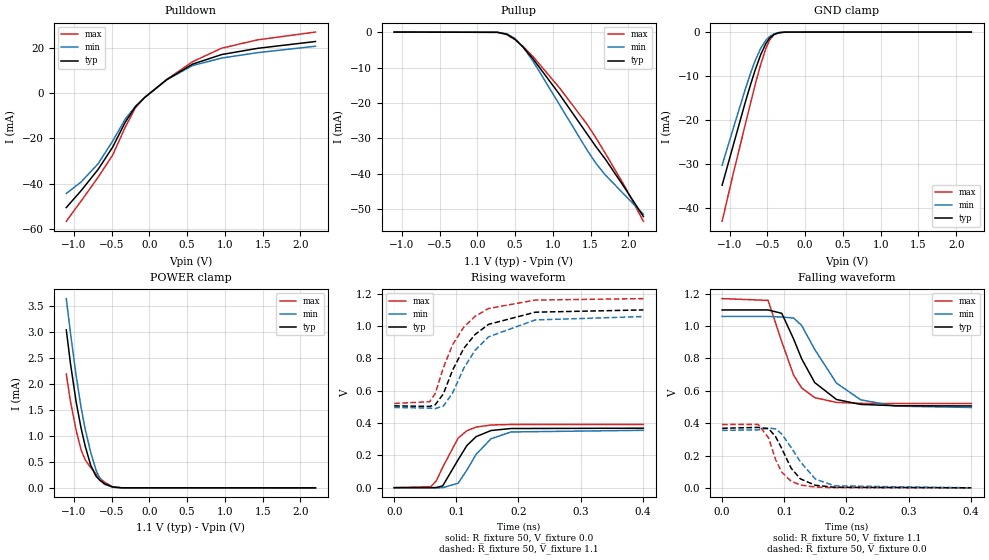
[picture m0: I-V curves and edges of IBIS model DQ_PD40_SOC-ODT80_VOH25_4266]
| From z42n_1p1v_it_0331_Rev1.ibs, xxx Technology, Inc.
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| DQ_PD40_SOC-ODT80_VOH25_4266
| (40 Ohm Pulldown, 80 Ohm System ODT Setting, VOH=VDDQ/2.5, 3200-4266Mbps)
[Model]   DQ_PD40_SOC-ODT80_VOH25_4266
Model_type   I/O
Vinl = 160.000mV
Vinh = 280.000mV
Vmeas = 220.000mV
Vref = 0.0mV
Cref = 0.0pF
Rref = 80.000Ohm
|   typ   min   max
|C_comp   0.834pF   0.784pF   0.884pF
C_comp_pullup   0.4170pF   0.3920pF   0.4420pF
C_comp_pulldown   0.4170pF   0.3920pF   0.4420pF
| Note: C_comp changes when the ODT circuit is enabled.
[Model Spec]
| Input threshold voltage corners
Vinl   0.1600V   0.1520V   0.1740V
Vinh   0.2800V   0.2720V   0.2940V
| Measurement voltage corners
Vmeas   0.2200V   0.2120V   0.2340V
| Timing spec test load voltage corners
Vref   0.0000V   0.0000V   0.0000V
| Dynamic Overshoot Parameters from LPDDR4 Specification
D_overshoot_ampl_h   0.30   NA   NA
D_overshoot_ampl_l   0.30   NA   NA
D_overshoot_area_h   0.1n   NA   NA
D_overshoot_area_l   0.1n   NA   NA
[Voltage Range]   1.1000V   1.0600V   1.1700V
[Pullup Reference]   1.1000V   1.0600V   1.1700V
| Junction Temperature (Ambient temp is 35C typ 95C min -40C max)
[Temperature Range]   50.0   110.0   -40.0
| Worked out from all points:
|   slope of the pulldown table from 0 to 0.165 V, typ, clamps not added: 36.9 ohm
|   slope of the pullup table from 0 to 0.165 V, typ, clamps not added: 17.7 kohm
|   GND clamp passes 1 mA (typ) near -0.45 V on its own axis
|   POWER clamp passes 1 mA (typ) near -0.88 V on its own axis
|   rising waveform, R_fixture 50, V_fixture 0.0: 20-80 % time 34.6ps typ, 38.2ps min, 31.6ps max; typ from 0.001 V to 0.368 V
|   falling waveform, R_fixture 50, V_fixture 1.1: 20-80 % time 45.6ps typ, 57.6ps min, 35.8ps max; typ from 1.1 V to 0.507 V
|   rising waveform, R_fixture 50, V_fixture 1.1: 20-80 % time 56.3ps typ, 59.8ps min, 51.7ps max; typ from 0.507 V to 1.1 V
|   falling waveform, R_fixture 50, V_fixture 0.0: 20-80 % time 31.3ps typ, 39.3ps min, 25.3ps max; typ from 0.368 V to 0.001 V
[Pulldown]
|   Voltage   I(typ)   I(min)   I(max)
-1.1V     -50.64mA   -44.4mA    -56.73mA
-905.3mV  -43.23mA   -39.35mA   -47.84mA
-677.6mV  -33.7mA    -31.18mA   -37.18mA
-486.2mV  -23.86mA   -21.19mA   -27.39mA
-317.9mV  -12.72mA   -11.35mA   -14.94mA
-182.6mV  -5.881mA   -5.661mA   -6.291mA
-63.8mV   -1.901mA   -1.884mA   -1.878mA
229.9mV   6.064mA    5.989mA    6.147mA
573.1mV   12.96mA    12.33mA    14.03mA
959.2mV   17.21mA    15.66mA    20.03mA
1.434V    19.96mA    18.04mA    23.71mA
2.2V      22.98mA    20.89mA    27.18mA
[GND Clamp]
|   Voltage   I(typ)   I(min)   I(max)
-1.1V     -34.75mA   -30.21mA   -42.92mA
-944.9mV  -25.23mA   -21.44mA   -31.56mA
-793.1mV  -15.92mA   -12.96mA   -20.97mA
-720.5mV  -11.75mA   -9.183mA   -15.88mA
-661.1mV  -8.569mA   -6.434mA   -11.86mA
-588.5mV  -5.115mA   -3.68mA    -7.305mA
-519.2mV  -2.566mA   -1.832mA   -3.663mA
-466.4mV  -1.295mA   -942uA     -1.691mA
-413.6mV  -565.1uA   -416.8uA   -621.5uA
-350.9mV  -165.9uA   -125.8uA   -147.9uA
-261.8mV  -17.69uA   -15.38uA   -11.03uA
2.2V      0A         0A         0A
[Pullup]
|   Voltage   I(typ)   I(min)   I(max)
-1.1V     4.106uA    7.431uA    1.361uA
266.2mV   -69.11uA   -66.76uA   -71.72uA
391.6mV   -603.6uA   -501uA     -718.6uA
500.5mV   -2.041mA   -1.829mA   -2.142mA
606.1mV   -4.221mA   -4.208mA   -4.061mA
741.4mV   -7.628mA   -8.301mA   -6.975mA
1.088V    -17.54mA   -20.45mA   -15.71mA
1.458V    -28.85mA   -33.42mA   -26.13mA
1.573V    -32.37mA   -37.08mA   -29.9mA
1.695V    -35.82mA   -40.29mA   -34.18mA
1.946V    -43.74mA   -45.84mA   -43.25mA
2.2V      -52.05mA   -51.4mA    -53.39mA
[POWER Clamp]
|   Voltage   I(typ)   I(min)   I(max)
-1.1V     3.033mA    3.633mA    2.184mA
-1.044V   2.381mA    2.967mA    1.653mA
-968mV    1.637mA    2.139mA    1.094mA
-905.3mV  1.155mA    1.553mA    732.3uA
-849.2mV  799uA      1.125mA    535.5uA
-776.6mV  434.1uA    683.2uA    390.2uA
-707.3mV  225.5uA    345.3uA    267.6uA
-651.2mV  138.6uA    162.4uA    181.2uA
-595.1mV  80.76uA    68.29uA    109.2uA
-486.2mV  16.72uA    10.16uA    20.92uA
-367.4mV  1.19uA     876.5nA    944.1nA
2.2V      0A         0A         0A
[Ramp]
|   typ   min   max
| 20% - 80%
dV/dt_r   220.67m/34.62p   212.99m/38.16p   234.73m/31.58p
dV/dt_f   356.03m/45.65p   337.71m/57.58p   389.19m/35.75p
| 25% - 75%
|dV/dt_r   183.89m/27.56p   177.50m/30.42p   195.60m/25.07p
|dV/dt_f   296.69m/36.41p   281.42m/45.98p   324.32m/28.47p
R_load = 50
[Rising Waveform]
R_fixture = 50
V_fixture = 0.0
|   Time   V(typ)   V(min)   V(max)
0s        576.2uV    460uV      427uV
59ps      302.1uV    60.2uV     6.861mV
68ps      1.699mV    -527.5uV   44.07mV
78ps      11.14mV    298.1uV    126.8mV
103ps     173.9mV    28.19mV    307.8mV
117ps     261.2mV    109.9mV    352.6mV
132ps     316.6mV    207.5mV    375.5mV
156ps     354.2mV    303.3mV    388.2mV
188ps     366.4mV    345.1mV    391.3mV
401ps     368.4mV    355.4mV    391.6mV
[Falling Waveform]
R_fixture   = 50
V_fixture   = 1.1
V_fixture_min = 1.06
V_fixture_max = 1.17
|   Time   V(typ)   V(min)   V(max)
0s        1.1V       1.06V      1.17V
74ps      1.1V       1.06V      1.159V
96ps      1.079V     1.056V     903.5mV
115ps     920.8mV    1.05V      697.3mV
128ps     797.9mV    1.004V     618.1mV
149ps     651.2mV    856.1mV    557.7mV
184ps     546.5mV    648mV      528.4mV
223ps     516mV      544.4mV    522.5mV
279ps     507.9mV    505.4mV    521.5mV
401ps     506.6mV    497.1mV    521.4mV
[Rising Waveform]
R_fixture   = 50
V_fixture   = 1.1
V_fixture_min = 1.06
V_fixture_max = 1.17
|   Time   V(typ)   V(min)   V(max)
0s        506.5mV    496.8mV    521.3mV
57ps      503.2mV    492.6mV    532.3mV
66ps      513.1mV    490.1mV    582.9mV
79ps      579.9mV    504.6mV    741.8mV
94ps      727.7mV    586.1mV    885.4mV
112ps     862.2mV    739.3mV    993.7mV
130ps     947.6mV    849.8mV    1.06V
152ps     1.011V     933.9mV    1.109V
227ps     1.086V     1.038V     1.161V
401ps     1.1V       1.059V     1.17V
[Falling Waveform]
R_fixture = 50
V_fixture = 0.0
|   Time   V(typ)   V(min)   V(max)
0s        368.5mV    355.6mV    391.7mV
58ps      374mV      358.9mV    392.3mV
75ps      365.9mV    370.3mV    307.4mV
86ps      317mV      364.6mV    174.7mV
96ps      243.4mV    333.4mV    97.47mV
111ps     122.2mV    250.2mV    41.27mV
126ps     55.84mV    161.1mV    17.92mV
150ps     16.22mV    54.74mV    5.098mV
181ps     3.876mV    12.57mV    1.335mV
401ps     621.2uV    531.5uV    445.4uV
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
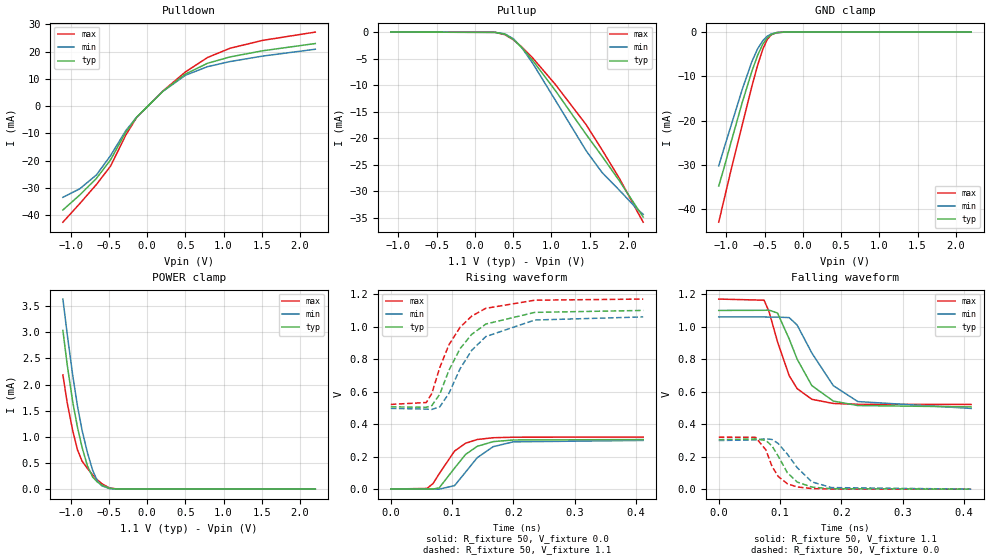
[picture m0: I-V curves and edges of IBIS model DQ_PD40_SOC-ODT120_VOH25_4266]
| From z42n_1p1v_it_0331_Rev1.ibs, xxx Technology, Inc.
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| DQ_PD40_SOC-ODT120_VOH25_4266
| (40 Ohm Pulldown, 120 Ohm System ODT Setting, VOH=VDDQ/2.5, 3200-4266Mbps)
[Model]   DQ_PD40_SOC-ODT120_VOH25_4266
Model_type   I/O
Vinl = 160.000mV
Vinh = 280.000mV
Vmeas = 220.000mV
Vref = 0.0mV
Cref = 0.0pF
Rref = 120.000Ohm
|   typ   min   max
|C_comp   0.834pF   0.784pF   0.884pF
C_comp_pullup   0.4170pF   0.3920pF   0.4420pF
C_comp_pulldown   0.4170pF   0.3920pF   0.4420pF
| Note: C_comp changes when the ODT circuit is enabled.
[Model Spec]
| Input threshold voltage corners
Vinl   0.1600V   0.1520V   0.1740V
Vinh   0.2800V   0.2720V   0.2940V
| Measurement voltage corners
Vmeas   0.2200V   0.2120V   0.2340V
| Timing spec test load voltage corners
Vref   0.0000V   0.0000V   0.0000V
| Dynamic Overshoot Parameters from LPDDR4 Specification
D_overshoot_ampl_h   0.30   NA   NA
D_overshoot_ampl_l   0.30   NA   NA
D_overshoot_area_h   0.1n   NA   NA
D_overshoot_area_l   0.1n   NA   NA
[Voltage Range]   1.1000V   1.0600V   1.1700V
[Pullup Reference]   1.1000V   1.0600V   1.1700V
| Junction Temperature (Ambient temp is 35C typ 95C min -40C max)
[Temperature Range]   50.0   110.0   -40.0
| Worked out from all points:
|   slope of the pulldown table from 0 to 0.165 V, typ, clamps not added: 37 ohm
|   slope of the pullup table from 0 to 0.165 V, typ, clamps not added: 26.2 kohm
|   GND clamp passes 1 mA (typ) near -0.45 V on its own axis
|   POWER clamp passes 1 mA (typ) near -0.88 V on its own axis
|   rising waveform, R_fixture 50, V_fixture 0.0: 20-80 % time 39.5ps typ, 42.9ps min, 36.2ps max; typ from 0 V to 0.305 V
|   falling waveform, R_fixture 50, V_fixture 1.1: 20-80 % time 45.4ps typ, 57.2ps min, 35.6ps max; typ from 1.1 V to 0.507 V
|   rising waveform, R_fixture 50, V_fixture 1.1: 20-80 % time 56.6ps typ, 60.9ps min, 51.9ps max; typ from 0.507 V to 1.1 V
|   falling waveform, R_fixture 50, V_fixture 0.0: 20-80 % time 30.7ps typ, 38.9ps min, 25.1ps max; typ from 0.305 V to 0 V
[Pulldown]
|   Voltage   I(typ)   I(min)   I(max)
-1.1V     -38.07mA   -33.41mA   -42.54mA
-878.9mV  -32.54mA   -30.28mA   -35.7mA
-661.1mV  -26.45mA   -25.2mA    -28.7mA
-476.3mV  -19.65mA   -18.09mA   -21.95mA
-278.3mV  -9.557mA   -8.983mA   -10.63mA
-136.4mV  -4.093mA   -4.052mA   -4.136mA
206.8mV   5.497mA    5.437mA    5.555mA
503.8mV   11.82mA    11.37mA    12.6mA
790.9mV   15.74mA    14.5mA     17.86mA
1.085V    18.07mA    16.37mA    21.25mA
1.51V     20.32mA    18.37mA    24.13mA
2.2V      22.98mA    20.89mA    27.18mA
[GND Clamp]
|   Voltage   I(typ)   I(min)   I(max)
-1.1V     -34.75mA   -30.2mA    -42.92mA
-1.027V   -30.44mA   -26.03mA   -37.57mA
-938.3mV  -24.82mA   -21.07mA   -31.09mA
-793.1mV  -15.92mA   -12.96mA   -20.97mA
-667.7mV  -8.911mA   -6.72mA    -12.3mA
-591.8mV  -5.257mA   -3.788mA   -7.499mA
-522.5mV  -2.668mA   -1.903mA   -3.813mA
-466.4mV  -1.296mA   -941.9uA   -1.691mA
-413.6mV  -565.7uA   -416.1uA   -620.3uA
-341mV    -133.7uA   -101.7uA   -113.6uA
-235.4mV  -8.286uA   -7.677uA   -4.435uA
2.2V      0A         0A         0A
[Pullup]
|   Voltage   I(typ)   I(min)   I(max)
-1.1V     2.737uA    4.954uA    907.4nA
262.9mV   -43.18uA   -42.29uA   -44.35uA
391.6mV   -402.5uA   -334.6uA   -480uA
503.8mV   -1.404mA   -1.264mA   -1.47mA
616mV     -2.983mA   -3.003mA   -2.852mA
754.6mV   -5.353mA   -5.87mA    -4.876mA
1.052V    -11.04mA   -12.87mA   -9.878mA
1.454V    -19.3mA    -22.38mA   -17.47mA
1.662V    -23.42mA   -26.49mA   -22.21mA
1.89V     -28.09mA   -29.85mA   -27.63mA
2.124V    -33.25mA   -33.44mA   -33.89mA
2.2V      -34.89mA   -34.37mA   -35.86mA
[POWER Clamp]
|   Voltage   I(typ)   I(min)   I(max)
-1.1V     3.033mA    3.633mA    2.184mA
-1.044V   2.381mA    2.967mA    1.653mA
-971.3mV  1.665mA    2.173mA    1.116mA
-908.6mV  1.178mA    1.582mA    748.3uA
-849.2mV  799uA      1.125mA    535.4uA
-779.9mV  447.8uA    701.5uA    396.3uA
-710.6mV  232.1uA    359.2uA    273.1uA
-651.2mV  138.6uA    162.3uA    181.2uA
-591.8mV  77.93uA    64.79uA    105.5uA
-492.8mV  18.92uA    11.55uA    24.05uA
-383.9mV  1.747uA    1.208uA    1.464uA
2.2V      0A         0A         0A
[Ramp]
|   typ   min   max
| 20% - 80%
dV/dt_r   182.63m/39.52p   179.67m/42.87p   191.89m/36.17p
dV/dt_f   356.02m/45.43p   337.76m/57.23p   389.18m/35.61p
| 25% - 75%
|dV/dt_r   152.19m/31.51p   149.73m/34.19p   159.91m/28.73p
|dV/dt_f   296.69m/36.25p   281.46m/45.70p   324.32m/28.36p
R_load = 50
[Rising Waveform]
R_fixture = 50
V_fixture = 0.0
|   Time   V(typ)   V(min)   V(max)
0s        377.5uV    292.3uV    283.3uV
59ps      29.35uV    190.4uV    3.979mV
69ps      30.69uV    -457.8uV   34.24mV
79ps      7.624mV    -472.3uV   94.46mV
104ps     128.9mV    21.24mV    234.1mV
122ps     213.2mV    104.5mV    282.3mV
141ps     263.3mV    193mV      305.2mV
167ps     292.2mV    261.1mV    316.2mV
200ps     302.4mV    290.9mV    319.4mV
412ps     304.8mV    299.7mV    320.1mV
[Falling Waveform]
R_fixture   = 50
V_fixture   = 1.1
V_fixture_min = 1.06
V_fixture_max = 1.17
|   Time   V(typ)   V(min)   V(max)
0s        1.1V       1.06V      1.17V
74ps      1.101V     1.06V      1.163V
82ps      1.102V     1.059V     1.094V
96ps      1.084V     1.059V     906.4mV
115ps     924.5mV    1.056V     698.7mV
128ps     800.4mV    1.01V      619mV
152ps     637.4mV    838mV      553.2mV
187ps     542.5mV    637.2mV    527.6mV
227ps     514.8mV    539.3mV    522.4mV
412ps     506.6mV    497.1mV    521.4mV
[Rising Waveform]
R_fixture   = 50
V_fixture   = 1.1
V_fixture_min = 1.06
V_fixture_max = 1.17
|   Time   V(typ)   V(min)   V(max)
0s        506.5mV    496.8mV    521.3mV
58ps      503.5mV    492.4mV    533.1mV
67ps      514.3mV    490.5mV    589.3mV
80ps      585mV      506.6mV    749.4mV
95ps      732.5mV    590.2mV    889.3mV
113ps     864.4mV    740.7mV    996mV
132ps     952.6mV    854.2mV    1.065V
155ps     1.016V     938.9mV    1.113V
235ps     1.088V     1.041V     1.163V
412ps     1.1V       1.06V      1.17V
[Falling Waveform]
R_fixture = 50
V_fixture = 0.0
|   Time   V(typ)   V(min)   V(max)
0s        304.8mV    299.8mV    320.2mV
60ps      309.4mV    303.3mV    319.7mV
77ps      300.4mV    311mV      241.6mV
87ps      265.8mV    305.8mV    140.5mV
97ps      204.3mV    281.6mV    78.68mV
112ps     101.5mV    215.9mV    33.64mV
128ps     44.24mV    133.4mV    13.96mV
152ps     13.01mV    45.03mV    3.974mV
184ps     2.987mV    10.05mV    995uV
412ps     437.7uV    380.9uV    305.7uV
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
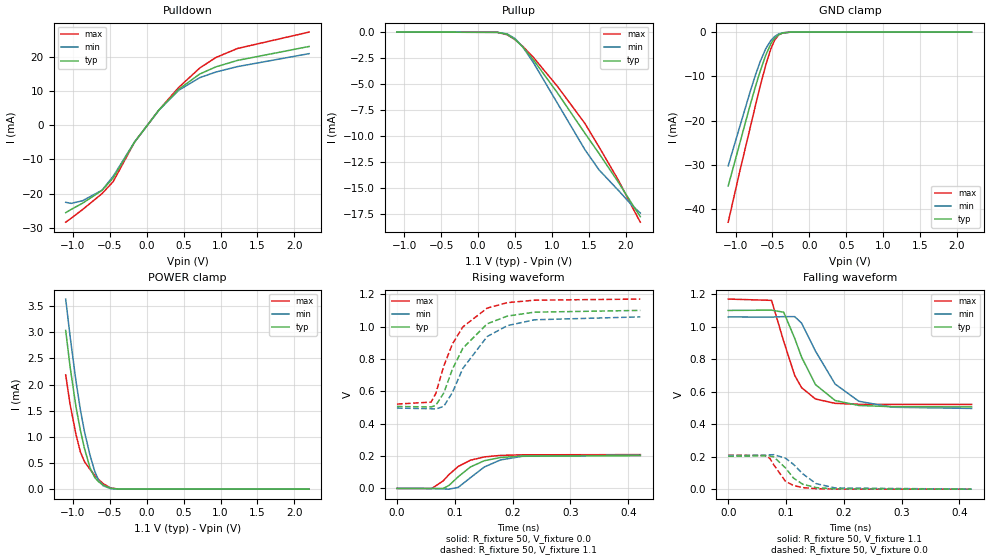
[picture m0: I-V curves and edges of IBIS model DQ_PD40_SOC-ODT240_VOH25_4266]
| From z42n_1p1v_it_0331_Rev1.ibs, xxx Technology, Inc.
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| DQ_PD40_SOC-ODT240_VOH25_4266
| (40 Ohm Pulldown, 240 Ohm System ODT Setting, VOH=VDDQ/2.5, 3200-4266Mbps)
[Model]   DQ_PD40_SOC-ODT240_VOH25_4266
Model_type   I/O
Vinl = 160.000mV
Vinh = 280.000mV
Vmeas = 220.000mV
Vref = 0.0mV
Cref = 0.0pF
Rref = 240.000Ohm
|   typ   min   max
|C_comp   0.834pF   0.784pF   0.884pF
C_comp_pullup   0.4170pF   0.3920pF   0.4420pF
C_comp_pulldown   0.4170pF   0.3920pF   0.4420pF
| Note: C_comp changes when the ODT circuit is enabled.
[Model Spec]
| Input threshold voltage corners
Vinl   0.1600V   0.1520V   0.1740V
Vinh   0.2800V   0.2720V   0.2940V
| Measurement voltage corners
Vmeas   0.2200V   0.2120V   0.2340V
| Timing spec test load voltage corners
Vref   0.0000V   0.0000V   0.0000V
| Dynamic Overshoot Parameters from LPDDR4 Specification
D_overshoot_ampl_h   0.30   NA   NA
D_overshoot_ampl_l   0.30   NA   NA
D_overshoot_area_h   0.1n   NA   NA
D_overshoot_area_l   0.1n   NA   NA
[Voltage Range]   1.1000V   1.0600V   1.1700V
[Pullup Reference]   1.1000V   1.0600V   1.1700V
| Junction Temperature (Ambient temp is 35C typ 95C min -40C max)
[Temperature Range]   50.0   110.0   -40.0
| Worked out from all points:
|   slope of the pulldown table from 0 to 0.165 V, typ, clamps not added: 37 ohm
|   slope of the pullup table from 0 to 0.165 V, typ, clamps not added: 52.8 kohm
|   GND clamp passes 1 mA (typ) near -0.45 V on its own axis
|   POWER clamp passes 1 mA (typ) near -0.88 V on its own axis
|   rising waveform, R_fixture 50, V_fixture 0.0: 20-80 % time 46.7ps typ, 50.5ps min, 43.1ps max; typ from 0 V to 0.203 V
|   falling waveform, R_fixture 50, V_fixture 1.1: 20-80 % time 45.2ps typ, 56.8ps min, 35.5ps max; typ from 1.1 V to 0.507 V
|   rising waveform, R_fixture 50, V_fixture 1.1: 20-80 % time 56.8ps typ, 61.4ps min, 52ps max; typ from 0.507 V to 1.1 V
|   falling waveform, R_fixture 50, V_fixture 0.0: 20-80 % time 30.6ps typ, 39ps min, 25.4ps max; typ from 0.203 V to 0 V
[Pulldown]
|   Voltage   I(typ)   I(min)   I(max)
-1.1V     -25.52mA   -22.49mA   -28.3mA
-1.027V   -24.58mA   -22.81mA   -27.17mA
-872.3mV  -22.77mA   -22.05mA   -24.63mA
-608.3mV  -19.03mA   -18.98mA   -19.98mA
-456.5mV  -15.41mA   -14.91mA   -16.46mA
-166.1mV  -4.898mA   -4.887mA   -4.932mA
163.9mV   4.417mA    4.379mA    4.439mA
431.2mV   10.48mA    10.18mA    11.01mA
718.3mV   14.95mA    13.89mA    16.71mA
939.4mV   17.06mA    15.54mA    19.8mA
1.23V     18.92mA    17.11mA    22.4mA
2.2V      22.98mA    20.89mA    27.18mA
[GND Clamp]
|   Voltage   I(typ)   I(min)   I(max)
-1.1V     -34.75mA   -30.2mA    -42.92mA
-948.2mV  -25.44mA   -21.62mA   -31.8mA
-803mV    -16.51mA   -13.5mA    -21.66mA
-727.1mV  -12.12mA   -9.51mA    -16.34mA
-667.7mV  -8.911mA   -6.72mA    -12.3mA
-591.8mV  -5.257mA   -3.788mA   -7.499mA
-522.5mV  -2.667mA   -1.904mA   -3.812mA
-469.7mV  -1.356mA   -987.6uA   -1.788mA
-413.6mV  -564.5uA   -417.2uA   -620.9uA
-357.5mV  -191.8uA   -144.8uA   -173.7uA
-251.9mV  -13.3uA    -12.15uA   -8.039uA
2.2V      0A         0A         0A
[Pullup]
|   Voltage   I(typ)   I(min)   I(max)
-1.1V     1.369uA    2.477uA    453.9nA
259.6mV   -20.21uA   -19.81uA   -20.48uA
394.9mV   -211.9uA   -176.5uA   -251.6uA
503.8mV   -707.1uA   -636.7uA   -739uA
606.1mV   -1.427mA   -1.427mA   -1.37mA
748mV     -2.645mA   -2.901mA   -2.408mA
1.078V    -5.855mA   -6.856mA   -5.228mA
1.451V    -9.741mA   -11.32mA   -8.798mA
1.642V    -11.68mA   -13.25mA   -11.05mA
1.91V     -14.51mA   -15.26mA   -14.32mA
2.091V    -16.54mA   -16.68mA   -16.82mA
2.2V      -17.73mA   -17.38mA   -18.26mA
[POWER Clamp]
|   Voltage   I(typ)   I(min)   I(max)
-1.1V     3.033mA    3.633mA    2.184mA
-1.041V   2.345mA    2.929mA    1.625mA
-961.4mV  1.581mA    2.073mA    1.051mA
-902mV    1.132mA    1.526mA    716.9uA
-845.9mV  779.9uA    1.103mA    527.5uA
-770mV    407.6uA    647.4uA    378uA
-707.3mV  225.4uA    345.4uA    267.6uA
-654.5mV  142.7uA    170.4uA    185.9uA
-591.8mV  77.91uA    64.82uA    105.5uA
-492.8mV  18.88uA    11.59uA    24.04uA
-383.9mV  1.744uA    1.217uA    1.464uA
2.2V      0A         0A         0A
[Ramp]
|   typ   min   max
| 20% - 80%
dV/dt_r   121.55m/46.67p   123.85m/50.51p   125.33m/43.15p
dV/dt_f   356.01m/45.23p   337.78m/56.84p   389.18m/35.50p
| 25% - 75%
|dV/dt_r   101.29m/37.15p   103.21m/40.35p   104.44m/34.27p
|dV/dt_f   296.68m/36.09p   281.48m/45.41p   324.32m/28.26p
R_load = 50
[Rising Waveform]
R_fixture = 50
V_fixture = 0.0
|   Time   V(typ)   V(min)   V(max)
0s        176.8uV    122uV      138.5uV
60ps      -802.2uV   311.5uV    -529.6uV
80ps      -41.68uV   -2.714mV   46.83mV
90ps      18.87mV    -4.319mV   85.83mV
106ps     72.46mV    6.803mV    135.8mV
127ps     132.6mV    66.16mV    174.4mV
151ps     171.4mV    132.4mV    194.9mV
179ps     191.2mV    176.2mV    204.2mV
217ps     200mV      198.7mV    207.9mV
421ps     202.8mV    206.5mV    209mV
[Falling Waveform]
R_fixture   = 50
V_fixture   = 1.1
V_fixture_min = 1.06
V_fixture_max = 1.17
|   Time   V(typ)   V(min)   V(max)
0s        1.1V       1.06V      1.17V
75ps      1.102V     1.059V     1.162V
96ps      1.089V     1.062V     910.1mV
115ps     928.7mV    1.062V     700.4mV
127ps     812.4mV    1.022V     624.6mV
151ps     643.7mV    849.6mV    555.1mV
185ps     545.7mV    647mV      528.3mV
226ps     515.2mV    541.1mV    522.5mV
284ps     507.7mV    504.4mV    521.5mV
421ps     506.6mV    497mV      521.4mV
[Rising Waveform]
R_fixture   = 50
V_fixture   = 1.1
V_fixture_min = 1.06
V_fixture_max = 1.17
|   Time   V(typ)   V(min)   V(max)
0s        506.5mV    496.8mV    521.3mV
59ps      503.5mV    492.4mV    533.3mV
67ps      512.3mV    490.5mV    585.2mV
81ps      589.8mV    507.4mV    756.1mV
96ps      737mV      593.3mV    892.7mV
114ps     866.5mV    741.7mV    998.1mV
156ps     1.017V     938.3mV    1.114V
191ps     1.065V     1.006V     1.148V
238ps     1.089V     1.042V     1.163V
421ps     1.1V       1.06V      1.17V
[Falling Waveform]
R_fixture = 50
V_fixture = 0.0
|   Time   V(typ)   V(min)   V(max)
0s        202.8mV    206.6mV    209.1mV
63ps      205.3mV    209.1mV    207.3mV
72ps      204.3mV    211.6mV    189.9mV
79ps      198.2mV    212.3mV    149mV
99ps      131.2mV    191.3mV    48.89mV
113ps     68.32mV    152.7mV    22.64mV
129ps     30.48mV    94.61mV    9.568mV
152ps     9.725mV    34.27mV    2.912mV
185ps     2.141mV    7.587mV    651.9uV
421ps     240.1uV    217.1uV    158.7uV
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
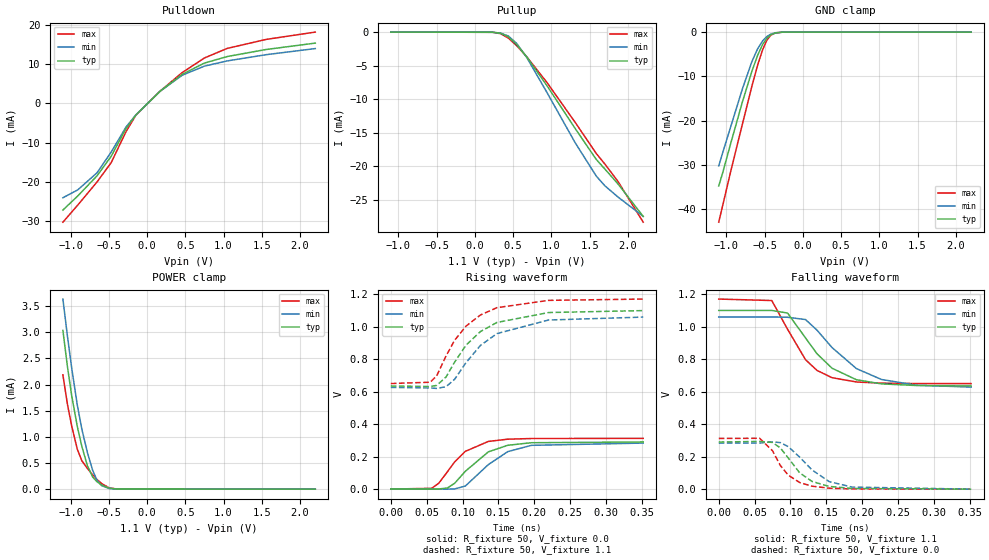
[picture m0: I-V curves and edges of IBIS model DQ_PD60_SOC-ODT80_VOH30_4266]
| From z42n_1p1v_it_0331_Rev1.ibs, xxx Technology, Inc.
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| DQ_PD60_SOC-ODT80_VOH30_4266
| (60 Ohm Pulldown, 80 Ohm System ODT Setting, VOH=VDDQ/3.0, 3200-4266Mbps)
[Model]   DQ_PD60_SOC-ODT80_VOH30_4266
Model_type   I/O
Vinl = 123.333mV
Vinh = 243.333mV
Vmeas = 183.333mV
Vref = 0.0mV
Cref = 0.0pF
Rref = 80.000Ohm
|   typ   min   max
|C_comp   0.834pF   0.784pF   0.884pF
C_comp_pullup   0.4170pF   0.3920pF   0.4420pF
C_comp_pulldown   0.4170pF   0.3920pF   0.4420pF
| Note: C_comp changes when the ODT circuit is enabled.
[Model Spec]
| Input threshold voltage corners
Vinl   0.1233V   0.1167V   0.1350V
Vinh   0.2433V   0.2367V   0.2550V
| Measurement voltage corners
Vmeas   0.1833V   0.1767V   0.1950V
| Timing spec test load voltage corners
Vref   0.0000V   0.0000V   0.0000V
| Dynamic Overshoot Parameters from LPDDR4 Specification
D_overshoot_ampl_h   0.30   NA   NA
D_overshoot_ampl_l   0.30   NA   NA
D_overshoot_area_h   0.1n   NA   NA
D_overshoot_area_l   0.1n   NA   NA
[Voltage Range]   1.1000V   1.0600V   1.1700V
[Pullup Reference]   1.1000V   1.0600V   1.1700V
| Junction Temperature (Ambient temp is 35C typ 95C min -40C max)
[Temperature Range]   50.0   110.0   -40.0
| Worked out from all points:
|   slope of the pulldown table from 0 to 0.165 V, typ, clamps not added: 55 ohm
|   slope of the pullup table from 0 to 0.165 V, typ, clamps not added: 25.9 kohm
|   GND clamp passes 1 mA (typ) near -0.45 V on its own axis
|   POWER clamp passes 1 mA (typ) near -0.88 V on its own axis
|   rising waveform, R_fixture 50, V_fixture 0.0: 20-80 % time 43.3ps typ, 46.4ps min, 37.8ps max; typ from 0 V to 0.29 V
|   falling waveform, R_fixture 50, V_fixture 1.1: 20-80 % time 53.5ps typ, 65.3ps min, 43.1ps max; typ from 1.1 V to 0.635 V
|   rising waveform, R_fixture 50, V_fixture 1.1: 20-80 % time 55.9ps typ, 59.8ps min, 52.2ps max; typ from 0.635 V to 1.1 V
|   falling waveform, R_fixture 50, V_fixture 0.0: 20-80 % time 35.2ps typ, 42.9ps min, 30.6ps max; typ from 0.29 V to 0 V
[Pulldown]
|   Voltage   I(typ)   I(min)   I(max)
-1.1V     -27.21mA   -24.07mA   -30.3mA
-905.3mV  -23.61mA   -22.06mA   -25.93mA
-654.5mV  -18.5mA    -17.72mA   -20.06mA
-469.7mV  -13.53mA   -12.46mA   -15.16mA
-275mV    -6.456mA   -6.064mA   -7.225mA
-146.3mV  -2.991mA   -2.956mA   -3.046mA
170.5mV   3.084mA    3.057mA    3.103mA
460.9mV   7.412mA    7.167mA    7.842mA
751.3mV   10.26mA    9.481mA    11.56mA
1.048V    11.92mA    10.8mA     13.99mA
1.556V    13.71mA    12.39mA    16.28mA
2.2V      15.34mA    13.95mA    18.15mA
[GND Clamp]
|   Voltage   I(typ)   I(min)   I(max)
-1.1V     -34.74mA   -30.21mA   -42.91mA
-1.05V    -31.86mA   -27.33mA   -39.27mA
-944.9mV  -25.23mA   -21.44mA   -31.55mA
-789.8mV  -15.72mA   -12.78mA   -20.72mA
-667.7mV  -8.907mA   -6.721mA   -12.29mA
-591.8mV  -5.255mA   -3.789mA   -7.493mA
-525.8mV  -2.767mA   -1.976mA   -3.963mA
-469.7mV  -1.357mA   -987.5uA   -1.789mA
-416.9mV  -597.7uA   -440.8uA   -664.7uA
-357.5mV  -192.1uA   -144.4uA   -173.8uA
-261.8mV  -18.19uA   -15.43uA   -11.09uA
2.2V      0A         0A         0A
[Pullup]
|   Voltage   I(typ)   I(min)   I(max)
-1.1V     3.138uA    4.837uA    1.415uA
233.2mV   -24.45uA   -24.33uA   -25.32uA
335.5mV   -171.1uA   -142.6uA   -234.7uA
437.8mV   -720.1uA   -591.4uA   -906.5uA
546.7mV   -1.865mA   -1.708mA   -2.036mA
678.7mV   -3.725mA   -3.812mA   -3.703mA
942.7mV   -8.017mA   -9.037mA   -7.538mA
1.312V    -14.42mA   -16.55mA   -13.5mA
1.586V    -19.01mA   -21.49mA   -18.12mA
1.698V    -20.43mA   -22.94mA   -19.69mA
1.87V     -22.66mA   -24.62mA   -22.29mA
2.2V      -27.52mA   -27.51mA   -28.38mA
[POWER Clamp]
|   Voltage   I(typ)   I(min)   I(max)
-1.1V     3.033mA    3.633mA    2.184mA
-1.041V   2.345mA    2.929mA    1.625mA
-984.5mV  1.782mA    2.31mA     1.205mA
-911.9mV  1.2mA      1.61mA     764.2uA
-852.5mV  818.5uA    1.148mA    543.6uA
-779.9mV  447.9uA    701.4uA    396.3uA
-710.6mV  232.2uA    359uA      273.1uA
-657.8mV  146.8uA    178.8uA    190.7uA
-595.1mV  80.77uA    68.34uA    109.3uA
-496.1mV  20.08uA    12.34uA    25.75uA
-393.8mV  2.22uA     1.486uA    1.931uA
2.2V      0A         0A         0A
[Ramp]
|   typ   min   max
| 20% - 80%
dV/dt_r   173.90m/43.27p   169.84m/46.36p   187.29m/37.76p
dV/dt_f   278.79m/53.47p   259.06m/65.27p   312.06m/43.11p
| 25% - 75%
|dV/dt_r   144.91m/34.53p   141.54m/37.00p   156.08m/29.98p
|dV/dt_f   232.32m/42.62p   215.88m/52.06p   260.05m/34.32p
R_load = 50
[Rising Waveform]
R_fixture = 50
V_fixture = 0.0
|   Time   V(typ)   V(min)   V(max)
0s        344.9uV    291.3uV    254.4uV
57ps      51.68uV    201.5uV    4.789mV
67ps      533.3uV    -409.3uV   36.71mV
79ps      7.179mV    -265.6uV   107.1mV
89ps      35.87mV    1.107mV    167.3mV
104ps     109.9mV    19mV       232.6mV
136ps     229.4mV    150.8mV    293.5mV
163ps     269.8mV    230.6mV    307.3mV
196ps     285.5mV    269.4mV    311.4mV
352ps     290.2mV    283.4mV    312.4mV
[Falling Waveform]
R_fixture   = 50
V_fixture   = 1.1
V_fixture_min = 1.06
V_fixture_max = 1.17
|   Time   V(typ)   V(min)   V(max)
0s        1.1V       1.06V      1.17V
74ps      1.1V       1.06V      1.161V
96ps      1.084V     1.058V     984.3mV
121ps     931mV      1.044V     797.1mV
137ps     833.7mV    979mV      731.2mV
158ps     744.4mV    871.7mV    686.2mV
192ps     673.6mV    742.3mV    659.8mV
227ps     648.1mV    675.1mV    652.5mV
276ps     638mV      640mV      650.3mV
352ps     635.3mV    628.2mV    649.9mV
[Rising Waveform]
R_fixture   = 50
V_fixture   = 1.1
V_fixture_min = 1.06
V_fixture_max = 1.17
|   Time   V(typ)   V(min)   V(max)
0s        635mV      626.1mV    649.8mV
55ps      631.5mV    622.6mV    658.1mV
64ps      638.4mV    619.8mV    697.4mV
77ps      689.9mV    630.5mV    819.7mV
89ps      782mV      676.2mV    916.2mV
105ps     886.7mV    779.3mV    1.004V
125ps     970mV      884.6mV    1.072V
148ps     1.026V     957.4mV    1.117V
220ps     1.087V     1.041V     1.162V
352ps     1.099V     1.059V     1.17V
[Falling Waveform]
R_fixture = 50
V_fixture = 0.0
|   Time   V(typ)   V(min)   V(max)
0s        290.3mV    283.5mV    312.5mV
57ps      294.1mV    284.3mV    313.4mV
75ps      287.8mV    291.4mV    236.7mV
86ps      253.6mV    286.7mV    145.3mV
97ps      191.9mV    262mV      86.31mV
113ps     100.3mV    196.9mV    40.93mV
130ps     48.07mV    118.9mV    18.71mV
154ps     17.23mV    46.78mV    6.32mV
186ps     4.672mV    13.04mV    1.688mV
352ps     425.7uV    424.8uV    278.3uV
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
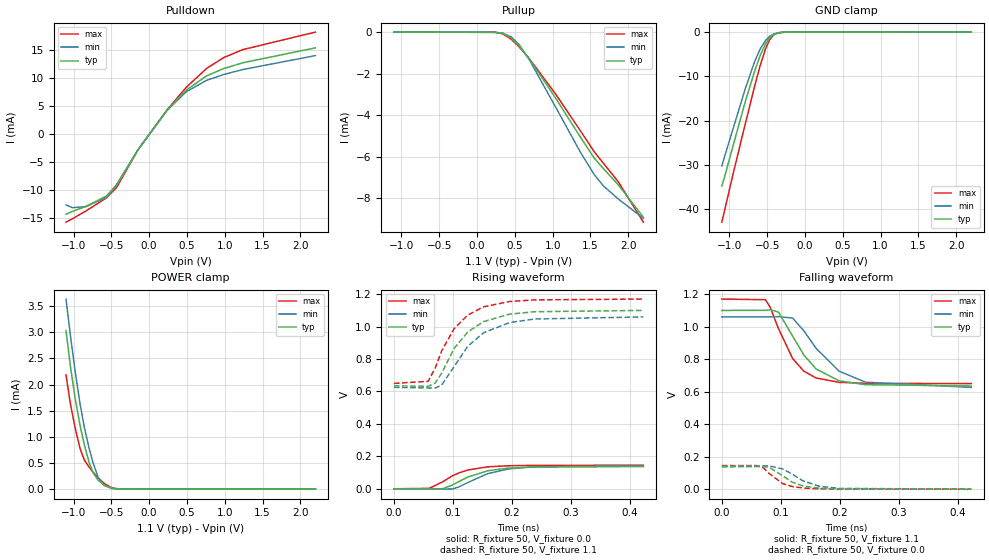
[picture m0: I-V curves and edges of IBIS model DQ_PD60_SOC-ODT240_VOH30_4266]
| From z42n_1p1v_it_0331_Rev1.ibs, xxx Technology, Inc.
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| DQ_PD60_SOC-ODT240_VOH30_4266
| (60 Ohm Pulldown, 240 Ohm System ODT Setting, VOH=VDDQ/3.0, 3200-4266Mbps)
[Model]   DQ_PD60_SOC-ODT240_VOH30_4266
Model_type   I/O
Vinl = 123.333mV
Vinh = 243.333mV
Vmeas = 183.333mV
Vref = 0.0mV
Cref = 0.0pF
Rref = 240.000Ohm
|   typ   min   max
|C_comp   0.834pF   0.784pF   0.884pF
C_comp_pullup   0.4170pF   0.3920pF   0.4420pF
C_comp_pulldown   0.4170pF   0.3920pF   0.4420pF
| Note: C_comp changes when the ODT circuit is enabled.
[Model Spec]
| Input threshold voltage corners
Vinl   0.1233V   0.1167V   0.1350V
Vinh   0.2433V   0.2367V   0.2550V
| Measurement voltage corners
Vmeas   0.1833V   0.1767V   0.1950V
| Timing spec test load voltage corners
Vref   0.0000V   0.0000V   0.0000V
| Dynamic Overshoot Parameters from LPDDR4 Specification
D_overshoot_ampl_h   0.30   NA   NA
D_overshoot_ampl_l   0.30   NA   NA
D_overshoot_area_h   0.1n   NA   NA
D_overshoot_area_l   0.1n   NA   NA
[Voltage Range]   1.1000V   1.0600V   1.1700V
[Pullup Reference]   1.1000V   1.0600V   1.1700V
| Junction Temperature (Ambient temp is 35C typ 95C min -40C max)
[Temperature Range]   50.0   110.0   -40.0
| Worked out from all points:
|   slope of the pulldown table from 0 to 0.165 V, typ, clamps not added: 55.1 ohm
|   slope of the pullup table from 0 to 0.165 V, typ, clamps not added: 79.5 kohm
|   GND clamp passes 1 mA (typ) near -0.45 V on its own axis
|   POWER clamp passes 1 mA (typ) near -0.88 V on its own axis
|   rising waveform, R_fixture 50, V_fixture 0.0: 20-80 % time 56.1ps typ, 58.7ps min, 49.2ps max; typ from 0 V to 0.137 V
|   falling waveform, R_fixture 50, V_fixture 1.1: 20-80 % time 53.3ps typ, 65.3ps min, 43ps max; typ from 1.1 V to 0.635 V
|   rising waveform, R_fixture 50, V_fixture 1.1: 20-80 % time 56.8ps typ, 61.4ps min, 52.3ps max; typ from 0.635 V to 1.1 V
|   falling waveform, R_fixture 50, V_fixture 0.0: 20-80 % time 35.3ps typ, 43.2ps min, 31.2ps max; typ from 0.137 V to 0 V
[Pulldown]
|   Voltage   I(typ)   I(min)   I(max)
-1.1V     -14.4mA    -12.73mA   -15.82mA
-1.014V   -13.89mA   -13.23mA   -15.2mA
-832.7mV  -12.97mA   -13.03mA   -13.79mA
-565.4mV  -11.15mA   -11.37mA   -11.47mA
-430.1mV  -9.173mA   -9.08mA    -9.608mA
-146.3mV  -2.862mA   -2.874mA   -2.845mA
236.5mV   4.185mA    4.131mA    4.248mA
490.6mV   7.773mA    7.484mA    8.275mA
761.2mV   10.33mA    9.536mA    11.67mA
985.6mV   11.63mA    10.57mA    13.59mA
1.24V     12.67mA    11.46mA    15.02mA
2.2V      15.34mA    13.95mA    18.15mA
[GND Clamp]
|   Voltage   I(typ)   I(min)   I(max)
-1.1V     -34.74mA   -30.21mA   -42.91mA
-1.05V    -31.86mA   -27.33mA   -39.27mA
-948.2mV  -25.43mA   -21.63mA   -31.79mA
-789.8mV  -15.72mA   -12.78mA   -20.72mA
-667.7mV  -8.907mA   -6.722mA   -12.29mA
-595.1mV  -5.399mA   -3.899mA   -7.688mA
-522.5mV  -2.664mA   -1.902mA   -3.811mA
-469.7mV  -1.357mA   -985.3uA   -1.787mA
-413.6mV  -564.6uA   -417.1uA   -621.3uA
-350.9mV  -166.4uA   -125.7uA   -147.1uA
-261.8mV  -17.6uA    -15.38uA   -10.98uA
2.2V      0A         0A         0A
[Pullup]
|   Voltage   I(typ)   I(min)   I(max)
-1.1V     1.046uA    1.612uA    471.3nA
236.5mV   -8.622uA   -8.614uA   -9.162uA
342.1mV   -63.39uA   -52.29uA   -87.37uA
454.3mV   -284.7uA   -236.9uA   -349.8uA
556.6mV   -657.1uA   -607.2uA   -711.4uA
688.6mV   -1.277mA   -1.311mA   -1.267mA
1.035V    -3.156mA   -3.586mA   -2.961mA
1.368V    -5.067mA   -5.791mA   -4.759mA
1.553V    -6.084mA   -6.882mA   -5.782mA
1.672V    -6.58mA    -7.414mA   -6.322mA
1.867V    -7.354mA   -8.039mA   -7.206mA
2.2V      -8.921mA   -8.969mA   -9.16mA
[POWER Clamp]
|   Voltage   I(typ)   I(min)   I(max)
-1.1V     3.033mA    3.633mA    2.184mA
-1.041V   2.345mA    2.929mA    1.625mA
-981.2mV  1.753mA    2.275mA    1.183mA
-911.9mV  1.201mA    1.61mA     765uA
-855.8mV  837.8uA    1.171mA    552.4uA
-796.4mV  521.2uA    794.8uA    427.2uA
-743.6mV  315.9uA    510.5uA    330.1uA
-674.3mV  169.2uA    226uA      215.1uA
-598.4mV  83.65uA    71.98uA    113uA
-489.5mV  17.8uA     10.84uA    22.44uA
-377.3mV  1.494uA    1.063uA    1.228uA
2.2V      0A         0A         0A
[Ramp]
|   typ   min   max
| 20% - 80%
dV/dt_r   82.37m/56.08p   84.12m/58.65p   87.14m/49.21p
dV/dt_f   278.93m/53.31p   260.12m/65.27p   312.07m/42.95p
| 25% - 75%
|dV/dt_r   68.64m/44.66p   70.10m/46.75p   72.61m/39.01p
|dV/dt_f   232.44m/42.36p   216.77m/52.05p   260.06m/34.08p
R_load = 50
[Rising Waveform]
R_fixture = 50
V_fixture = 0.0
|   Time   V(typ)   V(min)   V(max)
0s        103.6uV    73.47uV    82.18uV
60ps      -583.2uV   178.8uV    2.487mV
82ps      -304.4uV   -2.331mV   41.79mV
99ps      22.53mV    -768uV     79.41mV
110ps     44.57mV    11.05mV    97.71mV
125ps     71.84mV    38.3mV     115.5mV
159ps     111mV      93.38mV    135.3mV
194ps     127.8mV    122.1mV    142.1mV
234ps     134.5mV    134.7mV    144.4mV
423ps     137.4mV    140.3mV    145.3mV
[Falling Waveform]
R_fixture   = 50
V_fixture   = 1.1
V_fixture_min = 1.06
V_fixture_max = 1.17
|   Time   V(typ)   V(min)   V(max)
0s        1.1V       1.06V      1.17V
74ps      1.101V     1.06V      1.166V
82ps      1.104V     1.06V      1.119V
96ps      1.09V      1.062V     988.8mV
120ps     942.3mV    1.053V     804.4mV
139ps     826.3mV    975mV      726.2mV
160ps     739.4mV    866.2mV    684.1mV
199ps     666.7mV    725.8mV    657.6mV
244ps     643mV      658.3mV    651.3mV
423ps     635.1mV    626.5mV    649.9mV
[Rising Waveform]
R_fixture   = 50
V_fixture   = 1.1
V_fixture_min = 1.06
V_fixture_max = 1.17
|   Time   V(typ)   V(min)   V(max)
0s        635mV      626.1mV    649.8mV
58ps      632.2mV    621.7mV    662.8mV
70ps      651.6mV    621.2mV    744mV
81ps      713.4mV    639.5mV    850.5mV
102ps     864.9mV    753.3mV    987mV
125ps     966.4mV    878mV      1.071V
152ps     1.031V     962.1mV    1.122V
196ps     1.077V     1.025V     1.155V
239ps     1.092V     1.047V     1.165V
423ps     1.1V       1.06V      1.17V
[Falling Waveform]
R_fixture = 50
V_fixture = 0.0
|   Time   V(typ)   V(min)   V(max)
0s        137.5mV    140.4mV    145.3mV
60ps      139.2mV    141.3mV    144.9mV
71ps      139.3mV    143mV      130.1mV
80ps      135.1mV    143.2mV    97.37mV
103ps     83.15mV    124.9mV    34.38mV
119ps     43.39mV    93.49mV    16.7mV
138ps     19.64mV    50.54mV    7.114mV
165ps     6.452mV    18.03mV    2.166mV
199ps     1.7mV      4.94mV     553.8uV
423ps     163.3uV    162.5uV    98.65uV
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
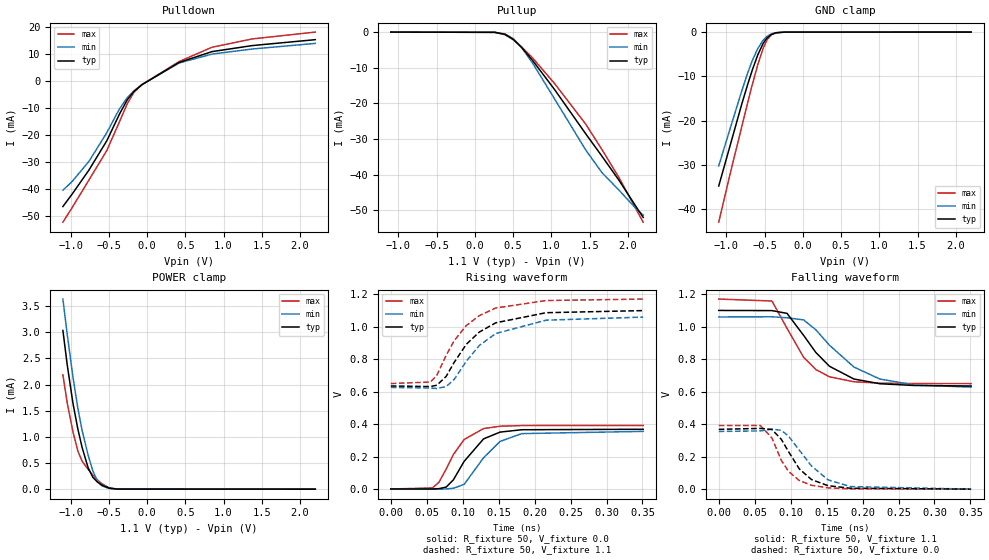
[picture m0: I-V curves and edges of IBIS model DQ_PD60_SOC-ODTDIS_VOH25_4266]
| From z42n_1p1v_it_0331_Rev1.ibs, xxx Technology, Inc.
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| DQ_PD60_SOC-ODTDIS_VOH25_4266
| (60 Ohm Pulldown, SOC ODT disabled setting, VOH=VDDQ/2.5 cal. point, 3200-4266Mbps)
[Model]   DQ_PD60_SOC-ODTDIS_VOH25_4266
Model_type   I/O
Vinl = 160.000mV
Vinh = 280.000mV
Vmeas = 220.000mV
Vref = 0.0mV
Cref = 0.0pF
|   typ   min   max
|C_comp   0.834pF   0.784pF   0.884pF
C_comp_pullup   0.4170pF   0.3920pF   0.4420pF
C_comp_pulldown   0.4170pF   0.3920pF   0.4420pF
| Note: C_comp changes when the ODT circuit is enabled.
[Model Spec]
| Input threshold voltage corners
Vinl   0.1600V   0.1520V   0.1740V
Vinh   0.2800V   0.2720V   0.2940V
| Measurement voltage corners
Vmeas   0.2200V   0.2120V   0.2340V
| Timing spec test load voltage corners
Vref   0.0000V   0.0000V   0.0000V
| Dynamic Overshoot Parameters from LPDDR4 Specification
D_overshoot_ampl_h   0.30   NA   NA
D_overshoot_ampl_l   0.30   NA   NA
D_overshoot_area_h   0.1n   NA   NA
D_overshoot_area_l   0.1n   NA   NA
[Voltage Range]   1.1000V   1.0600V   1.1700V
[Pullup Reference]   1.1000V   1.0600V   1.1700V
| Junction Temperature (Ambient temp is 35C typ 95C min -40C max)
[Temperature Range]   50.0   110.0   -40.0
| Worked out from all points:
|   slope of the pulldown table from 0 to 0.165 V, typ, clamps not added: 54.7 ohm
|   slope of the pullup table from 0 to 0.165 V, typ, clamps not added: 17.5 kohm
|   GND clamp passes 1 mA (typ) near -0.45 V on its own axis
|   POWER clamp passes 1 mA (typ) near -0.88 V on its own axis
|   rising waveform, R_fixture 50, V_fixture 0.0: 20-80 % time 35ps typ, 38.6ps min, 31.9ps max; typ from 0.001 V to 0.368 V
|   falling waveform, R_fixture 50, V_fixture 1.1: 20-80 % time 53.8ps typ, 66.1ps min, 43.3ps max; typ from 1.1 V to 0.635 V
|   rising waveform, R_fixture 50, V_fixture 1.1: 20-80 % time 55.5ps typ, 58.5ps min, 51.9ps max; typ from 0.635 V to 1.1 V
|   falling waveform, R_fixture 50, V_fixture 0.0: 20-80 % time 35.1ps typ, 42.1ps min, 29.8ps max; typ from 0.368 V to 0.001 V
[Pulldown]
|   Voltage   I(typ)   I(min)   I(max)
-1.1V     -46.59mA   -40.54mA   -52.4mA
-984.5mV  -42.18mA   -37.47mA   -47.24mA
-760.1mV  -33.08mA   -29.85mA   -36.78mA
-525.8mV  -22.18mA   -19.19mA   -25.77mA
-360.8mV  -12.31mA   -10.36mA   -15.17mA
-255.2mV  -6.824mA   -6.051mA   -8.221mA
-172.7mV  -3.91mA    -3.702mA   -4.273mA
-67.1mV   -1.381mA   -1.359mA   -1.369mA
418mV     6.864mA    6.672mA    7.196mA
850.3mV   10.91mA    9.987mA    12.53mA
1.378V    13.15mA    11.88mA    15.62mA
2.2V      15.34mA    13.95mA    18.15mA
[GND Clamp]
|   Voltage   I(typ)   I(min)   I(max)
-1.1V     -34.75mA   -30.21mA   -42.92mA
-944.9mV  -25.23mA   -21.44mA   -31.56mA
-799.7mV  -16.31mA   -13.32mA   -21.43mA
-723.8mV  -11.94mA   -9.346mA   -16.11mA
-661.1mV  -8.569mA   -6.434mA   -11.86mA
-588.5mV  -5.114mA   -3.68mA    -7.305mA
-519.2mV  -2.567mA   -1.834mA   -3.662mA
-469.7mV  -1.356mA   -986.6uA   -1.788mA
-413.6mV  -565.8uA   -417.4uA   -620.8uA
-354.2mV  -178.1uA   -134.7uA   -160uA
-242mV    -10.05uA   -9.233uA   -5.682uA
2.2V      0A         0A         0A
[Pullup]
|   Voltage   I(typ)   I(min)   I(max)
-1.1V     4.106uA    7.431uA    1.361uA
259.6mV   -61.07uA   -59.34uA   -61.44uA
394.9mV   -631.3uA   -524.1uA   -751.2uA
503.8mV   -2.098mA   -1.888mA   -2.195mA
609.4mV   -4.297mA   -4.297mA   -4.127mA
754.6mV   -7.982mA   -8.738mA   -7.279mA
1.042V    -16.16mA   -18.8mA    -14.47mA
1.448V    -28.55mA   -33.09mA   -25.83mA
1.659V    -34.81mA   -39.41mA   -32.94mA
1.887V    -41.73mA   -44.49mA   -41mA
2.127V    -49.7mA    -50.05mA   -50.55mA
2.2V      -52.05mA   -51.41mA   -53.39mA
[POWER Clamp]
|   Voltage   I(typ)   I(min)   I(max)
-1.1V     3.033mA    3.633mA    2.184mA
-1.044V   2.381mA    2.967mA    1.653mA
-968mV    1.637mA    2.139mA    1.094mA
-905.3mV  1.155mA    1.553mA    732.4uA
-849.2mV  799.2uA    1.125mA    535.4uA
-770mV    407.6uA    647.3uA    378uA
-707.3mV  225.4uA    345.4uA    267.6uA
-651.2mV  138.6uA    162.3uA    181.2uA
-591.8mV  77.93uA    64.79uA    105.5uA
-496.1mV  20.1uA     12.34uA    25.71uA
-390.5mV  2.047uA    1.389uA    1.764uA
2.2V      0A         0A         0A
[Ramp]
|   typ   min   max
| 20% - 80%
dV/dt_r   220.58m/34.98p   212.91m/38.64p   234.66m/31.86p
dV/dt_f   278.79m/53.87p   259.07m/66.15p   312.07m/43.34p
| 25% - 75%
|dV/dt_r   183.82m/27.84p   177.42m/30.78p   195.55m/25.31p
|dV/dt_f   232.33m/42.89p   215.89m/52.71p   260.06m/34.44p
R_load = 50
[Rising Waveform]
R_fixture = 50
V_fixture = 0.0
|   Time   V(typ)   V(min)   V(max)
0s        727.4uV    593.5uV    534.4uV
58ps      505.6uV    12.21uV    7.106mV
67ps      2.893mV    -473.1uV   42.34mV
77ps      12.29mV    918.3uV    123.7mV
87ps      56.86mV    4.918mV    212.8mV
102ps     170.9mV    29.17mV    305.4mV
129ps     309.2mV    192.9mV    372.7mV
152ps     350.9mV    293.6mV    387.1mV
182ps     365.4mV    341.5mV    391.1mV
351ps     368.4mV    355.4mV    391.6mV
[Falling Waveform]
R_fixture   = 50
V_fixture   = 1.1
V_fixture_min = 1.06
V_fixture_max = 1.17
|   Time   V(typ)   V(min)   V(max)
0s        1.1V       1.06V      1.17V
74ps      1.099V     1.061V     1.158V
95ps      1.082V     1.055V     989.8mV
118ps     946.9mV    1.042V     811.9mV
135ps     841.8mV    981.1mV    736.6mV
154ps     756.5mV    886.2mV    691.9mV
188ps     678.2mV    751.8mV    661.3mV
224ps     649.2mV    678.1mV    652.7mV
272ps     638.3mV    641.3mV    650.3mV
351ps     635.3mV    628.2mV    649.9mV
[Rising Waveform]
R_fixture   = 50
V_fixture   = 1.1
V_fixture_min = 1.06
V_fixture_max = 1.17
|   Time   V(typ)   V(min)   V(max)
0s        635mV      626.1mV    649.8mV
55ps      631.3mV    622.3mV    659.1mV
64ps      639.5mV    619.3mV    700.4mV
77ps      694mV      631.4mV    823.7mV
88ps      779.5mV    674.8mV    913mV
105ps     891.5mV    787.2mV    1.007V
123ps     966.8mV    884.1mV    1.068V
146ps     1.024V     957.8mV    1.115V
216ps     1.086V     1.04V      1.161V
351ps     1.099V     1.059V     1.17V
[Falling Waveform]
R_fixture = 50
V_fixture = 0.0
|   Time   V(typ)   V(min)   V(max)
0s        368.5mV    355.6mV    391.7mV
58ps      374.3mV    358.9mV    391.9mV
74ps      367.4mV    370.2mV    315.1mV
87ps      307.5mV    362.6mV    178.3mV
97ps      232mV      327.4mV    109.9mV
112ps     125.4mV    240.7mV    53.84mV
129ps     59.65mV    143.3mV    24.4mV
152ps     22.03mV    58.01mV    8.687mV
183ps     6.28mV     16.71mV    2.471mV
351ps     779.8uV    697.8uV    553.4uV
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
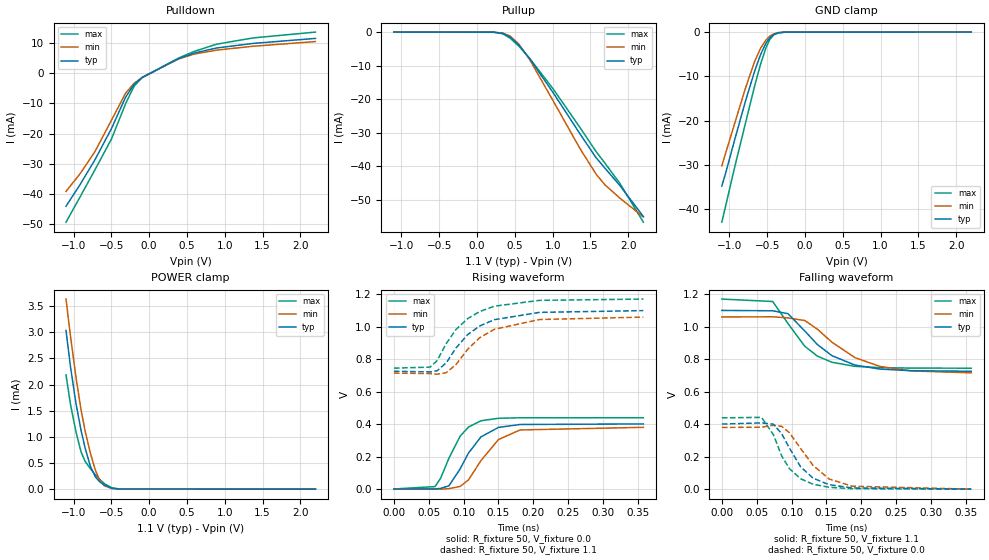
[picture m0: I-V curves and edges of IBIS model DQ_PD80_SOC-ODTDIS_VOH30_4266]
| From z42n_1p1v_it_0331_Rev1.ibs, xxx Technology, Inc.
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| DQ_PD80_SOC-ODTDIS_VOH30_4266
| (80 Ohm Pulldown, SOC ODT disabled setting, VOH=VDDQ/3.0 cal. point, 3200-4266Mbps)
[Model]   DQ_PD80_SOC-ODTDIS_VOH30_4266
Model_type   I/O
Vinl = 123.333mV
Vinh = 243.333mV
Vmeas = 183.333mV
Vref = 0.0mV
Cref = 0.0pF
|   typ   min   max
|C_comp   0.834pF   0.784pF   0.884pF
C_comp_pullup   0.4170pF   0.3920pF   0.4420pF
C_comp_pulldown   0.4170pF   0.3920pF   0.4420pF
| Note: C_comp changes when the ODT circuit is enabled.
[Model Spec]
| Input threshold voltage corners
Vinl   0.1233V   0.1167V   0.1350V
Vinh   0.2433V   0.2367V   0.2550V
| Measurement voltage corners
Vmeas   0.1833V   0.1767V   0.1950V
| Timing spec test load voltage corners
Vref   0.0000V   0.0000V   0.0000V
| Dynamic Overshoot Parameters from LPDDR4 Specification
D_overshoot_ampl_h   0.30   NA   NA
D_overshoot_ampl_l   0.30   NA   NA
D_overshoot_area_h   0.1n   NA   NA
D_overshoot_area_l   0.1n   NA   NA
[Voltage Range]   1.1000V   1.0600V   1.1700V
[Pullup Reference]   1.1000V   1.0600V   1.1700V
| Junction Temperature (Ambient temp is 35C typ 95C min -40C max)
[Temperature Range]   50.0   110.0   -40.0
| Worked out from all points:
|   slope of the pulldown table from 0 to 0.165 V, typ, clamps not added: 73.9 ohm
|   slope of the pullup table from 0 to 0.165 V, typ, clamps not added: 13 kohm
|   GND clamp passes 1 mA (typ) near -0.45 V on its own axis
|   POWER clamp passes 1 mA (typ) near -0.88 V on its own axis
|   rising waveform, R_fixture 50, V_fixture 0.0: 20-80 % time 35.2ps typ, 39.3ps min, 30.4ps max; typ from 0.001 V to 0.401 V
|   falling waveform, R_fixture 50, V_fixture 1.1: 20-80 % time 58.3ps typ, 68.9ps min, 47.4ps max; typ from 1.1 V to 0.726 V
|   rising waveform, R_fixture 50, V_fixture 1.1: 20-80 % time 53.9ps typ, 55.4ps min, 51.8ps max; typ from 0.726 V to 1.1 V
|   falling waveform, R_fixture 50, V_fixture 0.0: 20-80 % time 38ps typ, 44.2ps min, 33.1ps max; typ from 0.401 V to 0.001 V
[Pulldown]
|   Voltage   I(typ)   I(min)   I(max)
-1.1V     -44.04mA   -39.15mA   -49.32mA
-918.5mV  -37.06mA   -33.44mA   -41.18mA
-717.2mV  -28.69mA   -25.98mA   -32mA
-499.4mV  -18.39mA   -15.62mA   -21.85mA
-311.3mV  -7.943mA   -6.615mA   -10.1mA
-199.1mV  -3.704mA   -3.385mA   -4.326mA
-93.5mV   -1.474mA   -1.439mA   -1.485mA
388.3mV   4.785mA    4.676mA    4.965mA
596.2mV   6.626mA    6.292mA    7.181mA
889.9mV   8.305mA    7.596mA    9.551mA
1.375V    9.822mA    8.882mA    11.64mA
2.2V      11.48mA    10.44mA    13.57mA
[GND Clamp]
|   Voltage   I(typ)   I(min)   I(max)
-1.1V     -34.74mA   -30.21mA   -42.91mA
-1.05V    -31.86mA   -27.33mA   -39.27mA
-938.3mV  -24.81mA   -21.07mA   -31.08mA
-786.5mV  -15.53mA   -12.6mA    -20.49mA
-667.7mV  -8.907mA   -6.722mA   -12.29mA
-591.8mV  -5.255mA   -3.789mA   -7.492mA
-519.2mV  -2.564mA   -1.833mA   -3.66mA
-466.4mV  -1.294mA   -942.4uA   -1.691mA
-413.6mV  -563.9uA   -416.3uA   -620.9uA
-350.9mV  -165.7uA   -126.1uA   -147.4uA
-261.8mV  -17.65uA   -15.5uA    -11.07uA
2.2V      0A         0A         0A
[Pullup]
|   Voltage   I(typ)   I(min)   I(max)
-1.1V     6.275uA    9.671uA    2.829uA
226.6mV   -42.09uA   -42.88uA   -42.77uA
338.8mV   -360.6uA   -299.8uA   -496.1uA
434.5mV   -1.386mA   -1.132mA   -1.75mA
550mV     -3.794mA   -3.486mA   -4.131mA
695.2mV   -7.909mA   -8.164mA   -7.815mA
1.009V    -18.16mA   -20.62mA   -17.03mA
1.365V    -30.49mA   -34.9mA    -28.6mA
1.576V    -37.53mA   -42.43mA   -35.7mA
1.688V    -40.51mA   -45.51mA   -39.01mA
1.887V    -45.73mA   -49.52mA   -45.08mA
2.2V      -55.05mA   -55.17mA   -56.74mA
[POWER Clamp]
|   Voltage   I(typ)   I(min)   I(max)
-1.1V     3.033mA    3.633mA    2.184mA
-1.041V   2.345mA    2.929mA    1.625mA
-968mV    1.637mA    2.139mA    1.094mA
-902mV    1.132mA    1.525mA    716.8uA
-845.9mV  780uA      1.103mA    527.5uA
-776.6mV  434.2uA    683.3uA    390.2uA
-710.6mV  232.2uA    359uA      273.1uA
-654.5mV  142.7uA    170.5uA    185.9uA
-591.8mV  77.91uA    64.8uA     105.5uA
-492.8mV  18.87uA    11.58uA    24.07uA
-383.9mV  1.736uA    1.207uA    1.465uA
2.2V      0A         0A         0A
[Ramp]
|   typ   min   max
| 20% - 80%
dV/dt_r   240.17m/35.18p   227.73m/39.33p   263.25m/30.37p
dV/dt_f   224.44m/58.23p   206.40m/68.94p   255.17m/47.47p
| 25% - 75%
|dV/dt_r   200.15m/28.01p   189.78m/31.30p   219.38m/24.16p
|dV/dt_f   187.04m/46.37p   172.00m/54.84p   212.64m/37.72p
R_load = 50
[Rising Waveform]
R_fixture = 50
V_fixture = 0.0
|   Time   V(typ)   V(min)   V(max)
0s        806.6uV    708.8uV    583.1uV
59ps      732.4uV    -243.3uV   15.32mV
67ps      4.234mV    -490.3uV   66.67mV
79ps      20.64mV    2.823mV    190.8mV
95ps      124.2mV    16mV       325.6mV
107ps     221.6mV    56.78mV    381.8mV
125ps     321.6mV    175.6mV    420.8mV
150ps     379.8mV    305mV      436.1mV
181ps     397.7mV    364.1mV    439.1mV
358ps     401.1mV    380.3mV    439.3mV
[Falling Waveform]
R_fixture   = 50
V_fixture   = 1.1
V_fixture_min = 1.06
V_fixture_max = 1.17
|   Time   V(typ)   V(min)   V(max)
0s        1.1V       1.06V      1.17V
73ps      1.098V     1.061V     1.155V
95ps      1.08V      1.054V     1.019V
119ps     973.8mV    1.038V     879.9mV
137ps     890.9mV    985.2mV    819.3mV
158ps     821.8mV    905mV      781.1mV
191ps     764mV      809.8mV    756.3mV
227ps     739.2mV    755.6mV    748mV
272ps     729.3mV    728.1mV    745.4mV
358ps     725.9mV    716mV      744.7mV
[Rising Waveform]
R_fixture   = 50
V_fixture   = 1.1
V_fixture_min = 1.06
V_fixture_max = 1.17
|   Time   V(typ)   V(min)   V(max)
0s        725.5mV    714.2mV    744.7mV
52ps      721.4mV    711.1mV    750.9mV
62ps      728.5mV    707.4mV    791.3mV
75ps      776.9mV    716.5mV    895.2mV
89ps      868.3mV    766.3mV    982.5mV
106ps     951.7mV    861.5mV    1.05V
123ps     1.004V     931.9mV    1.093V
144ps     1.043V     983.7mV    1.126V
209ps     1.088V     1.044V     1.162V
358ps     1.099V     1.059V     1.17V
[Falling Waveform]
R_fixture = 50
V_fixture = 0.0
|   Time   V(typ)   V(min)   V(max)
0s        401.2mV    380.4mV    439.4mV
57ps      408.1mV    381.8mV    442.2mV
74ps      400.8mV    393.6mV    335.7mV
86ps      340.9mV    386.9mV    204.3mV
97ps      253.5mV    348.1mV    126.9mV
113ps     138.6mV    251.5mV    64.66mV
131ps     68.22mV    146.4mV    30.69mV
154ps     28.13mV    63.17mV    12.16mV
187ps     8.459mV    18.8mV     3.552mV
358ps     875.9uV    831.1uV    607uV
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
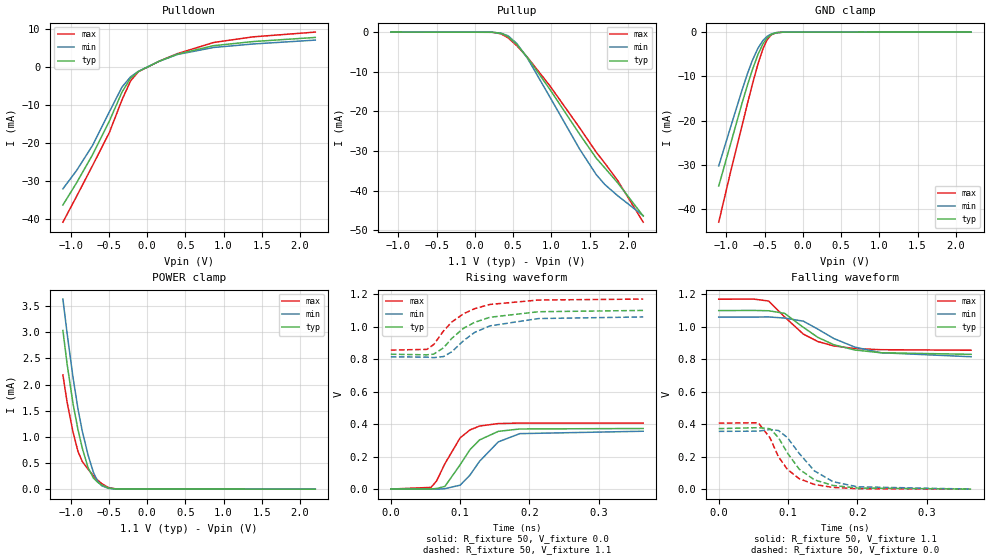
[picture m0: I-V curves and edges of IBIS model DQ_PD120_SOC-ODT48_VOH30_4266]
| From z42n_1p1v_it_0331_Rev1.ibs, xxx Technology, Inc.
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| DQ_PD120_SOC-ODT48_VOH30_4266
| (120 Ohm Pulldown, 48 Ohm System ODT Setting, VOH=VDDQ/3.0, 3200-4266Mbps)
[Model]   DQ_PD120_SOC-ODT48_VOH30_4266
Model_type   I/O
Vinl = 123.333mV
Vinh = 243.333mV
Vmeas = 183.333mV
Vref = 0.0mV
Cref = 0.0pF
Rref = 48.000Ohm
|   typ   min   max
|C_comp   0.834pF   0.784pF   0.884pF
C_comp_pullup   0.4170pF   0.3920pF   0.4420pF
C_comp_pulldown   0.4170pF   0.3920pF   0.4420pF
| Note: C_comp changes when the ODT circuit is enabled.
[Model Spec]
| Input threshold voltage corners
Vinl   0.1233V   0.1167V   0.1350V
Vinh   0.2433V   0.2367V   0.2550V
| Measurement voltage corners
Vmeas   0.1833V   0.1767V   0.1950V
| Timing spec test load voltage corners
Vref   0.0000V   0.0000V   0.0000V
| Dynamic Overshoot Parameters from LPDDR4 Specification
D_overshoot_ampl_h   0.30   NA   NA
D_overshoot_ampl_l   0.30   NA   NA
D_overshoot_area_h   0.1n   NA   NA
D_overshoot_area_l   0.1n   NA   NA
[Voltage Range]   1.1000V   1.0600V   1.1700V
[Pullup Reference]   1.1000V   1.0600V   1.1700V
| Junction Temperature (Ambient temp is 35C typ 95C min -40C max)
[Temperature Range]   50.0   110.0   -40.0
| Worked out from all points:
|   slope of the pulldown table from 0 to 0.165 V, typ, clamps not added: 109 ohm
|   slope of the pullup table from 0 to 0.165 V, typ, clamps not added: 15.6 kohm
|   GND clamp passes 1 mA (typ) near -0.45 V on its own axis
|   POWER clamp passes 1 mA (typ) near -0.88 V on its own axis
|   rising waveform, R_fixture 50, V_fixture 0.0: 20-80 % time 36.8ps typ, 41.5ps min, 32.3ps max; typ from 0.001 V to 0.373 V
|   falling waveform, R_fixture 50, V_fixture 1.1: 20-80 % time 61.6ps typ, 71.6ps min, 52.2ps max; typ from 1.1 V to 0.831 V
|   rising waveform, R_fixture 50, V_fixture 1.1: 20-80 % time 53.9ps typ, 54.7ps min, 51.9ps max; typ from 0.83 V to 1.1 V
|   falling waveform, R_fixture 50, V_fixture 0.0: 20-80 % time 41.3ps typ, 46.6ps min, 36.8ps max; typ from 0.373 V to 0.001 V
[Pulldown]
|   Voltage   I(typ)   I(min)   I(max)
-1.1V     -36.22mA   -31.99mA   -40.73mA
-921.8mV  -30.44mA   -27.21mA   -33.99mA
-710.6mV  -23mA      -20.56mA   -25.83mA
-492.8mV  -14.27mA   -11.85mA   -17.25mA
-327.8mV  -6.656mA   -5.348mA   -8.702mA
-215.6mV  -3.023mA   -2.657mA   -3.737mA
-113.3mV  -1.268mA   -1.219mA   -1.315mA
150.7mV   1.369mA    1.358mA    1.373mA
394.9mV   3.273mA    3.191mA    3.412mA
870.1mV   5.51mA     5.038mA    6.342mA
1.385V    6.584mA    5.95mA     7.817mA
2.2V      7.669mA    6.972mA    9.07mA
[GND Clamp]
|   Voltage   I(typ)   I(min)   I(max)
-1.1V     -34.74mA   -30.2mA    -42.91mA
-948.2mV  -25.43mA   -21.63mA   -31.79mA
-793.1mV  -15.92mA   -12.96mA   -20.95mA
-723.8mV  -11.93mA   -9.348mA   -16.1mA
-661.1mV  -8.566mA   -6.435mA   -11.85mA
-588.5mV  -5.113mA   -3.681mA   -7.299mA
-522.5mV  -2.665mA   -1.902mA   -3.81mA
-469.7mV  -1.356mA   -987.9uA   -1.786mA
-413.6mV  -564.6uA   -417.2uA   -621.3uA
-347.6mV  -154.4uA   -117.4uA   -135.5uA
-251.9mV  -13.34uA   -11.91uA   -7.993uA
2.2V      0A         0A         0A
[Pullup]
|   Voltage   I(typ)   I(min)   I(max)
-1.1V     5.229uA    8.059uA    2.358uA
226.6mV   -35.02uA   -35.84uA   -35.68uA
342.1mV   -317.8uA   -261.9uA   -438.3uA
434.5mV   -1.158mA   -947.7uA   -1.465mA
550mV     -3.184mA   -2.927mA   -3.464mA
688.6mV   -6.477mA   -6.673mA   -6.409mA
979mV     -14.43mA   -16.36mA   -13.53mA
1.368V    -25.76mA   -29.52mA   -24.14mA
1.586V    -31.83mA   -35.98mA   -30.31mA
1.698V    -34.29mA   -38.48mA   -33.08mA
1.867V    -38.07mA   -41.32mA   -37.5mA
2.2V      -46.44mA   -46.36mA   -47.99mA
[POWER Clamp]
|   Voltage   I(typ)   I(min)   I(max)
-1.1V     3.033mA    3.633mA    2.184mA
-1.044V   2.381mA    2.967mA    1.653mA
-968mV    1.637mA    2.139mA    1.094mA
-902mV    1.132mA    1.527mA    717.1uA
-845.9mV  780uA      1.104mA    527.5uA
-770mV    407.7uA    647.5uA    378uA
-700.7mV  212.6uA    319uA      256.7uA
-647.9mV  134.6uA    154.5uA    176.5uA
-591.8mV  77.95uA    64.8uA     105.5uA
-502.7mV  22.57uA    14.05uA    29.25uA
-397.1mV  2.375uA    1.586uA    2.116uA
2.2V      0A         0A         0A
[Ramp]
|   typ   min   max
| 20% - 80%
dV/dt_r   223.52m/36.83p   213.48m/41.51p   243.82m/32.25p
dV/dt_f   161.57m/61.75p   146.48m/71.60p   188.39m/52.13p
| 25% - 75%
|dV/dt_r   186.27m/29.38p   177.90m/33.06p   203.18m/25.65p
|dV/dt_f   134.64m/49.11p   122.07m/56.91p   156.99m/41.38p
R_load = 50
[Rising Waveform]
R_fixture = 50
V_fixture = 0.0
|   Time   V(typ)   V(min)   V(max)
0s        783.6uV    693uV      564.3uV
58ps      912.8uV    -30.5uV    10.97mV
66ps      4.027mV    -97.8uV    50.33mV
78ps      17.04mV    2.839mV    156.8mV
100ps     150.1mV    24.56mV    315.8mV
114ps     242.2mV    85.51mV    364.3mV
128ps     303.1mV    171.5mV    388.4mV
155ps     355.7mV    291mV      403.7mV
186ps     370.4mV    341.7mV    406.6mV
364ps     373.3mV    356.5mV    406.9mV
[Falling Waveform]
R_fixture   = 50
V_fixture   = 1.1
V_fixture_min = 1.06
V_fixture_max = 1.17
|   Time   V(typ)   V(min)   V(max)
0s        1.1V       1.06V      1.17V
50ps      1.101V     1.06V      1.171V
72ps      1.099V     1.061V     1.159V
95ps      1.083V     1.054V     1.061V
122ps     997.1mV    1.035V     955.4mV
143ps     935mV      985.7mV    909.4mV
166ps     889.8mV    928.1mV    882.4mV
196ps     857.6mV    875.5mV    866.4mV
234ps     840.4mV    840.6mV    859.2mV
364ps     830.7mV    815.9mV    856mV
[Rising Waveform]
R_fixture   = 50
V_fixture   = 1.1
V_fixture_min = 1.06
V_fixture_max = 1.17
|   Time   V(typ)   V(min)   V(max)
0s        830.4mV    814.6mV    855.9mV
52ps      826.8mV    812.6mV    860.3mV
62ps      831.3mV    809.6mV    890.6mV
76ps      870mV      816.1mV    973.6mV
88ps      928.2mV    845.6mV    1.029V
105ps     990.9mV    914.6mV    1.08V
121ps     1.027V     965mV      1.111V
143ps     1.058V     1.005V     1.137V
213ps     1.092V     1.05V      1.164V
364ps     1.1V       1.06V      1.17V
[Falling Waveform]
R_fixture = 50
V_fixture = 0.0
|   Time   V(typ)   V(min)   V(max)
0s        373.4mV    356.6mV    407mV
57ps      379.2mV    357.7mV    409.3mV
74ps      372.6mV    367.9mV    316.2mV
86ps      318.8mV    362.2mV    201mV
99ps      224mV      318.1mV    122.4mV
116ps     123.9mV    221.1mV    65.35mV
138ps     58mV       113mV      29.41mV
165ps     23.36mV    46.43mV    11.33mV
200ps     7.697mV    15.2mV     3.621mV
364ps     886.2uV    864.9uV    597.1uV
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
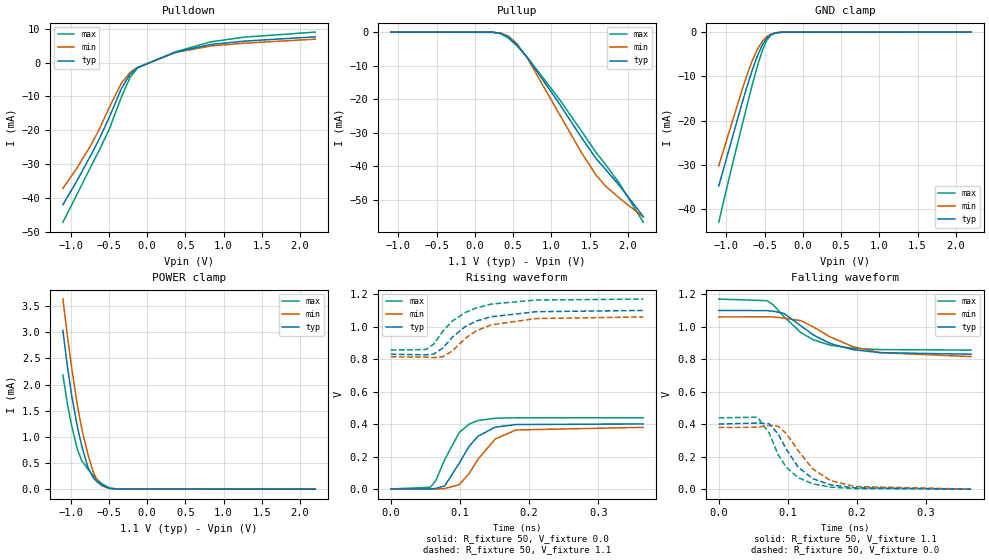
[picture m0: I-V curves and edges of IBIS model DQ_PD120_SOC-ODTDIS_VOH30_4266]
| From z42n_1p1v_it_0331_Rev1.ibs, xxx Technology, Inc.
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| DQ_PD120_SOC-ODTDIS_VOH30_4266
| (120 Ohm Pulldown, SOC ODT disabled setting, VOH=VDDQ/3.0 cal. point, 3200-4266Mbps)
[Model]   DQ_PD120_SOC-ODTDIS_VOH30_4266
Model_type   I/O
Vinl = 123.333mV
Vinh = 243.333mV
Vmeas = 183.333mV
Vref = 0.0mV
Cref = 0.0pF
|   typ   min   max
|C_comp   0.834pF   0.784pF   0.884pF
C_comp_pullup   0.4170pF   0.3920pF   0.4420pF
C_comp_pulldown   0.4170pF   0.3920pF   0.4420pF
| Note: C_comp changes when the ODT circuit is enabled.
[Model Spec]
| Input threshold voltage corners
Vinl   0.1233V   0.1167V   0.1350V
Vinh   0.2433V   0.2367V   0.2550V
| Measurement voltage corners
Vmeas   0.1833V   0.1767V   0.1950V
| Timing spec test load voltage corners
Vref   0.0000V   0.0000V   0.0000V
| Dynamic Overshoot Parameters from LPDDR4 Specification
D_overshoot_ampl_h   0.30   NA   NA
D_overshoot_ampl_l   0.30   NA   NA
D_overshoot_area_h   0.1n   NA   NA
D_overshoot_area_l   0.1n   NA   NA
[Voltage Range]   1.1000V   1.0600V   1.1700V
[Pullup Reference]   1.1000V   1.0600V   1.1700V
| Junction Temperature (Ambient temp is 35C typ 95C min -40C max)
[Temperature Range]   50.0   110.0   -40.0
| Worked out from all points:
|   slope of the pulldown table from 0 to 0.165 V, typ, clamps not added: 109 ohm
|   slope of the pullup table from 0 to 0.165 V, typ, clamps not added: 13.1 kohm
|   GND clamp passes 1 mA (typ) near -0.45 V on its own axis
|   POWER clamp passes 1 mA (typ) near -0.88 V on its own axis
|   rising waveform, R_fixture 50, V_fixture 0.0: 20-80 % time 35.4ps typ, 39.6ps min, 30.5ps max; typ from 0.001 V to 0.401 V
|   falling waveform, R_fixture 50, V_fixture 1.1: 20-80 % time 62.2ps typ, 72.3ps min, 52.5ps max; typ from 1.1 V to 0.831 V
|   rising waveform, R_fixture 50, V_fixture 1.1: 20-80 % time 52.9ps typ, 52.7ps min, 51.5ps max; typ from 0.83 V to 1.1 V
|   falling waveform, R_fixture 50, V_fixture 0.0: 20-80 % time 41.2ps typ, 46.2ps min, 36.8ps max; typ from 0.401 V to 0.001 V
[Pulldown]
|   Voltage   I(typ)   I(min)   I(max)
-1.1V     -42.06mA   -37.2mA    -47.23mA
-918.5mV  -35.07mA   -31.29mA   -39.13mA
-727.1mV  -27.09mA   -24.13mA   -30.44mA
-621.5mV  -22.44mA   -19.55mA   -25.78mA
-496.1mV  -16.29mA   -13.39mA   -19.82mA
-337.7mV  -7.793mA   -6.12mA    -10.34mA
-222.2mV  -3.385mA   -2.894mA   -4.329mA
-123.2mV  -1.441mA   -1.365mA   -1.532mA
375.1mV   3.137mA    3.064mA    3.257mA
837.1mV   5.412mA    4.961mA    6.196mA
1.269V    6.388mA    5.775mA    7.572mA
2.2V      7.669mA    6.972mA    9.07mA
[GND Clamp]
|   Voltage   I(typ)   I(min)   I(max)
-1.1V     -34.74mA   -30.21mA   -42.91mA
-941.6mV  -25.02mA   -21.26mA   -31.32mA
-793.1mV  -15.92mA   -12.96mA   -20.95mA
-720.5mV  -11.75mA   -9.185mA   -15.87mA
-661.1mV  -8.566mA   -6.435mA   -11.85mA
-591.8mV  -5.255mA   -3.789mA   -7.492mA
-525.8mV  -2.766mA   -1.973mA   -3.963mA
-469.7mV  -1.356mA   -987.8uA   -1.789mA
-416.9mV  -598.1uA   -441.5uA   -664.9uA
-357.5mV  -191.5uA   -145.1uA   -174uA
-258.5mV  -16.15uA   -14.3uA    -9.874uA
2.2V      0A         0A         0A
[Pullup]
|   Voltage   I(typ)   I(min)   I(max)
-1.1V     6.275uA    9.671uA    2.829uA
233.2mV   -48.27uA   -48.89uA   -50.75uA
335.5mV   -340.5uA   -283.9uA   -468.7uA
437.8mV   -1.437mA   -1.179mA   -1.807mA
550mV     -3.797mA   -3.485mA   -4.131mA
685.3mV   -7.607mA   -7.806mA   -7.548mA
1.098V    -21.2mA    -24.25mA   -19.85mA
1.398V    -31.64mA   -36.17mA   -29.71mA
1.586V    -37.82mA   -42.74mA   -36.02mA
1.705V    -40.92mA   -45.9mA    -39.46mA
1.89V     -45.83mA   -49.59mA   -45.19mA
2.2V      -55.05mA   -55.17mA   -56.74mA
[POWER Clamp]
|   Voltage   I(typ)   I(min)   I(max)
-1.1V     3.033mA    3.633mA    2.184mA
-1.041V   2.345mA    2.929mA    1.625mA
-984.5mV  1.783mA    2.31mA     1.205mA
-908.6mV  1.178mA    1.582mA    747.5uA
-852.5mV  818.2uA    1.148mA    543.7uA
-773.3mV  420.7uA    665.2uA    384.1uA
-707.3mV  225.4uA    345.4uA    267.6uA
-651.2mV  138.6uA    162.4uA    181.2uA
-591.8mV  77.93uA    64.8uA     105.5uA
-489.5mV  17.81uA    10.83uA    22.49uA
-380.6mV  1.605uA    1.138uA    1.345uA
2.2V      0A         0A         0A
[Ramp]
|   typ   min   max
| 20% - 80%
dV/dt_r   240.10m/35.42p   227.66m/39.65p   263.20m/30.51p
dV/dt_f   161.58m/62.18p   146.47m/72.38p   188.39m/52.38p
| 25% - 75%
|dV/dt_r   200.08m/28.19p   189.72m/31.54p   219.33m/24.27p
|dV/dt_f   134.65m/49.40p   122.06m/57.41p   157.00m/41.61p
R_load = 50
[Rising Waveform]
R_fixture = 50
V_fixture = 0.0
|   Time   V(typ)   V(min)   V(max)
0s        938.2uV    831.4uV    675.3uV
57ps      799.7uV    -21.5uV    11.49mV
65ps      4.262mV    -258.5uV   52.05mV
78ps      20.14mV    3.485mV    182.7mV
99ps      159.9mV    27.37mV    348.8mV
113ps     262.8mV    94.72mV    399.6mV
126ps     325.8mV    183.6mV    422.1mV
151ps     381mV      308.6mV    436.4mV
181ps     397.7mV    364.1mV    439.1mV
365ps     401.1mV    380.3mV    439.3mV
[Falling Waveform]
R_fixture   = 50
V_fixture   = 1.1
V_fixture_min = 1.06
V_fixture_max = 1.17
|   Time   V(typ)   V(min)   V(max)
0s        1.1V       1.06V      1.17V
70ps      1.099V     1.061V     1.16V
79ps      1.095V     1.06V      1.134V
94ps      1.082V     1.053V     1.063V
119ps     1.005V     1.037V     963mV
137ps     948.9mV    998.2mV    919.2mV
161ps     896.8mV    937.3mV    886.5mV
194ps     858.8mV    877.1mV    867mV
233ps     840.4mV    840.7mV    859.3mV
365ps     830.7mV    815.9mV    856mV
[Rising Waveform]
R_fixture   = 50
V_fixture   = 1.1
V_fixture_min = 1.06
V_fixture_max = 1.17
|   Time   V(typ)   V(min)   V(max)
0s        830.4mV    814.6mV    855.9mV
51ps      826.8mV    812.9mV    859.5mV
62ps      831.6mV    809.3mV    893mV
75ps      867.6mV    815mV      970.8mV
89ps      935.8mV    851mV      1.035V
108ps     1.002V     929.5mV    1.088V
124ps     1.035V     975.5mV    1.116V
145ps     1.061V     1.011V     1.139V
210ps     1.092V     1.05V      1.164V
365ps     1.1V       1.06V      1.17V
[Falling Waveform]
R_fixture = 50
V_fixture = 0.0
|   Time   V(typ)   V(min)   V(max)
0s        401.2mV    380.4mV    439.4mV
56ps      407.4mV    381.3mV    443.4mV
73ps      402.8mV    393.2mV    345.5mV
86ps      339.5mV    386.8mV    212.1mV
98ps      244.8mV    342mV      134mV
115ps     135.1mV    236.9mV    71.46mV
136ps     65.19mV    124.9mV    33.32mV
162ps     27.13mV    52.75mV    13.25mV
197ps     8.887mV    17.15mV    4.175mV
365ps     1.029mV    986.3uV    705.5uV
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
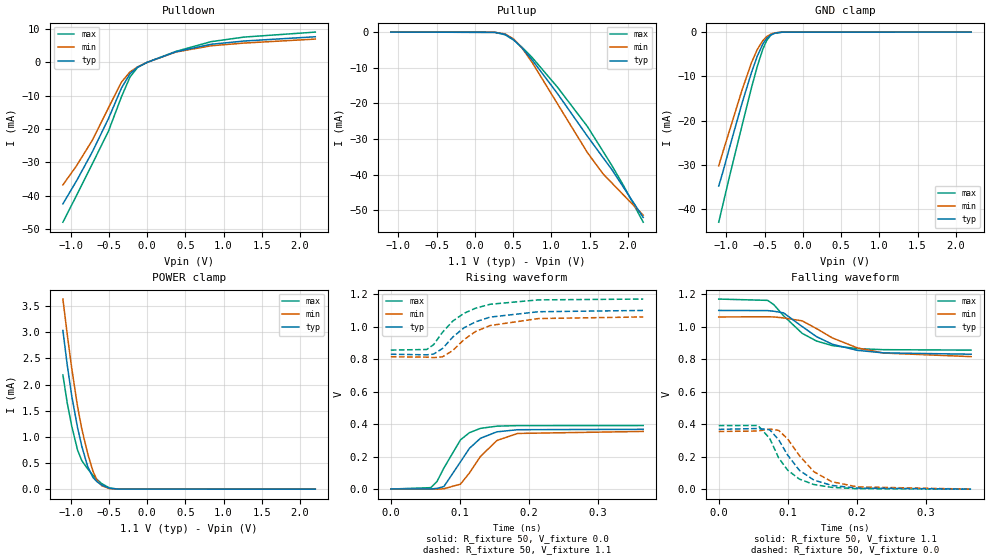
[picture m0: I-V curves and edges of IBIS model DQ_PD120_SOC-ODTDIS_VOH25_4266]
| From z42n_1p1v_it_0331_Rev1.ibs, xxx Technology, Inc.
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| DQ_PD120_SOC-ODTDIS_VOH25_4266
| (120 Ohm Pulldown, SOC ODT disabled setting, VOH=VDDQ/2.5 cal. point, 3200-4266Mbps)
[Model]   DQ_PD120_SOC-ODTDIS_VOH25_4266
Model_type   I/O
Vinl = 160.000mV
Vinh = 280.000mV
Vmeas = 220.000mV
Vref = 0.0mV
Cref = 0.0pF
|   typ   min   max
|C_comp   0.834pF   0.784pF   0.884pF
C_comp_pullup   0.4170pF   0.3920pF   0.4420pF
C_comp_pulldown   0.4170pF   0.3920pF   0.4420pF
| Note: C_comp changes when the ODT circuit is enabled.
[Model Spec]
| Input threshold voltage corners
Vinl   0.1600V   0.1520V   0.1740V
Vinh   0.2800V   0.2720V   0.2940V
| Measurement voltage corners
Vmeas   0.2200V   0.2120V   0.2340V
| Timing spec test load voltage corners
Vref   0.0000V   0.0000V   0.0000V
| Dynamic Overshoot Parameters from LPDDR4 Specification
D_overshoot_ampl_h   0.30   NA   NA
D_overshoot_ampl_l   0.30   NA   NA
D_overshoot_area_h   0.1n   NA   NA
D_overshoot_area_l   0.1n   NA   NA
[Voltage Range]   1.1000V   1.0600V   1.1700V
[Pullup Reference]   1.1000V   1.0600V   1.1700V
| Junction Temperature (Ambient temp is 35C typ 95C min -40C max)
[Temperature Range]   50.0   110.0   -40.0
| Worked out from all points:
|   slope of the pulldown table from 0 to 0.165 V, typ, clamps not added: 108 ohm
|   slope of the pullup table from 0 to 0.165 V, typ, clamps not added: 17.5 kohm
|   GND clamp passes 1 mA (typ) near -0.45 V on its own axis
|   POWER clamp passes 1 mA (typ) near -0.88 V on its own axis
|   rising waveform, R_fixture 50, V_fixture 0.0: 20-80 % time 35.3ps typ, 39.2ps min, 32.1ps max; typ from 0.001 V to 0.368 V
|   falling waveform, R_fixture 50, V_fixture 1.1: 20-80 % time 62ps typ, 72.3ps min, 51.9ps max; typ from 1.1 V to 0.831 V
|   rising waveform, R_fixture 50, V_fixture 1.1: 20-80 % time 53.9ps typ, 54.9ps min, 51.6ps max; typ from 0.83 V to 1.1 V
|   falling waveform, R_fixture 50, V_fixture 0.0: 20-80 % time 41.6ps typ, 46.3ps min, 36.8ps max; typ from 0.368 V to 0.001 V
[Pulldown]
|   Voltage   I(typ)   I(min)   I(max)
-1.1V     -42.5mA    -36.8mA    -48mA
-921.8mV  -35.59mA   -31.07mA   -39.98mA
-713.9mV  -26.83mA   -23.34mA   -30.43mA
-502.7mV  -16.83mA   -13.59mA   -20.58mA
-334.4mV  -7.726mA   -5.944mA   -10.35mA
-222.2mV  -3.417mA   -2.876mA   -4.404mA
-123.2mV  -1.45mA    -1.361mA   -1.547mA
0V        -29.6uA    -24.6uA    -21.53uA
378.4mV   3.16mA     3.086mA    3.283mA
837.1mV   5.412mA    4.961mA    6.196mA
1.269V    6.388mA    5.775mA    7.572mA
2.2V      7.669mA    6.972mA    9.07mA
[GND Clamp]
|   Voltage   I(typ)   I(min)   I(max)
-1.1V     -34.75mA   -30.2mA    -42.92mA
-1.047V   -31.66mA   -27.14mA   -39.03mA
-941.6mV  -25.02mA   -21.25mA   -31.33mA
-796.4mV  -16.12mA   -13.14mA   -21.2mA
-671mV    -9.083mA   -6.865mA   -12.51mA
-595.1mV  -5.401mA   -3.898mA   -7.694mA
-525.8mV  -2.769mA   -1.975mA   -3.966mA
-473mV    -1.423mA   -1.031mA   -1.887mA
-416.9mV  -599.5uA   -440.4uA   -665.5uA
-360.8mV  -205.9uA   -154.4uA   -188.6uA
-265.1mV  -19.58uA   -16.73uA   -12.32uA
2.2V      0A         0A         0A
[Pullup]
|   Voltage   I(typ)   I(min)   I(max)
-1.1V     4.106uA    7.431uA    1.361uA
262.9mV   -64.81uA   -63.79uA   -66.42uA
394.9mV   -632.2uA   -524.2uA   -750.4uA
507.1mV   -2.159mA   -1.948mA   -2.249mA
612.7mV   -4.374mA   -4.387mA   -4.193mA
748mV     -7.805mA   -8.519mA   -7.126mA
1.078V    -17.24mA   -20.1mA    -15.44mA
1.471V    -29.26mA   -33.86mA   -26.53mA
1.675V    -35.26mA   -39.82mA   -33.5mA
1.788V    -38.54mA   -42.33mA   -37.4mA
1.943V    -43.63mA   -45.77mA   -43.12mA
2.2V      -52.05mA   -51.41mA   -53.39mA
[POWER Clamp]
|   Voltage   I(typ)   I(min)   I(max)
-1.1V     3.033mA    3.633mA    2.184mA
-1.044V   2.381mA    2.967mA    1.653mA
-984.5mV  1.782mA    2.31mA     1.205mA
-908.6mV  1.177mA    1.582mA    748.2uA
-852.5mV  818.2uA    1.149mA    543.6uA
-776.6mV  434.2uA    683.3uA    390.2uA
-707.3mV  225.6uA    345.4uA    267.6uA
-654.5mV  142.7uA    170.4uA    185.9uA
-591.8mV  77.93uA    64.81uA    105.5uA
-489.5mV  17.77uA    10.84uA    22.44uA
-377.3mV  1.505uA    1.061uA    1.223uA
2.2V      0A         0A         0A
[Ramp]
|   typ   min   max
| 20% - 80%
dV/dt_r   220.43m/35.33p   212.79m/39.18p   234.55m/32.12p
dV/dt_f   161.60m/61.86p   146.48m/72.39p   188.40m/51.96p
| 25% - 75%
|dV/dt_r   183.69m/28.11p   177.32m/31.19p   195.46m/25.51p
|dV/dt_f   134.67m/49.10p   122.07m/57.51p   157.00m/41.27p
R_load = 50
[Rising Waveform]
R_fixture = 50
V_fixture = 0.0
|   Time   V(typ)   V(min)   V(max)
0s        972.3uV    804.8uV    709.7uV
58ps      1.078mV    20.99uV    9.264mV
67ps      4.781mV    -49.41uV   47.09mV
77ps      16.25mV    2.537mV    130.4mV
101ps     168mV      31.04mV    303.3mV
114ps     251.1mV    99.41mV    347.6mV
130ps     313.3mV    201.5mV    374.2mV
154ps     353mV      299.8mV    387.8mV
184ps     365.8mV    342.9mV    391.1mV
366ps     368.4mV    355.4mV    391.6mV
[Falling Waveform]
R_fixture   = 50
V_fixture   = 1.1
V_fixture_min = 1.06
V_fixture_max = 1.17
|   Time   V(typ)   V(min)   V(max)
0s        1.1V       1.06V      1.17V
71ps      1.099V     1.061V     1.162V
80ps      1.095V     1.06V      1.135V
94ps      1.085V     1.054V     1.067V
121ps     1.001V     1.036V     959.1mV
142ps     938.2mV    987.8mV    911.5mV
165ps     891.7mV    930.5mV    883.5mV
201ps     854.5mV    869.6mV    865.1mV
239ps     839mV      838mV      858.7mV
366ps     830.7mV    815.9mV    856mV
[Rising Waveform]
R_fixture   = 50
V_fixture   = 1.1
V_fixture_min = 1.06
V_fixture_max = 1.17
|   Time   V(typ)   V(min)   V(max)
0s        830.4mV    814.6mV    855.9mV
52ps      826.8mV    812.6mV    859.7mV
62ps      831.3mV    809.5mV    889mV
75ps      865.6mV    814.7mV    965.9mV
90ps      936.7mV    853.6mV    1.035V
106ps     992.8mV    920.1mV    1.082V
123ps     1.03V      970.6mV    1.114V
144ps     1.059V     1.007V     1.138V
214ps     1.092V     1.05V      1.165V
366ps     1.1V       1.06V      1.17V
[Falling Waveform]
R_fixture = 50
V_fixture = 0.0
|   Time   V(typ)   V(min)   V(max)
0s        368.5mV    355.6mV    391.7mV
57ps      373.8mV    358.4mV    392.5mV
74ps      366.4mV    370.4mV    312.3mV
87ps      304.2mV    362.1mV    192.3mV
100ps     209.8mV    309.3mV    117.2mV
117ps     116.4mV    207mV      62.57mV
138ps     56.5mV     108mV      29.17mV
164ps     23.64mV    46.46mV    11.7mV
201ps     7.431mV    14.69mV    3.582mV
366ps     1.046mV    960uV      738.7uV
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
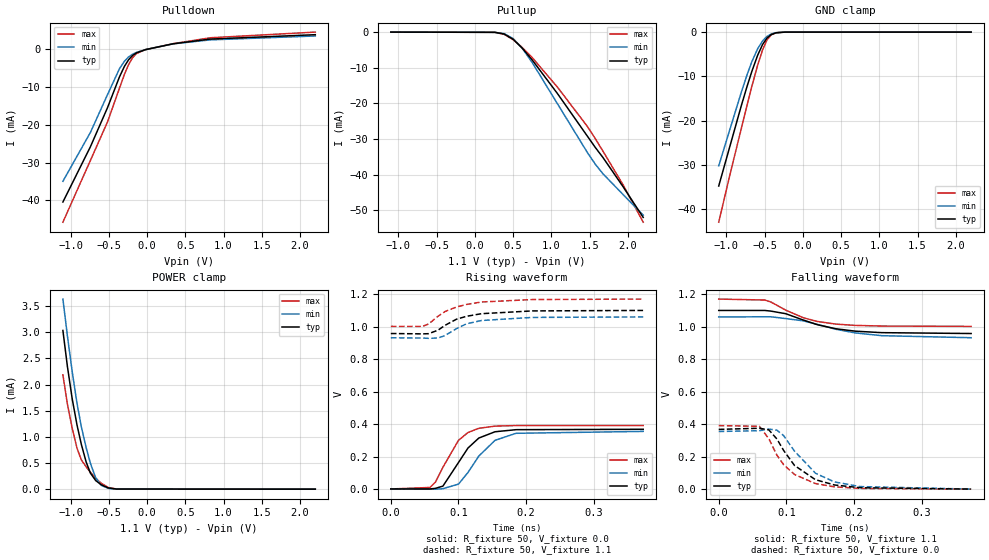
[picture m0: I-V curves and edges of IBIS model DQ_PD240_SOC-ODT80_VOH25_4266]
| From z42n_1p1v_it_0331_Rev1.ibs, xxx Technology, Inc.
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| DQ_PD240_SOC-ODT80_VOH25_4266
| (240 Ohm Pulldown, 80 Ohm System ODT Setting, VOH=VDDQ/2.5, 3200-4266Mbps)
[Model]   DQ_PD240_SOC-ODT80_VOH25_4266
Model_type   I/O
Vinl = 160.000mV
Vinh = 280.000mV
Vmeas = 220.000mV
Vref = 0.0mV
Cref = 0.0pF
Rref = 80.000Ohm
|   typ   min   max
|C_comp   0.834pF   0.784pF   0.884pF
C_comp_pullup   0.4170pF   0.3920pF   0.4420pF
C_comp_pulldown   0.4170pF   0.3920pF   0.4420pF
| Note: C_comp changes when the ODT circuit is enabled.
[Model Spec]
| Input threshold voltage corners
Vinl   0.1600V   0.1520V   0.1740V
Vinh   0.2800V   0.2720V   0.2940V
| Measurement voltage corners
Vmeas   0.2200V   0.2120V   0.2340V
| Timing spec test load voltage corners
Vref   0.0000V   0.0000V   0.0000V
| Dynamic Overshoot Parameters from LPDDR4 Specification
D_overshoot_ampl_h   0.30   NA   NA
D_overshoot_ampl_l   0.30   NA   NA
D_overshoot_area_h   0.1n   NA   NA
D_overshoot_area_l   0.1n   NA   NA
[Voltage Range]   1.1000V   1.0600V   1.1700V
[Pullup Reference]   1.1000V   1.0600V   1.1700V
| Junction Temperature (Ambient temp is 35C typ 95C min -40C max)
[Temperature Range]   50.0   110.0   -40.0
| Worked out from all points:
|   slope of the pulldown table from 0 to 0.165 V, typ, clamps not added: 220 ohm
|   slope of the pullup table from 0 to 0.165 V, typ, clamps not added: 17.5 kohm
|   GND clamp passes 1 mA (typ) near -0.45 V on its own axis
|   POWER clamp passes 1 mA (typ) near -0.88 V on its own axis
|   rising waveform, R_fixture 50, V_fixture 0.0: 20-80 % time 35.6ps typ, 39.5ps min, 32.3ps max; typ from 0.001 V to 0.368 V
|   falling waveform, R_fixture 50, V_fixture 1.1: 20-80 % time 69.6ps typ, 82.3ps min, 58.5ps max; typ from 1.1 V to 0.958 V
|   rising waveform, R_fixture 50, V_fixture 1.1: 20-80 % time 47.9ps typ, 43.1ps min, 49.5ps max; typ from 0.958 V to 1.1 V
|   falling waveform, R_fixture 50, V_fixture 0.0: 20-80 % time 46.8ps typ, 50.3ps min, 42.8ps max; typ from 0.368 V to 0.001 V
[Pulldown]
|   Voltage   I(typ)   I(min)   I(max)
-1.1V     -40.43mA   -34.95mA   -45.76mA
-740.3mV  -25.81mA   -22.03mA   -29.43mA
-515.9mV  -15.44mA   -12mA      -19.21mA
-360.8mV  -7.369mA   -5.194mA   -10.35mA
-294.8mV  -4.529mA   -3.184mA   -6.634mA
-242mV    -2.834mA   -2.081mA   -4.133mA
-189.2mV  -1.684mA   -1.347mA   -2.273mA
-139.7mV  -1.011mA   -875.8uA   -1.191mA
-20.9mV   -139.8uA   -130.7uA   -130.2uA
342.1mV   1.411mA    1.388mA    1.444mA
827.2mV   2.654mA    2.447mA    3mA
2.2V      3.814mA    3.471mA    4.502mA
[GND Clamp]
|   Voltage   I(typ)   I(min)   I(max)
-1.1V     -34.75mA   -30.2mA    -42.92mA
-941.6mV  -25.02mA   -21.25mA   -31.33mA
-803mV    -16.51mA   -13.5mA    -21.66mA
-727.1mV  -12.12mA   -9.51mA    -16.34mA
-667.7mV  -8.911mA   -6.72mA    -12.3mA
-591.8mV  -5.257mA   -3.788mA   -7.499mA
-525.8mV  -2.772mA   -1.974mA   -3.966mA
-469.7mV  -1.359mA   -987.5uA   -1.788mA
-413.6mV  -564.2uA   -416.8uA   -621uA
-350.9mV  -166.7uA   -125.8uA   -147.1uA
-235.4mV  -8.245uA   -7.743uA   -4.444uA
2.2V      0A         0A         0A
[Pullup]
|   Voltage   I(typ)   I(min)   I(max)
-1.1V     4.106uA    7.431uA    1.361uA
259.6mV   -60.46uA   -59.18uA   -61.53uA
381.7mV   -522.7uA   -434.4uA   -628uA
500.5mV   -2.041mA   -1.829mA   -2.142mA
616mV     -4.451mA   -4.476mA   -4.259mA
744.7mV   -7.716mA   -8.41mA    -7.051mA
1.078V    -17.24mA   -20.1mA    -15.44mA
1.471V    -29.26mA   -33.86mA   -26.53mA
1.576V    -32.47mA   -37.17mA   -30.01mA
1.675V    -35.26mA   -39.82mA   -33.5mA
1.936V    -43.4mA    -45.61mA   -42.87mA
2.2V      -52.05mA   -51.41mA   -53.39mA
[POWER Clamp]
|   Voltage   I(typ)   I(min)   I(max)
-1.1V     3.033mA    3.633mA    2.184mA
-1.041V   2.345mA    2.929mA    1.625mA
-977.9mV  1.723mA    2.241mA    1.161mA
-915.2mV  1.224mA    1.639mA    781.3uA
-859.1mV  857.3uA    1.194mA    560.9uA
-796.4mV  521.4uA    794.8uA    427.2uA
-740.3mV  306.2uA    494.3uA    324.2uA
-671mV    164.5uA    215.8uA    210.1uA
-598.4mV  83.64uA    71.96uA    113uA
-502.7mV  22.55uA    14.03uA    29.26uA
-397.1mV  2.377uA    1.592uA    2.116uA
2.2V      0A         0A         0A
[Ramp]
|   typ   min   max
| 20% - 80%
dV/dt_r   220.32m/35.57p   212.68m/39.47p   234.47m/32.27p
dV/dt_f   85.15m/69.44p   76.64m/82.37p   100.79m/58.41p
| 25% - 75%
|dV/dt_r   183.60m/28.35p   177.24m/31.42p   195.39m/25.69p
|dV/dt_f   70.96m/55.18p   63.87m/65.02p   84.00m/46.44p
R_load = 50
[Rising Waveform]
R_fixture = 50
V_fixture = 0.0
|   Time   V(typ)   V(min)   V(max)
0s        1.17mV     974.5uV    852.3uV
58ps      1.029mV    -74.26uV   10.25mV
66ps      4.739mV    -305.3uV   43.29mV
77ps      18.43mV    2.717mV    134.5mV
100ps     163.6mV    30.7mV     300.2mV
114ps     252.8mV    102.4mV    348.3mV
130ps     314.3mV    203.3mV    374.4mV
154ps     353.1mV    300.4mV    387.8mV
185ps     365.9mV    343.6mV    391.2mV
373ps     368.4mV    355.4mV    391.6mV
[Falling Waveform]
R_fixture   = 50
V_fixture   = 1.1
V_fixture_min = 1.06
V_fixture_max = 1.17
|   Time   V(typ)   V(min)   V(max)
0s        1.1V       1.06V      1.17V
68ps      1.1V       1.061V     1.164V
77ps      1.096V     1.061V     1.152V
99ps      1.08V      1.05V      1.102V
125ps     1.041V     1.036V     1.055V
146ps     1.012V     1.014V     1.032V
173ps     987.4mV    984.4mV    1.016V
202ps     972.5mV    961.7mV    1.008V
241ps     963.4mV    944.8mV    1.004V
373ps     958.1mV    932.3mV    1.002V
[Rising Waveform]
R_fixture   = 50
V_fixture   = 1.1
V_fixture_min = 1.06
V_fixture_max = 1.17
|   Time   V(typ)   V(min)   V(max)
0s        957.9mV    931.6mV    1.002V
47ps      955.7mV    930.2mV    1.002V
56ps      956.9mV    928mV      1.017V
70ps      979.1mV    930.7mV    1.065V
80ps      1.008V     945.3mV    1.093V
97ps      1.046V     987.8mV    1.121V
112ps     1.064V     1.018V     1.137V
134ps     1.08V      1.038V     1.152V
209ps     1.097V     1.057V     1.167V
373ps     1.1V       1.06V      1.17V
[Falling Waveform]
R_fixture = 50
V_fixture = 0.0
|   Time   V(typ)   V(min)   V(max)
0s        368.5mV    355.6mV    391.7mV
60ps      375.6mV    360.4mV    387.6mV
74ps      365.8mV    370.5mV    311.7mV
86ps      309.2mV    363.8mV    209.8mV
96ps      238.5mV    329.4mV    151.1mV
112ps     146.5mV    234.8mV    91.17mV
143ps     58.98mV    98.64mV    35.1mV
171ps     26.71mV    45.52mV    15.21mV
209ps     9.666mV    16.79mV    5.283mV
373ps     1.298mV    1.226mV    903.6uV
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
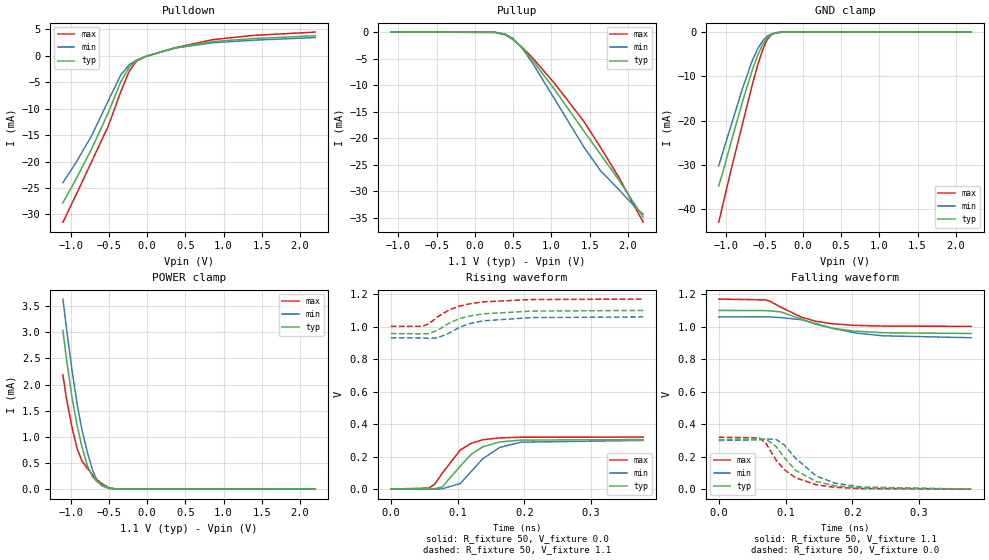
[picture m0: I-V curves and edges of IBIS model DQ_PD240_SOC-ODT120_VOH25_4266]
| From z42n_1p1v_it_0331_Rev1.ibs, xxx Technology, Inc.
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| DQ_PD240_SOC-ODT120_VOH25_4266
| (240 Ohm Pulldown, 120 Ohm System ODT Setting, VOH=VDDQ/2.5, 3200-4266Mbps)
[Model]   DQ_PD240_SOC-ODT120_VOH25_4266
Model_type   I/O
Vinl = 160.000mV
Vinh = 280.000mV
Vmeas = 220.000mV
Vref = 0.0mV
Cref = 0.0pF
Rref = 120.000Ohm
|   typ   min   max
|C_comp   0.834pF   0.784pF   0.884pF
C_comp_pullup   0.4170pF   0.3920pF   0.4420pF
C_comp_pulldown   0.4170pF   0.3920pF   0.4420pF
| Note: C_comp changes when the ODT circuit is enabled.
[Model Spec]
| Input threshold voltage corners
Vinl   0.1600V   0.1520V   0.1740V
Vinh   0.2800V   0.2720V   0.2940V
| Measurement voltage corners
Vmeas   0.2200V   0.2120V   0.2340V
| Timing spec test load voltage corners
Vref   0.0000V   0.0000V   0.0000V
| Dynamic Overshoot Parameters from LPDDR4 Specification
D_overshoot_ampl_h   0.30   NA   NA
D_overshoot_ampl_l   0.30   NA   NA
D_overshoot_area_h   0.1n   NA   NA
D_overshoot_area_l   0.1n   NA   NA
[Voltage Range]   1.1000V   1.0600V   1.1700V
[Pullup Reference]   1.1000V   1.0600V   1.1700V
| Junction Temperature (Ambient temp is 35C typ 95C min -40C max)
[Temperature Range]   50.0   110.0   -40.0
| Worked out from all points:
|   slope of the pulldown table from 0 to 0.165 V, typ, clamps not added: 223 ohm
|   slope of the pullup table from 0 to 0.165 V, typ, clamps not added: 26.3 kohm
|   GND clamp passes 1 mA (typ) near -0.45 V on its own axis
|   POWER clamp passes 1 mA (typ) near -0.88 V on its own axis
|   rising waveform, R_fixture 50, V_fixture 0.0: 20-80 % time 40.6ps typ, 44.3ps min, 36.9ps max; typ from 0.001 V to 0.305 V
|   falling waveform, R_fixture 50, V_fixture 1.1: 20-80 % time 67.7ps typ, 78.6ps min, 57.5ps max; typ from 1.1 V to 0.958 V
|   rising waveform, R_fixture 50, V_fixture 1.1: 20-80 % time 51.9ps typ, 50.2ps min, 50.5ps max; typ from 0.958 V to 1.1 V
|   falling waveform, R_fixture 50, V_fixture 0.0: 20-80 % time 47.4ps typ, 51.5ps min, 43.3ps max; typ from 0.305 V to 0.001 V
[Pulldown]
|   Voltage   I(typ)   I(min)   I(max)
-1.1V     -27.78mA   -23.99mA   -31.46mA
-928.4mV  -23.32mA   -20.17mA   -26.31mA
-720.5mV  -17.47mA   -15mA      -19.88mA
-506mV    -10.72mA   -8.467mA   -13.25mA
-344.3mV  -4.949mA   -3.634mA   -6.825mA
-232.1mV  -2.078mA   -1.645mA   -2.848mA
-133.1mV  -832.5uA   -755.8uA   -927.9uA
0V        -19.79uA   -16.35uA   -14.41uA
375.1mV   1.526mA    1.497mA    1.571mA
863.5mV   2.71mA     2.491mA    3.084mA
1.391V    3.275mA    2.965mA    3.873mA
2.2V      3.814mA    3.471mA    4.502mA
[GND Clamp]
|   Voltage   I(typ)   I(min)   I(max)
-1.1V     -34.75mA   -30.2mA    -42.92mA
-1.027V   -30.44mA   -26.03mA   -37.57mA
-935mV    -24.61mA   -20.88mA   -30.86mA
-789.8mV  -15.73mA   -12.78mA   -20.73mA
-667.7mV  -8.911mA   -6.72mA    -12.3mA
-591.8mV  -5.257mA   -3.788mA   -7.499mA
-525.8mV  -2.767mA   -1.975mA   -3.966mA
-469.7mV  -1.356mA   -985.5uA   -1.789mA
-413.6mV  -564uA     -417.2uA   -620.9uA
-357.5mV  -191.5uA   -144.5uA   -173.6uA
-255.2mV  -14.7uA    -12.98uA   -8.827uA
2.2V      0A         0A         0A
[Pullup]
|   Voltage   I(typ)   I(min)   I(max)
-1.1V     2.737uA    4.954uA    907.4nA
262.9mV   -43.17uA   -41.94uA   -44.28uA
391.6mV   -403.5uA   -335.7uA   -480uA
497.2mV   -1.327mA   -1.186mA   -1.397mA
609.4mV   -2.879mA   -2.883mA   -2.763mA
748mV     -5.234mA   -5.722mA   -4.774mA
1.042V    -10.85mA   -12.64mA   -9.701mA
1.425V    -18.69mA   -21.71mA   -16.87mA
1.642V    -23.05mA   -26.16mA   -21.76mA
1.887V    -28.02mA   -29.79mA   -27.54mA
2.101V    -32.76mA   -33.11mA   -33.27mA
2.2V      -34.89mA   -34.37mA   -35.86mA
[POWER Clamp]
|   Voltage   I(typ)   I(min)   I(max)
-1.1V     3.033mA    3.633mA    2.184mA
-1.054V   2.491mA    3.082mA    1.736mA
-977.9mV  1.723mA    2.241mA    1.16mA
-911.9mV  1.2mA      1.61mA     764.7uA
-852.5mV  818.3uA    1.148mA    543.6uA
-779.9mV  447.9uA    701.4uA    396.3uA
-710.6mV  232.3uA    359.1uA    273.1uA
-654.5mV  142.6uA    170.5uA    185.9uA
-591.8mV  77.91uA    64.81uA    105.5uA
-492.8mV  18.88uA    11.57uA    24.03uA
-383.9mV  1.75uA     1.212uA    1.463uA
2.2V      0A         0A         0A
[Ramp]
|   typ   min   max
| 20% - 80%
dV/dt_r   182.39m/40.62p   179.46m/44.35p   191.72m/36.95p
dV/dt_f   85.15m/67.67p   76.64m/78.17p   100.79m/57.60p
| 25% - 75%
|dV/dt_r   151.99m/32.34p   149.55m/35.31p   159.76m/29.40p
|dV/dt_f   70.96m/53.84p   63.87m/62.06p   83.99m/45.83p
R_load = 50
[Rising Waveform]
R_fixture = 50
V_fixture = 0.0
|   Time   V(typ)   V(min)   V(max)
0s        784.6uV    650.2uV    572.4uV
57ps      544uV      -48.6uV    6.197mV
66ps      3.25mV     -232.8uV   31.87mV
77ps      13.23mV    2.004mV    97.6mV
104ps     141.6mV    34.51mV    240.9mV
121ps     216.5mV    111.2mV    283.4mV
138ps     260.8mV    188.2mV    304mV
163ps     290.5mV    256.6mV    315.6mV
195ps     301.8mV    289mV      319.3mV
378ps     304.8mV    299.7mV    320.1mV
[Falling Waveform]
R_fixture   = 50
V_fixture   = 1.1
V_fixture_min = 1.06
V_fixture_max = 1.17
|   Time   V(typ)   V(min)   V(max)
0s        1.1V       1.06V      1.17V
70ps      1.099V     1.061V     1.165V
77ps      1.097V     1.06V      1.156V
93ps      1.091V     1.056V     1.12V
124ps     1.046V     1.043V     1.058V
146ps     1.014V     1.019V     1.033V
170ps     990.7mV    990.6mV    1.018V
204ps     972.4mV    962mV      1.008V
246ps     962.9mV    943.9mV    1.004V
378ps     958.1mV    932.3mV    1.002V
[Rising Waveform]
R_fixture   = 50
V_fixture   = 1.1
V_fixture_min = 1.06
V_fixture_max = 1.17
|   Time   V(typ)   V(min)   V(max)
0s        957.9mV    931.6mV    1.002V
47ps      955.8mV    930.2mV    1.002V
57ps      957.6mV    928.1mV    1.018V
70ps      977.3mV    931mV      1.061V
88ps      1.024V     961.7mV    1.105V
103ps     1.05V      996.1mV    1.126V
117ps     1.065V     1.018V     1.14V
138ps     1.079V     1.036V     1.153V
210ps     1.096V     1.056V     1.167V
378ps     1.1V       1.06V      1.17V
[Falling Waveform]
R_fixture = 50
V_fixture = 0.0
|   Time   V(typ)   V(min)   V(max)
0s        304.9mV    299.8mV    320.2mV
61ps      310.2mV    304.1mV    315.8mV
71ps      307.4mV    309.8mV    280.3mV
86ps      262.5mV    306.3mV    179.1mV
98ps      195.1mV    273.2mV    121.2mV
115ps     117mV      191.2mV    71.22mV
146ps     47.48mV    81.59mV    27.47mV
174ps     21.53mV    37.98mV    11.89mV
213ps     7.608mV    13.66mV    3.994mV
378ps     933.1uV    922.8uV    632.4uV
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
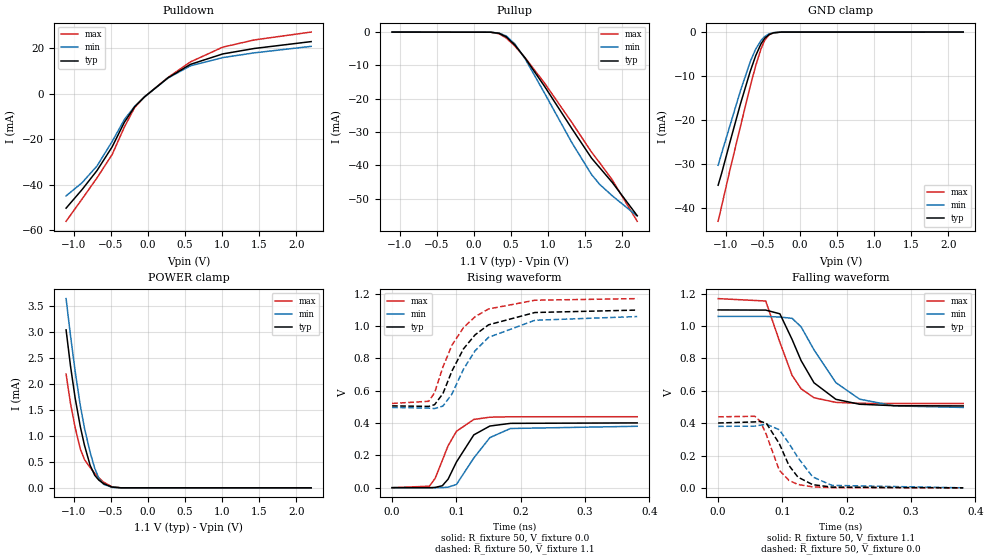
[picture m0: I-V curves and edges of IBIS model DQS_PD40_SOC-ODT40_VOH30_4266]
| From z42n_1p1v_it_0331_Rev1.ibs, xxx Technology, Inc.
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| DQS_PD40_SOC-ODT40_VOH30_4266
| (40 Ohm Pulldown, 40 Ohm System ODT Setting, VOH=VDDQ/3.0, 3200-4266Mbps)
[Model]   DQS_PD40_SOC-ODT40_VOH30_4266
Model_type   I/O
Vinl = 123.333mV
Vinh = 243.333mV
Vmeas = 183.333mV
Vref = 0.0mV
Cref = 0.0pF
Rref = 40.000Ohm
|   typ   min   max
|C_comp   0.849pF   0.799pF   0.899pF
C_comp_pullup   0.4245pF   0.3995pF   0.4495pF
C_comp_pulldown   0.4245pF   0.3995pF   0.4495pF
| Note: C_comp changes when the ODT circuit is enabled.
[Model Spec]
| Input threshold voltage corners
Vinl   0.1233V   0.1167V   0.1350V
Vinh   0.2433V   0.2367V   0.2550V
| Measurement voltage corners
Vmeas   0.1833V   0.1767V   0.1950V
| Timing spec test load voltage corners
Vref   0.0000V   0.0000V   0.0000V
| Dynamic Overshoot Parameters from LPDDR4 Specification
D_overshoot_ampl_h   0.30   NA   NA
D_overshoot_ampl_l   0.30   NA   NA
D_overshoot_area_h   0.1n   NA   NA
D_overshoot_area_l   0.1n   NA   NA
[Voltage Range]   1.1000V   1.0600V   1.1700V
[Pullup Reference]   1.1000V   1.0600V   1.1700V
| Junction Temperature (Ambient temp is 35C typ 95C min -40C max)
[Temperature Range]   50.0   110.0   -40.0
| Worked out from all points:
|   slope of the pulldown table from 0 to 0.165 V, typ, clamps not added: 36.9 ohm
|   slope of the pullup table from 0 to 0.165 V, typ, clamps not added: 13.1 kohm
|   GND clamp passes 1 mA (typ) near -0.45 V on its own axis
|   POWER clamp passes 1 mA (typ) near -0.88 V on its own axis
|   rising waveform, R_fixture 50, V_fixture 0.0: 20-80 % time 34.6ps typ, 38.5ps min, 30.1ps max; typ from 0.001 V to 0.401 V
|   falling waveform, R_fixture 50, V_fixture 1.1: 20-80 % time 45.8ps typ, 57.5ps min, 35.9ps max; typ from 1.1 V to 0.507 V
|   rising waveform, R_fixture 50, V_fixture 1.1: 20-80 % time 55.8ps typ, 59.1ps min, 51.8ps max; typ from 0.507 V to 1.1 V
|   falling waveform, R_fixture 50, V_fixture 0.0: 20-80 % time 31.1ps typ, 39.2ps min, 25.8ps max; typ from 0.401 V to 0.001 V
[Pulldown]
|   Voltage   I(typ)   I(min)   I(max)
-1.1V     -50.2mA    -44.82mA   -55.96mA
-885.5mV  -42.07mA   -39.05mA   -46.22mA
-684.2mV  -33.7mA    -31.69mA   -36.93mA
-479.6mV  -23.26mA   -20.91mA   -26.61mA
-314.6mV  -12.44mA   -11.23mA   -14.52mA
-176mV    -5.609mA   -5.442mA   -5.939mA
-44mV     -1.309mA   -1.3mA     -1.284mA
272.8mV   7.088mA    6.98mA     7.23mA
573.1mV   12.96mA    12.33mA    14.03mA
1.009V    17.56mA    15.95mA    20.54mA
1.434V    19.96mA    18.04mA    23.71mA
2.2V      22.98mA    20.89mA    27.18mA
[GND Clamp]
|   Voltage   I(typ)   I(min)   I(max)
-1.1V     -34.74mA   -30.21mA   -42.91mA
-1.05V    -31.86mA   -27.33mA   -39.27mA
-941.6mV  -25.02mA   -21.26mA   -31.32mA
-799.7mV  -16.31mA   -13.32mA   -21.42mA
-667.7mV  -8.907mA   -6.722mA   -12.29mA
-595.1mV  -5.399mA   -3.899mA   -7.689mA
-522.5mV  -2.664mA   -1.902mA   -3.812mA
-473mV    -1.421mA   -1.031mA   -1.888mA
-416.9mV  -604.9uA   -440.1uA   -666.1uA
-354.2mV  -179.2uA   -134.5uA   -160uA
-248.6mV  -12.37uA   -10.94uA   -7.168uA
2.2V      0A         0A         0A
[Pullup]
|   Voltage   I(typ)   I(min)   I(max)
-1.1V     6.275uA    9.671uA    2.829uA
226.6mV   -42.05uA   -43.01uA   -42.87uA
342.1mV   -380.5uA   -313.4uA   -524.7uA
437.8mV   -1.437mA   -1.177mA   -1.807mA
553.3mV   -3.879mA   -3.574mA   -4.208mA
695.2mV   -7.909mA   -8.165mA   -7.815mA
955.9mV   -16.38mA   -18.46mA   -15.4mA
1.322V    -28.99mA   -33.23mA   -27.17mA
1.586V    -37.82mA   -42.74mA   -36.02mA
1.695V    -40.67mA   -45.67mA   -39.19mA
1.867V    -45.16mA   -49.15mA   -44.41mA
2.2V      -55.05mA   -55.17mA   -56.74mA
[POWER Clamp]
|   Voltage   I(typ)   I(min)   I(max)
-1.1V     3.033mA    3.633mA    2.184mA
-1.041V   2.345mA    2.929mA    1.625mA
-977.9mV  1.723mA    2.241mA    1.16mA
-908.6mV  1.177mA    1.582mA    747uA
-852.5mV  818.3uA    1.148mA    543.5uA
-776.6mV  434.1uA    683.3uA    390.2uA
-713.9mV  239.3uA    373uA      278.6uA
-657.8mV  146.8uA    178.8uA    190.7uA
-595.1mV  80.74uA    68.29uA    109.3uA
-482.9mV  15.72uA    9.483uA    19.49uA
-364.1mV  1.116uA    820nA      867nA
2.2V      0A         0A         0A
[Ramp]
|   typ   min   max
| 20% - 80%
dV/dt_r   240.33m/34.56p   227.87m/38.49p   263.36m/30.08p
dV/dt_f   356.01m/45.76p   337.60m/57.53p   389.19m/35.90p
| 25% - 75%
|dV/dt_r   200.27m/27.53p   189.89m/30.67p   219.46m/23.85p
|dV/dt_f   296.67m/36.50p   281.33m/45.92p   324.32m/28.58p
R_load = 50
[Rising Waveform]
R_fixture = 50
V_fixture = 0.0
|   Time   V(typ)   V(min)   V(max)
0s        555.3uV    475.8uV    405.9uV
58ps      265.4uV    42.33uV    9.634mV
67ps      2.281mV    -539.9uV   58.87mV
78ps      12.17mV    763.2uV    168.8mV
87ps      52.88mV    3.665mV    259.5mV
100ps     158.9mV    20.13mV    349.2mV
127ps     327mV      184mV      422.4mV
152ps     381.8mV    310.2mV    436.5mV
184ps     398.3mV    366.5mV    439.1mV
381ps     401.1mV    380.3mV    439.3mV
[Falling Waveform]
R_fixture   = 50
V_fixture   = 1.1
V_fixture_min = 1.06
V_fixture_max = 1.17
|   Time   V(typ)   V(min)   V(max)
0s        1.1V       1.06V      1.17V
74ps      1.099V     1.06V      1.155V
96ps      1.076V     1.056V     899.7mV
115ps     917.3mV    1.048V     695.5mV
129ps     786.7mV    995.6mV    612.8mV
149ps     649.8mV    853.7mV    557.3mV
183ps     547.6mV    650.8mV    528.7mV
220ps     517mV      548.4mV    522.7mV
274ps     508.1mV    506.7mV    521.5mV
381ps     506.7mV    497.3mV    521.4mV
[Rising Waveform]
R_fixture   = 50
V_fixture   = 1.1
V_fixture_min = 1.06
V_fixture_max = 1.17
|   Time   V(typ)   V(min)   V(max)
0s        506.5mV    496.8mV    521.3mV
57ps      503.2mV    492.5mV    534.9mV
66ps      513.8mV    490mV      587.2mV
79ps      582.3mV    505.1mV    746.8mV
93ps      722mV      579.4mV    881.6mV
111ps     859.4mV    733.7mV    990.9mV
129ps     945.9mV    847.5mV    1.058V
150ps     1.008V     930.4mV    1.106V
222ps     1.084V     1.036V     1.16V
381ps     1.099V     1.059V     1.17V
[Falling Waveform]
R_fixture = 50
V_fixture = 0.0
|   Time   V(typ)   V(min)   V(max)
0s        401.2mV    380.4mV    439.4mV
57ps      407.8mV    381.8mV    442.6mV
66ps      411.1mV    388mV      409.9mV
75ps      399.5mV    393.6mV    328.5mV
95ps      274.2mV    359.7mV    109.8mV
110ps     139.5mV    275.8mV    46.36mV
124ps     66.78mV    187.5mV    21.27mV
147ps     20.1mV     67.74mV    6.235mV
177ps     4.831mV    15.51mV    1.586mV
381ps     605.8uV    554uV      424.5uV
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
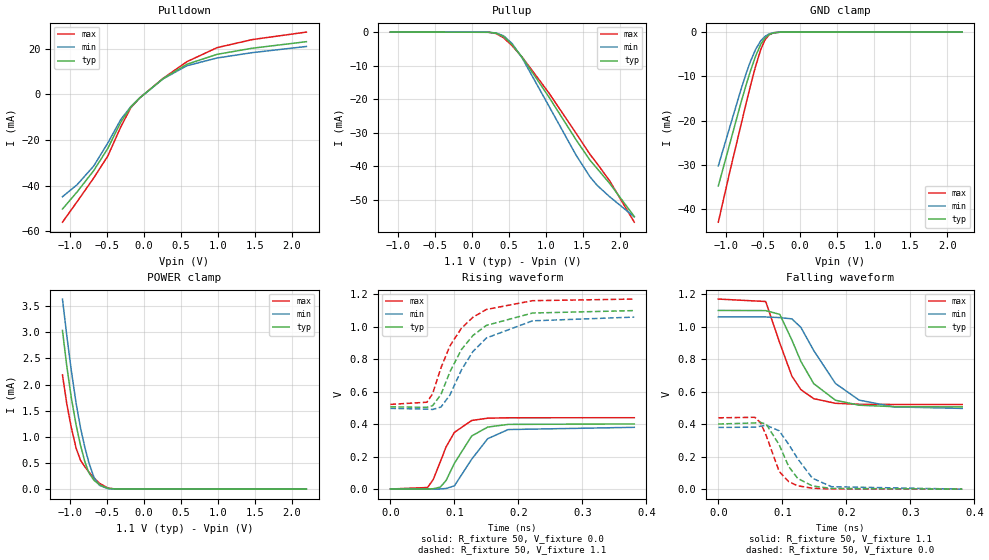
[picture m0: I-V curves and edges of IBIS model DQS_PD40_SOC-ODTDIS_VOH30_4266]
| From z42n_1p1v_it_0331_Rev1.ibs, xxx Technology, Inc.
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| DQS_PD40_SOC-ODTDIS_VOH30_4266
| (40 Ohm Pulldown, SOC ODT disabled setting, VOH=VDDQ/3.0 cal. point, 3200-4266Mbps)
[Model]   DQS_PD40_SOC-ODTDIS_VOH30_4266
Model_type   I/O
Vinl = 123.333mV
Vinh = 243.333mV
Vmeas = 183.333mV
Vref = 0.0mV
Cref = 0.0pF
|   typ   min   max
|C_comp   0.849pF   0.799pF   0.899pF
C_comp_pullup   0.4245pF   0.3995pF   0.4495pF
C_comp_pulldown   0.4245pF   0.3995pF   0.4495pF
| Note: C_comp changes when the ODT circuit is enabled.
[Model Spec]
| Input threshold voltage corners
Vinl   0.1233V   0.1167V   0.1350V
Vinh   0.2433V   0.2367V   0.2550V
| Measurement voltage corners
Vmeas   0.1833V   0.1767V   0.1950V
| Timing spec test load voltage corners
Vref   0.0000V   0.0000V   0.0000V
| Dynamic Overshoot Parameters from LPDDR4 Specification
D_overshoot_ampl_h   0.30   NA   NA
D_overshoot_ampl_l   0.30   NA   NA
D_overshoot_area_h   0.1n   NA   NA
D_overshoot_area_l   0.1n   NA   NA
[Voltage Range]   1.1000V   1.0600V   1.1700V
[Pullup Reference]   1.1000V   1.0600V   1.1700V
| Junction Temperature (Ambient temp is 35C typ 95C min -40C max)
[Temperature Range]   50.0   110.0   -40.0
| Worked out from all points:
|   slope of the pulldown table from 0 to 0.165 V, typ, clamps not added: 36.9 ohm
|   slope of the pullup table from 0 to 0.165 V, typ, clamps not added: 13 kohm
|   GND clamp passes 1 mA (typ) near -0.45 V on its own axis
|   POWER clamp passes 1 mA (typ) near -0.88 V on its own axis
|   rising waveform, R_fixture 50, V_fixture 0.0: 20-80 % time 34.6ps typ, 38.5ps min, 30.1ps max; typ from 0.001 V to 0.401 V
|   falling waveform, R_fixture 50, V_fixture 1.1: 20-80 % time 45.8ps typ, 57.5ps min, 35.9ps max; typ from 1.1 V to 0.507 V
|   rising waveform, R_fixture 50, V_fixture 1.1: 20-80 % time 55.8ps typ, 59.1ps min, 51.8ps max; typ from 0.507 V to 1.1 V
|   falling waveform, R_fixture 50, V_fixture 0.0: 20-80 % time 31.1ps typ, 39.2ps min, 25.8ps max; typ from 0.401 V to 0.001 V
[Pulldown]
|   Voltage   I(typ)   I(min)   I(max)
-1.1V     -50.2mA    -44.82mA   -55.96mA
-902mV    -42.72mA   -39.57mA   -47mA
-677.6mV  -33.41mA   -31.41mA   -36.63mA
-486.2mV  -23.68mA   -21.31mA   -27.01mA
-311.3mV  -12.24mA   -11.06mA   -14.28mA
-176mV    -5.607mA   -5.442mA   -5.938mA
-53.9mV   -1.602mA   -1.591mA   -1.578mA
262.9mV   6.855mA    6.755mA    6.982mA
583mV     13.12mA    12.46mA    14.23mA
992.2mV   17.45mA    15.85mA    20.38mA
1.467V    20.12mA    18.19mA    23.9mA
2.2V      22.98mA    20.89mA    27.18mA
[GND Clamp]
|   Voltage   I(typ)   I(min)   I(max)
-1.1V     -34.74mA   -30.21mA   -42.91mA
-941.6mV  -25.02mA   -21.26mA   -31.32mA
-793.1mV  -15.92mA   -12.96mA   -20.95mA
-723.8mV  -11.93mA   -9.348mA   -16.1mA
-667.7mV  -8.907mA   -6.721mA   -12.29mA
-595.1mV  -5.399mA   -3.899mA   -7.688mA
-525.8mV  -2.766mA   -1.974mA   -3.963mA
-469.7mV  -1.356mA   -985.1uA   -1.788mA
-413.6mV  -565.7uA   -416.1uA   -622.6uA
-354.2mV  -179.3uA   -134.4uA   -160.1uA
-258.5mV  -16.15uA   -14.14uA   -9.912uA
2.2V      0A         0A         0A
[Pullup]
|   Voltage   I(typ)   I(min)   I(max)
-1.1V     6.275uA    9.671uA    2.829uA
226.6mV   -42.02uA   -43.09uA   -42.82uA
328.9mV   -305.6uA   -254.6uA   -416.9uA
431.2mV   -1.333mA   -1.087mA   -1.694mA
546.7mV   -3.712mA   -3.398mA   -4.054mA
685.3mV   -7.607mA   -7.806mA   -7.548mA
1.042V    -19.28mA   -21.97mA   -18.07mA
1.411V    -32.1mA    -36.67mA   -30.15mA
1.599V    -38.2mA    -43.14mA   -36.44mA
1.698V    -40.75mA   -45.75mA   -39.28mA
1.867V    -45.16mA   -49.15mA   -44.41mA
2.2V      -55.05mA   -55.17mA   -56.74mA
[POWER Clamp]
|   Voltage   I(typ)   I(min)   I(max)
-1.1V     3.033mA    3.633mA    2.184mA
-1.041V   2.345mA    2.929mA    1.625mA
-981.2mV  1.752mA    2.275mA    1.183mA
-915.2mV  1.223mA    1.639mA    781.6uA
-855.8mV  837.9uA    1.171mA    552.2uA
-796.4mV  521.2uA    794.8uA    427.2uA
-743.6mV  315.9uA    510.6uA    330.1uA
-674.3mV  169.2uA    226uA      215.1uA
-598.4mV  83.64uA    71.96uA    113.1uA
-486.2mV  16.69uA    10.12uA    20.96uA
-367.4mV  1.194uA    872.8nA    950.4nA
2.2V      0A         0A         0A
[Ramp]
|   typ   min   max
| 20% - 80%
dV/dt_r   240.33m/34.56p   227.87m/38.49p   263.36m/30.08p
dV/dt_f   356.01m/45.76p   337.60m/57.53p   389.19m/35.90p
| 25% - 75%
|dV/dt_r   200.27m/27.53p   189.89m/30.67p   219.46m/23.85p
|dV/dt_f   296.67m/36.50p   281.33m/45.92p   324.32m/28.58p
R_load = 50
[Rising Waveform]
R_fixture = 50
V_fixture = 0.0
|   Time   V(typ)   V(min)   V(max)
0s        555.3uV    475.8uV    405.9uV
58ps      265.4uV    42.33uV    9.634mV
67ps      2.281mV    -539.9uV   58.87mV
78ps      12.17mV    763.2uV    168.8mV
87ps      52.88mV    3.665mV    259.5mV
100ps     158.9mV    20.13mV    349.2mV
127ps     327mV      184mV      422.4mV
152ps     381.8mV    310.2mV    436.5mV
184ps     398.3mV    366.5mV    439.1mV
381ps     401.1mV    380.3mV    439.3mV
[Falling Waveform]
R_fixture   = 50
V_fixture   = 1.1
V_fixture_min = 1.06
V_fixture_max = 1.17
|   Time   V(typ)   V(min)   V(max)
0s        1.1V       1.06V      1.17V
74ps      1.099V     1.06V      1.155V
96ps      1.076V     1.056V     899.7mV
115ps     917.3mV    1.048V     695.5mV
129ps     786.7mV    995.6mV    612.8mV
149ps     649.8mV    853.7mV    557.3mV
183ps     547.6mV    650.8mV    528.7mV
220ps     517mV      548.4mV    522.7mV
274ps     508.1mV    506.7mV    521.5mV
381ps     506.7mV    497.3mV    521.4mV
[Rising Waveform]
R_fixture   = 50
V_fixture   = 1.1
V_fixture_min = 1.06
V_fixture_max = 1.17
|   Time   V(typ)   V(min)   V(max)
0s        506.5mV    496.8mV    521.3mV
57ps      503.2mV    492.5mV    534.9mV
66ps      513.8mV    490mV      587.2mV
79ps      582.3mV    505.1mV    746.8mV
93ps      722mV      579.4mV    881.6mV
111ps     859.4mV    733.7mV    990.9mV
129ps     945.9mV    847.5mV    1.058V
150ps     1.008V     930.4mV    1.106V
222ps     1.084V     1.036V     1.16V
381ps     1.099V     1.059V     1.17V
[Falling Waveform]
R_fixture = 50
V_fixture = 0.0
|   Time   V(typ)   V(min)   V(max)
0s        401.2mV    380.4mV    439.4mV
57ps      407.8mV    381.8mV    442.6mV
66ps      411.1mV    388mV      409.9mV
75ps      399.5mV    393.6mV    328.5mV
95ps      274.2mV    359.7mV    109.8mV
110ps     139.5mV    275.8mV    46.36mV
124ps     66.78mV    187.5mV    21.27mV
147ps     20.1mV     67.74mV    6.235mV
177ps     4.831mV    15.51mV    1.586mV
381ps     605.8uV    554uV      424.5uV
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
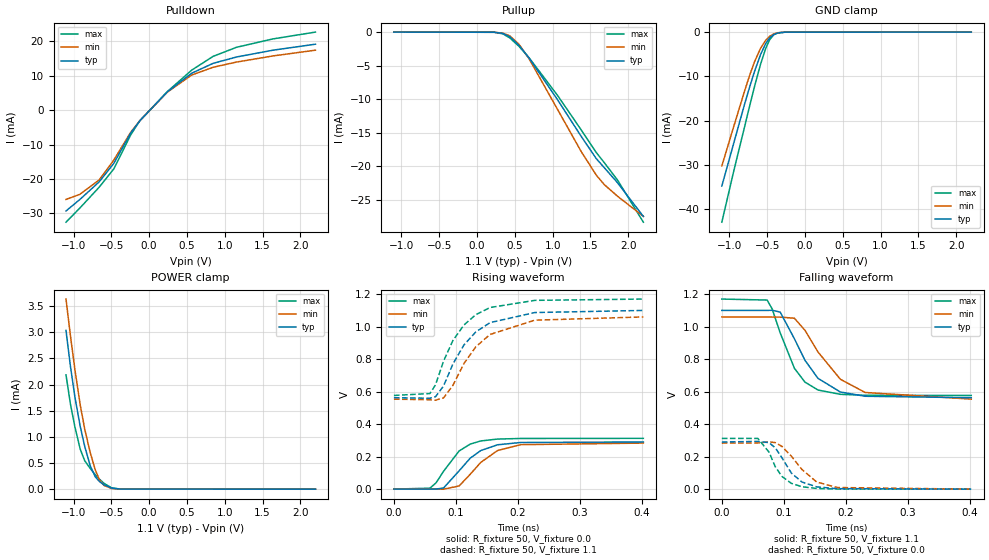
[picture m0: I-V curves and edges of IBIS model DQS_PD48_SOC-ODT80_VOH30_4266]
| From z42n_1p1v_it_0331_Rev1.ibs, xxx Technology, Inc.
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| DQS_PD48_SOC-ODT80_VOH30_4266
| (48 Ohm Pulldown, 80 Ohm System ODT Setting, VOH=VDDQ/3.0, 3200-4266Mbps)
[Model]   DQS_PD48_SOC-ODT80_VOH30_4266
Model_type   I/O
Vinl = 123.333mV
Vinh = 243.333mV
Vmeas = 183.333mV
Vref = 0.0mV
Cref = 0.0pF
Rref = 80.000Ohm
|   typ   min   max
|C_comp   0.849pF   0.799pF   0.899pF
C_comp_pullup   0.4245pF   0.3995pF   0.4495pF
C_comp_pulldown   0.4245pF   0.3995pF   0.4495pF
| Note: C_comp changes when the ODT circuit is enabled.
[Model Spec]
| Input threshold voltage corners
Vinl   0.1233V   0.1167V   0.1350V
Vinh   0.2433V   0.2367V   0.2550V
| Measurement voltage corners
Vmeas   0.1833V   0.1767V   0.1950V
| Timing spec test load voltage corners
Vref   0.0000V   0.0000V   0.0000V
| Dynamic Overshoot Parameters from LPDDR4 Specification
D_overshoot_ampl_h   0.30   NA   NA
D_overshoot_ampl_l   0.30   NA   NA
D_overshoot_area_h   0.1n   NA   NA
D_overshoot_area_l   0.1n   NA   NA
[Voltage Range]   1.1000V   1.0600V   1.1700V
[Pullup Reference]   1.1000V   1.0600V   1.1700V
| Junction Temperature (Ambient temp is 35C typ 95C min -40C max)
[Temperature Range]   50.0   110.0   -40.0
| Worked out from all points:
|   slope of the pulldown table from 0 to 0.165 V, typ, clamps not added: 43.9 ohm
|   slope of the pullup table from 0 to 0.165 V, typ, clamps not added: 26 kohm
|   GND clamp passes 1 mA (typ) near -0.45 V on its own axis
|   POWER clamp passes 1 mA (typ) near -0.88 V on its own axis
|   rising waveform, R_fixture 50, V_fixture 0.0: 20-80 % time 43ps typ, 46ps min, 37.6ps max; typ from 0 V to 0.29 V
|   falling waveform, R_fixture 50, V_fixture 1.1: 20-80 % time 48.9ps typ, 61.1ps min, 38.9ps max; typ from 1.1 V to 0.563 V
|   rising waveform, R_fixture 50, V_fixture 1.1: 20-80 % time 56.5ps typ, 60.5ps min, 52.2ps max; typ from 0.563 V to 1.1 V
|   falling waveform, R_fixture 50, V_fixture 0.0: 20-80 % time 32.5ps typ, 40.5ps min, 27.8ps max; typ from 0.29 V to 0 V
[Pulldown]
|   Voltage   I(typ)   I(min)   I(max)
-1.1V     -29.31mA   -25.95mA   -32.57mA
-918.5mV  -26mA      -24.49mA   -28.5mA
-661.1mV  -20.85mA   -20.29mA   -22.4mA
-466.4mV  -15.43mA   -14.48mA   -17.04mA
-245.3mV  -6.697mA   -6.46mA    -7.234mA
-123.2mV  -3.076mA   -3.063mA   -3.08mA
239.8mV   5.304mA    5.231mA    5.394mA
563.2mV   10.75mA    10.22mA    11.64mA
847mV     13.62mA    12.47mA    15.65mA
1.157V    15.46mA    13.99mA    18.29mA
1.636V    17.43mA    15.76mA    20.71mA
2.2V      19.18mA    17.44mA    22.7mA
[GND Clamp]
|   Voltage   I(typ)   I(min)   I(max)
-1.1V     -34.74mA   -30.21mA   -42.91mA
-941.6mV  -25.02mA   -21.26mA   -31.32mA
-796.4mV  -16.11mA   -13.14mA   -21.19mA
-723.8mV  -11.93mA   -9.349mA   -16.1mA
-664.4mV  -8.736mA   -6.578mA   -12.07mA
-588.5mV  -5.112mA   -3.681mA   -7.298mA
-519.2mV  -2.565mA   -1.832mA   -3.66mA
-466.4mV  -1.295mA   -941.3uA   -1.69mA
-413.6mV  -565uA     -416.7uA   -620.3uA
-357.5mV  -191.8uA   -144.1uA   -173.1uA
-258.5mV  -16.05uA   -14.26uA   -9.823uA
2.2V      0A         0A         0A
[Pullup]
|   Voltage   I(typ)   I(min)   I(max)
-1.1V     3.138uA    4.837uA    1.415uA
229.9mV   -22.54uA   -23.04uA   -23.32uA
342.1mV   -191.9uA   -157uA     -262.8uA
434.5mV   -694.3uA   -568.3uA   -877.6uA
553.3mV   -1.948mA   -1.797mA   -2.113mA
688.6mV   -3.877mA   -3.992mA   -3.837mA
1.065V    -10.1mA    -11.55mA   -9.452mA
1.375V    -15.52mA   -17.78mA   -14.56mA
1.576V    -18.87mA   -21.34mA   -17.96mA
1.685V    -20.27mA   -22.79mA   -19.52mA
1.857V    -22.47mA   -24.49mA   -22.07mA
2.2V      -27.52mA   -27.51mA   -28.38mA
[POWER Clamp]
|   Voltage   I(typ)   I(min)   I(max)
-1.1V     3.033mA    3.633mA    2.184mA
-1.041V   2.345mA    2.929mA    1.625mA
-981.2mV  1.753mA    2.275mA    1.183mA
-911.9mV  1.2mA      1.611mA    764.4uA
-852.5mV  818.4uA    1.149mA    543.6uA
-779.9mV  447.9uA    701.6uA    396.3uA
-713.9mV  239.3uA    373uA      278.6uA
-657.8mV  146.8uA    178.8uA    190.7uA
-598.4mV  83.67uA    71.98uA    113uA
-496.1mV  20.08uA    12.31uA    25.7uA
-380.6mV  1.605uA    1.128uA    1.335uA
2.2V      0A         0A         0A
[Ramp]
|   typ   min   max
| 20% - 80%
dV/dt_r   173.93m/42.98p   169.87m/46.04p   187.31m/37.61p
dV/dt_f   322.28m/48.94p   303.39m/61.11p   355.99m/38.85p
| 25% - 75%
|dV/dt_r   144.94m/34.27p   141.56m/36.75p   156.10m/29.83p
|dV/dt_f   268.57m/39.08p   252.83m/48.77p   296.66m/30.94p
R_load = 50
[Rising Waveform]
R_fixture = 50
V_fixture = 0.0
|   Time   V(typ)   V(min)   V(max)
0s        301.2uV    248.7uV    223.8uV
58ps      213.5uV    308.8uV    5.501mV
68ps      172.9uV    -225.2uV   39.05mV
80ps      7.078mV    -404.7uV   109.8mV
105ps     112mV      19.18mV    234.5mV
123ps     190.6mV    91.34mV    277.2mV
140ps     237.3mV    164.6mV    296.5mV
167ps     272.8mV    237.4mV    308.1mV
204ps     286.9mV    273.5mV    311.7mV
402ps     290.2mV    283.4mV    312.4mV
[Falling Waveform]
R_fixture   = 50
V_fixture   = 1.1
V_fixture_min = 1.06
V_fixture_max = 1.17
|   Time   V(typ)   V(min)   V(max)
0s        1.1V       1.06V      1.17V
73ps      1.1V       1.06V      1.164V
81ps      1.101V     1.059V     1.11V
94ps      1.09V      1.059V     962.6mV
117ps     925.3mV    1.052V     743.8mV
134ps     793.2mV    977.8mV    658.9mV
155ps     681.9mV    844.4mV    610.2mV
191ps     598.2mV    676.6mV    583.8mV
231ps     571.9mV    595.1mV    578mV
402ps     562.9mV    554.3mV    576.7mV
[Rising Waveform]
R_fixture   = 50
V_fixture   = 1.1
V_fixture_min = 1.06
V_fixture_max = 1.17
|   Time   V(typ)   V(min)   V(max)
0s        562.7mV    553.9mV    576.6mV
58ps      559.3mV    549.8mV    588.4mV
67ps      568.5mV    547.4mV    641.5mV
80ps      634.8mV    561.4mV    788.2mV
95ps      770mV      638mV      914.4mV
113ps     888.5mV    774.4mV    1.011V
132ps     967.7mV    876.3mV    1.074V
155ps     1.025V     952.2mV    1.118V
227ps     1.087V     1.04V      1.162V
402ps     1.1V       1.06V      1.17V
[Falling Waveform]
R_fixture = 50
V_fixture = 0.0
|   Time   V(typ)   V(min)   V(max)
0s        290.3mV    283.5mV    312.5mV
58ps      294.4mV    284.6mV    312.5mV
76ps      286.6mV    291.5mV    228.6mV
86ps      255.2mV    286.9mV    139.2mV
97ps      192.6mV    262.9mV    78.1mV
112ps     99.68mV    203.3mV    36.01mV
129ps     44.27mV    121.7mV    15.18mV
153ps     14.35mV    43.87mV    4.659mV
186ps     3.401mV    10.3mV     1.097mV
402ps     370.7uV    348.6uV    245.1uV
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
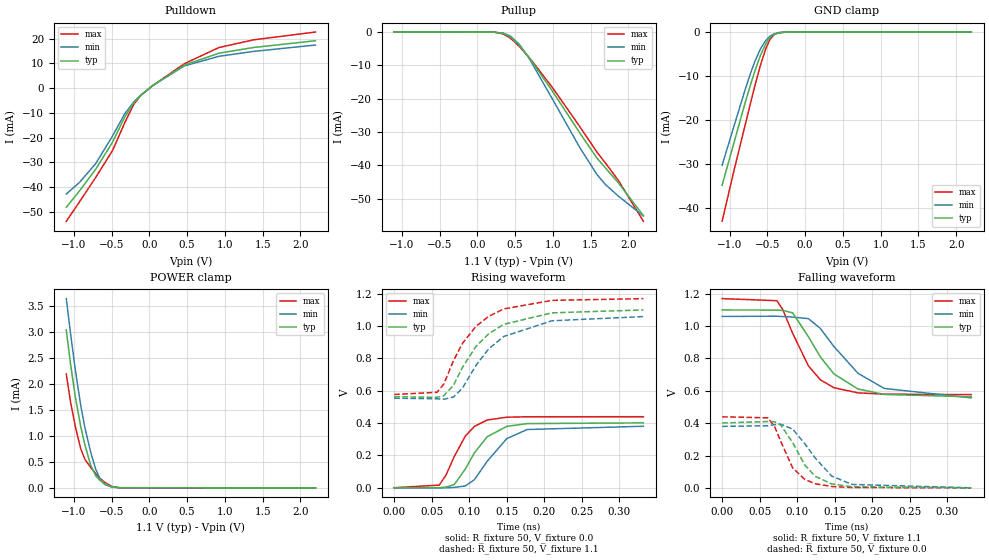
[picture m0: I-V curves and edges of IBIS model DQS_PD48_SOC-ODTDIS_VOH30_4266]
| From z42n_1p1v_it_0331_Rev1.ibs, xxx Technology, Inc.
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| DQS_PD48_SOC-ODTDIS_VOH30_4266
| (48 Ohm Pulldown, SOC ODT disabled setting, VOH=VDDQ/3.0 cal. point, 3200-4266Mbps)
[Model]   DQS_PD48_SOC-ODTDIS_VOH30_4266
Model_type   I/O
Vinl = 123.333mV
Vinh = 243.333mV
Vmeas = 183.333mV
Vref = 0.0mV
Cref = 0.0pF
|   typ   min   max
|C_comp   0.849pF   0.799pF   0.899pF
C_comp_pullup   0.4245pF   0.3995pF   0.4495pF
C_comp_pulldown   0.4245pF   0.3995pF   0.4495pF
| Note: C_comp changes when the ODT circuit is enabled.
[Model Spec]
| Input threshold voltage corners
Vinl   0.1233V   0.1167V   0.1350V
Vinh   0.2433V   0.2367V   0.2550V
| Measurement voltage corners
Vmeas   0.1833V   0.1767V   0.1950V
| Timing spec test load voltage corners
Vref   0.0000V   0.0000V   0.0000V
| Dynamic Overshoot Parameters from LPDDR4 Specification
D_overshoot_ampl_h   0.30   NA   NA
D_overshoot_ampl_l   0.30   NA   NA
D_overshoot_area_h   0.1n   NA   NA
D_overshoot_area_l   0.1n   NA   NA
[Voltage Range]   1.1000V   1.0600V   1.1700V
[Pullup Reference]   1.1000V   1.0600V   1.1700V
| Junction Temperature (Ambient temp is 35C typ 95C min -40C max)
[Temperature Range]   50.0   110.0   -40.0
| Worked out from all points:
|   slope of the pulldown table from 0 to 0.165 V, typ, clamps not added: 43.8 ohm
|   slope of the pullup table from 0 to 0.165 V, typ, clamps not added: 13 kohm
|   GND clamp passes 1 mA (typ) near -0.45 V on its own axis
|   POWER clamp passes 1 mA (typ) near -0.88 V on its own axis
|   rising waveform, R_fixture 50, V_fixture 0.0: 20-80 % time 34.7ps typ, 38.8ps min, 30.2ps max; typ from 0.001 V to 0.401 V
|   falling waveform, R_fixture 50, V_fixture 1.1: 20-80 % time 49.3ps typ, 61.2ps min, 39.2ps max; typ from 1.1 V to 0.563 V
|   rising waveform, R_fixture 50, V_fixture 1.1: 20-80 % time 55.5ps typ, 58.1ps min, 51.7ps max; typ from 0.563 V to 1.1 V
|   falling waveform, R_fixture 50, V_fixture 0.0: 20-80 % time 32.5ps typ, 40ps min, 27.6ps max; typ from 0.401 V to 0.001 V
[Pulldown]
|   Voltage   I(typ)   I(min)   I(max)
-1.1V     -48.22mA   -42.83mA   -53.87mA
-925.1mV  -41.61mA   -38.14mA   -46.03mA
-710.6mV  -32.82mA   -30.54mA   -36.14mA
-486.2mV  -21.79mA   -19.31mA   -25.19mA
-324.5mV  -11.65mA   -10.29mA   -13.91mA
-202.4mV  -5.762mA   -5.469mA   -6.379mA
-106.7mV  -2.745mA   -2.709mA   -2.766mA
45.1mV    1.047mA    1.044mA    1.045mA
464.2mV   9.329mA    9.009mA    9.889mA
919.6mV   14.13mA    12.87mA    16.41mA
1.382V    16.46mA    14.87mA    19.56mA
2.2V      19.18mA    17.44mA    22.7mA
[GND Clamp]
|   Voltage   I(typ)   I(min)   I(max)
-1.1V     -34.74mA   -30.22mA   -42.91mA
-938.3mV  -24.81mA   -21.07mA   -31.08mA
-799.7mV  -16.31mA   -13.32mA   -21.42mA
-727.1mV  -12.12mA   -9.513mA   -16.33mA
-667.7mV  -8.907mA   -6.722mA   -12.29mA
-595.1mV  -5.399mA   -3.899mA   -7.688mA
-522.5mV  -2.664mA   -1.909mA   -3.81mA
-466.4mV  -1.294mA   -947.1uA   -1.692mA
-413.6mV  -563.5uA   -419.2uA   -621.5uA
-354.2mV  -178.1uA   -136.5uA   -160.9uA
-248.6mV  -12.11uA   -11.02uA   -7.126uA
2.2V      0A         0A         0A
[Pullup]
|   Voltage   I(typ)   I(min)   I(max)
-1.1V     6.275uA    9.671uA    2.829uA
226.6mV   -42.15uA   -43.09uA   -42.84uA
342.1mV   -382.1uA   -314.3uA   -524.8uA
437.8mV   -1.435mA   -1.178mA   -1.807mA
553.3mV   -3.878mA   -3.574mA   -4.208mA
688.6mV   -7.707mA   -7.925mA   -7.637mA
995.5mV   -17.71mA   -20.08mA   -16.62mA
1.355V    -30.15mA   -34.52mA   -28.27mA
1.586V    -37.82mA   -42.74mA   -36.02mA
1.695V    -40.67mA   -45.67mA   -39.19mA
1.867V    -45.16mA   -49.15mA   -44.41mA
2.2V      -55.05mA   -55.15mA   -56.74mA
[POWER Clamp]
|   Voltage   I(typ)   I(min)   I(max)
-1.1V     3.033mA    3.633mA    2.184mA
-1.044V   2.381mA    2.967mA    1.653mA
-981.2mV  1.753mA    2.275mA    1.183mA
-908.6mV  1.177mA    1.582mA    748uA
-852.5mV  818.2uA    1.148mA    543.7uA
-776.6mV  434uA      683.3uA    390.2uA
-710.6mV  232.2uA    359uA      273.1uA
-651.2mV  138.6uA    162.3uA    181.2uA
-591.8mV  77.9uA     64.83uA    105.5uA
-496.1mV  20.04uA    12.36uA    25.72uA
-390.5mV  2.037uA    1.408uA    1.772uA
2.2V      0A         0A         0A
[Ramp]
|   typ   min   max
| 20% - 80%
dV/dt_r   240.28m/34.75p   227.83m/38.76p   263.33m/30.20p
dV/dt_f   322.12m/49.32p   302.17m/61.19p   355.99m/39.15p
| 25% - 75%
|dV/dt_r   200.24m/27.67p   189.86m/30.88p   219.44m/23.94p
|dV/dt_f   268.43m/39.31p   251.80m/48.83p   296.66m/31.17p
R_load = 50
[Rising Waveform]
R_fixture = 50
V_fixture = 0.0
|   Time   V(typ)   V(min)   V(max)
0s        619.1uV    536.6uV    450.1uV
60ps      1.042mV    -84.49uV   16.73mV
69ps      4.083mV    -175.8uV   78.14mV
80ps      19.77mV    2.236mV    193.1mV
95ps      117.6mV    11.96mV    321.6mV
107ps     217.2mV    51mV       379.9mV
124ps     315.7mV    164.6mV    418.9mV
150ps     379.5mV    303.8mV    436.1mV
177ps     396.8mV    360.1mV    439mV
332ps     401.1mV    380.3mV    439.3mV
[Falling Waveform]
R_fixture   = 50
V_fixture   = 1.1
V_fixture_min = 1.06
V_fixture_max = 1.17
|   Time   V(typ)   V(min)   V(max)
0s        1.1V       1.06V      1.17V
73ps      1.099V     1.061V     1.157V
81ps      1.097V     1.059V     1.101V
94ps      1.082V     1.056V     954.9mV
115ps     934.4mV    1.046V     754.1mV
131ps     808.8mV    985mV      668.1mV
149ps     704.4mV    873.8mV    619.1mV
181ps     611.3mV    708.5mV    587.5mV
216ps     577.7mV    614.8mV    579.2mV
332ps     563.1mV    556.4mV    576.7mV
[Rising Waveform]
R_fixture   = 50
V_fixture   = 1.1
V_fixture_min = 1.06
V_fixture_max = 1.17
|   Time   V(typ)   V(min)   V(max)
0s        562.8mV    553.9mV    576.6mV
57ps      559mV      549.8mV    590mV
66ps      568.8mV    547mV      640mV
79ps      633.7mV    560.8mV    785.9mV
91ps      744.4mV    616.5mV    892.7mV
109ps     874.4mV    756.8mV    997.7mV
126ps     952.2mV    859mV      1.06V
146ps     1.01V      934.9mV    1.105V
210ps     1.081V     1.032V     1.158V
332ps     1.099V     1.058V     1.169V
[Falling Waveform]
R_fixture = 50
V_fixture = 0.0
|   Time   V(typ)   V(min)   V(max)
0s        401.2mV    380.4mV    439.4mV
61ps      410.3mV    384.3mV    433.3mV
70ps      408.7mV    391.1mV    378.8mV
78ps      388.8mV    394mV      288.8mV
94ps      280.8mV    363.6mV    123.8mV
110ps     142.2mV    274.1mV    53.17mV
124ps     71.85mV    184.8mV    25.79mV
146ps     24.83mV    73.47mV    8.582mV
173ps     7.298mV    21.37mV    2.537mV
332ps     679.4uV    647.7uV    471uV
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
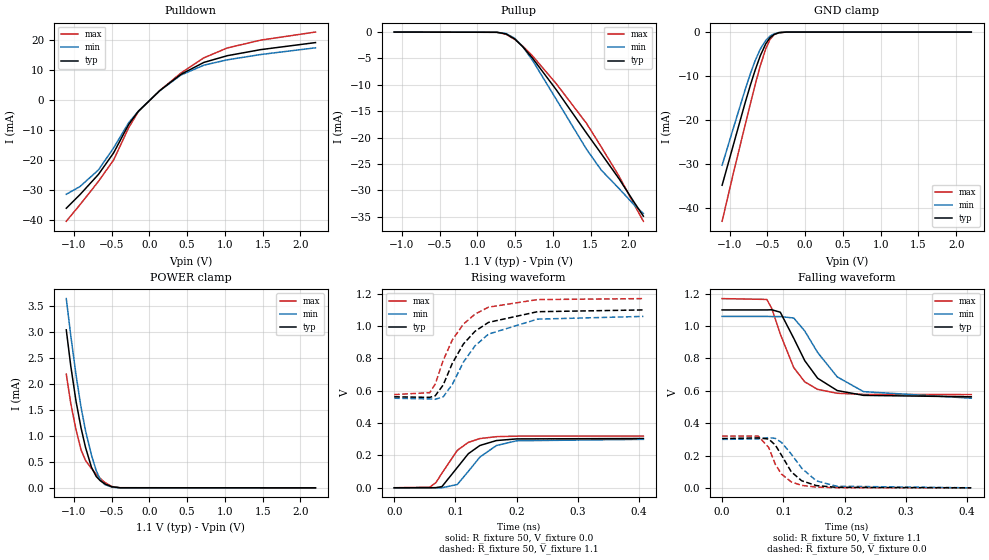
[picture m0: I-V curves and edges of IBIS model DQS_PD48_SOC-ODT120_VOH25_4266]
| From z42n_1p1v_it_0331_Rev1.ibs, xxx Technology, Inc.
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| DQS_PD48_SOC-ODT120_VOH25_4266
| (48 Ohm Pulldown, 120 Ohm System ODT Setting, VOH=VDDQ/2.5, 3200-4266Mbps)
[Model]   DQS_PD48_SOC-ODT120_VOH25_4266
Model_type   I/O
Vinl = 160.000mV
Vinh = 280.000mV
Vmeas = 220.000mV
Vref = 0.0mV
Cref = 0.0pF
Rref = 120.000Ohm
|   typ   min   max
|C_comp   0.849pF   0.799pF   0.899pF
C_comp_pullup   0.4245pF   0.3995pF   0.4495pF
C_comp_pulldown   0.4245pF   0.3995pF   0.4495pF
| Note: C_comp changes when the ODT circuit is enabled.
[Model Spec]
| Input threshold voltage corners
Vinl   0.1600V   0.1520V   0.1740V
Vinh   0.2800V   0.2720V   0.2940V
| Measurement voltage corners
Vmeas   0.2200V   0.2120V   0.2340V
| Timing spec test load voltage corners
Vref   0.0000V   0.0000V   0.0000V
| Dynamic Overshoot Parameters from LPDDR4 Specification
D_overshoot_ampl_h   0.30   NA   NA
D_overshoot_ampl_l   0.30   NA   NA
D_overshoot_area_h   0.1n   NA   NA
D_overshoot_area_l   0.1n   NA   NA
[Voltage Range]   1.1000V   1.0600V   1.1700V
[Pullup Reference]   1.1000V   1.0600V   1.1700V
| Junction Temperature (Ambient temp is 35C typ 95C min -40C max)
[Temperature Range]   50.0   110.0   -40.0
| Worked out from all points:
|   slope of the pulldown table from 0 to 0.165 V, typ, clamps not added: 43.9 ohm
|   slope of the pullup table from 0 to 0.165 V, typ, clamps not added: 26.1 kohm
|   GND clamp passes 1 mA (typ) near -0.45 V on its own axis
|   POWER clamp passes 1 mA (typ) near -0.88 V on its own axis
|   rising waveform, R_fixture 50, V_fixture 0.0: 20-80 % time 39.7ps typ, 43.1ps min, 36.3ps max; typ from 0 V to 0.305 V
|   falling waveform, R_fixture 50, V_fixture 1.1: 20-80 % time 49ps typ, 61.4ps min, 38.9ps max; typ from 1.1 V to 0.563 V
|   rising waveform, R_fixture 50, V_fixture 1.1: 20-80 % time 56.4ps typ, 60.4ps min, 51.9ps max; typ from 0.563 V to 1.1 V
|   falling waveform, R_fixture 50, V_fixture 0.0: 20-80 % time 32.3ps typ, 39.9ps min, 27ps max; typ from 0.305 V to 0 V
[Pulldown]
|   Voltage   I(typ)   I(min)   I(max)
-1.1V     -36.08mA   -31.42mA   -40.43mA
-918.5mV  -31.53mA   -28.84mA   -34.91mA
-674.3mV  -24.8mA    -23.31mA   -27.13mA
-473mV    -17.61mA   -15.94mA   -19.97mA
-275mV    -8.196mA   -7.612mA   -9.281mA
-146.3mV  -3.761mA   -3.702mA   -3.853mA
137.5mV   3.144mA    3.119mA    3.154mA
418mV     8.591mA    8.345mA    9.018mA
721.6mV   12.56mA    11.64mA    14.09mA
1.032V    14.81mA    13.43mA    17.39mA
1.474V    16.83mA    15.2mA     20mA
2.2V      19.18mA    17.44mA    22.7mA
[GND Clamp]
|   Voltage   I(typ)   I(min)   I(max)
-1.1V     -34.75mA   -30.21mA   -42.92mA
-938.3mV  -24.82mA   -21.07mA   -31.09mA
-793.1mV  -15.92mA   -12.96mA   -20.97mA
-723.8mV  -11.94mA   -9.346mA   -16.11mA
-664.4mV  -8.74mA    -6.576mA   -12.08mA
-595.1mV  -5.402mA   -3.898mA   -7.695mA
-522.5mV  -2.669mA   -1.902mA   -3.813mA
-466.4mV  -1.296mA   -942.3uA   -1.691mA
-413.6mV  -565.1uA   -417.6uA   -620uA
-347.6mV  -154.4uA   -117.6uA   -135.1uA
-251.9mV  -13.3uA    -11.88uA   -7.989uA
2.2V      0A         0A         0A
[Pullup]
|   Voltage   I(typ)   I(min)   I(max)
-1.1V     2.737uA    4.954uA    907.4nA
259.6mV   -40.66uA   -39.77uA   -41.09uA
381.7mV   -349uA     -290.3uA   -419.5uA
497.2mV   -1.326mA   -1.185mA   -1.397mA
602.8mV   -2.777mA   -2.764mA   -2.675mA
734.8mV   -4.997mA   -5.43mA    -4.571mA
1.045V    -10.91mA   -12.72mA   -9.76mA
1.448V    -19.17mA   -22.23mA   -17.33mA
1.642V    -23.05mA   -26.16mA   -21.76mA
1.877V    -27.79mA   -29.65mA   -27.3mA
2.094V    -32.61mA   -33.01mA   -33.1mA
2.2V      -34.89mA   -34.38mA   -35.86mA
[POWER Clamp]
|   Voltage   I(typ)   I(min)   I(max)
-1.1V     3.033mA    3.633mA    2.184mA
-1.041V   2.345mA    2.929mA    1.625mA
-971.3mV  1.665mA    2.173mA    1.116mA
-905.3mV  1.155mA    1.554mA    732uA
-845.9mV  780.1uA    1.103mA    527.5uA
-766.7mV  395uA      629.6uA    371.9uA
-704mV    219uA      331.9uA    262.1uA
-651.2mV  138.6uA    162.3uA    181.2uA
-591.8mV  77.91uA    64.84uA    105.5uA
-496.1mV  20.13uA    12.34uA    25.71uA
-390.5mV  2.048uA    1.391uA    1.763uA
2.2V      0A         0A         0A
[Ramp]
|   typ   min   max
| 20% - 80%
dV/dt_r   182.60m/39.72p   179.65m/43.11p   191.87m/36.32p
dV/dt_f   322.28m/49.00p   303.41m/61.36p   355.99m/38.85p
| 25% - 75%
|dV/dt_r   152.17m/31.66p   149.71m/34.40p   159.89m/28.85p
|dV/dt_f   268.56m/39.05p   252.84m/48.98p   296.66m/30.92p
R_load = 50
[Rising Waveform]
R_fixture = 50
V_fixture = 0.0
|   Time   V(typ)   V(min)   V(max)
0s        423.5uV    334.4uV    315uV
58ps      428.2uV    259.3uV    3.932mV
68ps      1.029mV    -125.7uV   31.86mV
78ps      7.536mV    288uV      90.21mV
103ps     125.2mV    20.48mV    231.4mV
121ps     210.6mV    101.3mV    280.9mV
140ps     261.9mV    190.2mV    304.6mV
167ps     292.3mV    261.4mV    316.3mV
200ps     302.4mV    291mV      319.5mV
407ps     304.8mV    299.7mV    320.1mV
[Falling Waveform]
R_fixture   = 50
V_fixture   = 1.1
V_fixture_min = 1.06
V_fixture_max = 1.17
|   Time   V(typ)   V(min)   V(max)
0s        1.1V       1.06V      1.17V
73ps      1.1V       1.06V      1.165V
81ps      1.101V     1.059V     1.11V
95ps      1.086V     1.059V     950.6mV
117ps     924.7mV    1.05V      743.5mV
135ps     786.2mV    969.6mV    655.3mV
156ps     677.8mV    837.1mV    608.8mV
188ps     601.7mV    686.1mV    584.9mV
231ps     571.9mV    595mV      578mV
407ps     562.9mV    554.3mV    576.7mV
[Rising Waveform]
R_fixture   = 50
V_fixture   = 1.1
V_fixture_min = 1.06
V_fixture_max = 1.17
|   Time   V(typ)   V(min)   V(max)
0s        562.8mV    553.9mV    576.6mV
58ps      559.3mV    549.7mV    588.2mV
67ps      569.1mV    547.4mV    641.4mV
80ps      635.8mV    562.1mV    788.1mV
95ps      770.6mV    639.9mV    914.7mV
113ps     889.1mV    776.7mV    1.012V
132ps     968mV      877.8mV    1.074V
154ps     1.023V     950.5mV    1.117V
234ps     1.089V     1.043V     1.164V
407ps     1.1V       1.06V      1.17V
[Falling Waveform]
R_fixture = 50
V_fixture = 0.0
|   Time   V(typ)   V(min)   V(max)
0s        304.8mV    299.8mV    320.2mV
59ps      309.2mV    302.8mV    320.3mV
76ps      302mV      311mV      249.8mV
87ps      264.4mV    305.9mV    144.9mV
97ps      202.2mV    281.1mV    84.92mV
113ps     99.29mV    209mV      36.79mV
130ps     43.96mV    121.5mV    15.45mV
154ps     14.13mV    43.32mV    4.789mV
187ps     3.405mV    10.31mV    1.198mV
407ps     483.7uV    422.1uV    337.3uV
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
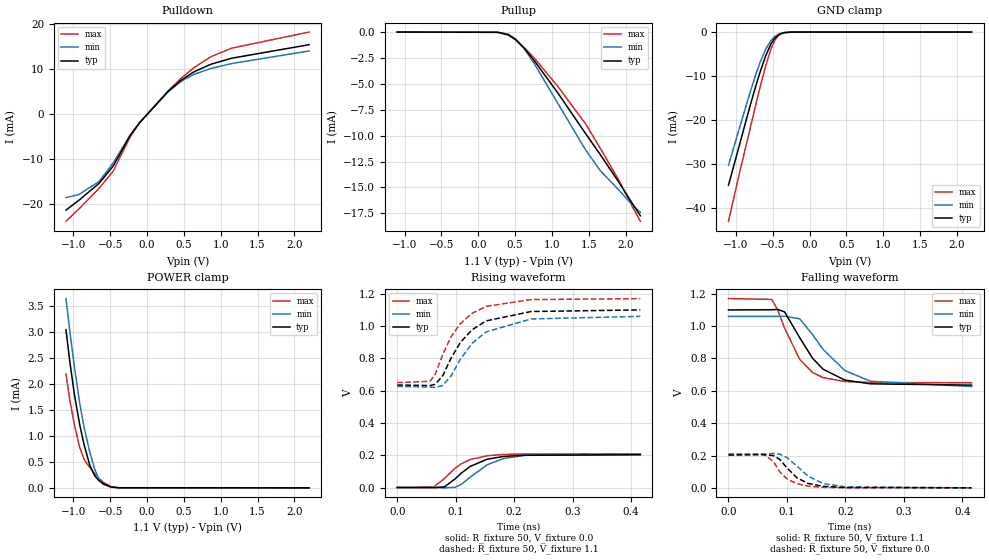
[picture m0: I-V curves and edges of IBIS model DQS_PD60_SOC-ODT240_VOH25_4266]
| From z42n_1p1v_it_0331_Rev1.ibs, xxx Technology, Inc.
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| DQS_PD60_SOC-ODT240_VOH25_4266
| (60 Ohm Pulldown, 240 Ohm System ODT Setting, VOH=VDDQ/2.5, 3200-4266Mbps)
[Model]   DQS_PD60_SOC-ODT240_VOH25_4266
Model_type   I/O
Vinl = 160.000mV
Vinh = 280.000mV
Vmeas = 220.000mV
Vref = 0.0mV
Cref = 0.0pF
Rref = 240.000Ohm
|   typ   min   max
|C_comp   0.849pF   0.799pF   0.899pF
C_comp_pullup   0.4245pF   0.3995pF   0.4495pF
C_comp_pulldown   0.4245pF   0.3995pF   0.4495pF
| Note: C_comp changes when the ODT circuit is enabled.
[Model Spec]
| Input threshold voltage corners
Vinl   0.1600V   0.1520V   0.1740V
Vinh   0.2800V   0.2720V   0.2940V
| Measurement voltage corners
Vmeas   0.2200V   0.2120V   0.2340V
| Timing spec test load voltage corners
Vref   0.0000V   0.0000V   0.0000V
| Dynamic Overshoot Parameters from LPDDR4 Specification
D_overshoot_ampl_h   0.30   NA   NA
D_overshoot_ampl_l   0.30   NA   NA
D_overshoot_area_h   0.1n   NA   NA
D_overshoot_area_l   0.1n   NA   NA
[Voltage Range]   1.1000V   1.0600V   1.1700V
[Pullup Reference]   1.1000V   1.0600V   1.1700V
| Junction Temperature (Ambient temp is 35C typ 95C min -40C max)
[Temperature Range]   50.0   110.0   -40.0
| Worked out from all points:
|   slope of the pulldown table from 0 to 0.165 V, typ, clamps not added: 55 ohm
|   slope of the pullup table from 0 to 0.165 V, typ, clamps not added: 53.5 kohm
|   GND clamp passes 1 mA (typ) near -0.45 V on its own axis
|   POWER clamp passes 1 mA (typ) near -0.88 V on its own axis
|   rising waveform, R_fixture 50, V_fixture 0.0: 20-80 % time 47.2ps typ, 51.2ps min, 43.6ps max; typ from 0 V to 0.203 V
|   falling waveform, R_fixture 50, V_fixture 1.1: 20-80 % time 53.4ps typ, 65.5ps min, 42.9ps max; typ from 1.1 V to 0.635 V
|   rising waveform, R_fixture 50, V_fixture 1.1: 20-80 % time 56.8ps typ, 61ps min, 52.1ps max; typ from 0.635 V to 1.1 V
|   falling waveform, R_fixture 50, V_fixture 0.0: 20-80 % time 35.3ps typ, 42.9ps min, 30.2ps max; typ from 0.203 V to 0 V
[Pulldown]
|   Voltage   I(typ)   I(min)   I(max)
-1.1V     -21.4mA    -18.63mA   -23.88mA
-918.5mV  -19.13mA   -17.9mA    -21.05mA
-647.9mV  -15.41mA   -14.98mA   -16.51mA
-459.8mV  -11.62mA   -10.92mA   -12.76mA
-225.5mV  -4.758mA   -4.636mA   -5.034mA
-103.4mV  -2.039mA   -2.035mA   -2.025mA
289.3mV   5.021mA    4.937mA    5.138mA
460.9mV   7.412mA    7.167mA    7.842mA
632.5mV   9.275mA    8.723mA    10.19mA
866.8mV   11mA       10.06mA    12.67mA
1.147V    12.33mA    11.15mA    14.56mA
2.2V      15.34mA    13.95mA    18.15mA
[GND Clamp]
|   Voltage   I(typ)   I(min)   I(max)
-1.1V     -34.75mA   -30.21mA   -42.92mA
-944.9mV  -25.23mA   -21.44mA   -31.56mA
-803mV    -16.51mA   -13.5mA    -21.66mA
-727.1mV  -12.12mA   -9.51mA    -16.34mA
-667.7mV  -8.911mA   -6.72mA    -12.3mA
-595.1mV  -5.401mA   -3.898mA   -7.695mA
-525.8mV  -2.767mA   -1.974mA   -3.966mA
-469.7mV  -1.358mA   -986.3uA   -1.789mA
-413.6mV  -565.6uA   -417.3uA   -621.2uA
-347.6mV  -155.1uA   -117.2uA   -135.5uA
-248.6mV  -12.13uA   -11uA      -7.061uA
2.2V      0A         0A         0A
[Pullup]
|   Voltage   I(typ)   I(min)   I(max)
-1.1V     1.369uA    2.477uA    453.9nA
266.2mV   -23.01uA   -22.27uA   -23.95uA
408.1mV   -253.8uA   -210.5uA   -297.2uA
510.4mV   -747.3uA   -678.1uA   -775.3uA
622.6mV   -1.559mA   -1.581mA   -1.482mA
757.9mV   -2.736mA   -3.014mA   -2.485mA
1.078V    -5.855mA   -6.856mA   -5.228mA
1.458V    -9.811mA   -11.39mA   -8.867mA
1.655V    -11.81mA   -13.36mA   -11.2mA
1.91V     -14.51mA   -15.26mA   -14.32mA
2.094V    -16.57mA   -16.71mA   -16.87mA
2.2V      -17.73mA   -17.39mA   -18.26mA
[POWER Clamp]
|   Voltage   I(typ)   I(min)   I(max)
-1.1V     3.033mA    3.633mA    2.184mA
-1.044V   2.381mA    2.967mA    1.653mA
-984.5mV  1.782mA    2.31mA     1.205mA
-915.2mV  1.224mA    1.639mA    781.4uA
-852.5mV  818.3uA    1.148mA    543.6uA
-776.6mV  434.1uA    683.3uA    390.2uA
-710.6mV  232.3uA    359uA      273.1uA
-657.8mV  146.8uA    178.8uA    190.6uA
-598.4mV  83.67uA    72uA       113uA
-492.8mV  18.89uA    11.53uA    24.09uA
-387.2mV  1.882uA    1.294uA    1.615uA
2.2V      0A         0A         0A
[Ramp]
|   typ   min   max
| 20% - 80%
dV/dt_r   121.52m/47.25p   123.82m/51.15p   125.30m/43.62p
dV/dt_f   278.91m/53.32p   260.06m/65.48p   312.07m/42.92p
| 25% - 75%
|dV/dt_r   101.26m/37.55p   103.18m/40.82p   104.42m/34.59p
|dV/dt_f   232.43m/42.44p   216.72m/52.27p   260.06m/34.20p
R_load = 50
[Rising Waveform]
R_fixture = 50
V_fixture = 0.0
|   Time   V(typ)   V(min)   V(max)
0s        234.1uV    177.4uV    177.6uV
62ps      -593.1uV   9.454uV    3.261mV
81ps      4.77mV     -1.721mV   56.61mV
99ps      53.72mV    1.519mV    120.1mV
110ps     90.59mV    20.52mV    147.8mV
125ps     131.2mV    64.71mV    173.2mV
154ps     175.6mV    141.2mV    197mV
182ps     192.8mV    180mV      204.9mV
219ps     200.2mV    199.5mV    208mV
416ps     202.8mV    206.5mV    209mV
[Falling Waveform]
R_fixture   = 50
V_fixture   = 1.1
V_fixture_min = 1.06
V_fixture_max = 1.17
|   Time   V(typ)   V(min)   V(max)
0s        1.1V       1.06V      1.17V
74ps      1.101V     1.06V      1.165V
84ps      1.103V     1.06V      1.101V
96ps      1.088V     1.061V     987.7mV
122ps     927.7mV    1.045V     793.3mV
144ps     800.8mV    946.6mV    712.8mV
162ps     733.2mV    855.4mV    681.4mV
199ps     666.4mV    725.4mV    657.5mV
243ps     643.2mV    659mV      651.3mV
416ps     635.1mV    626.6mV    649.9mV
[Rising Waveform]
R_fixture   = 50
V_fixture   = 1.1
V_fixture_min = 1.06
V_fixture_max = 1.17
|   Time   V(typ)   V(min)   V(max)
0s        635mV      626.1mV    649.8mV
56ps      631.7mV    622.4mV    657.7mV
65ps      639.1mV    619.9mV    700.5mV
78ps      693.4mV    631.8mV    824.9mV
92ps      800.8mV    690.5mV    932.5mV
108ps     898.4mV    794mV      1.015V
128ps     976.9mV    892.4mV    1.079V
152ps     1.032V     963.6mV    1.122V
229ps     1.09V      1.044V     1.164V
416ps     1.1V       1.06V      1.17V
[Falling Waveform]
R_fixture = 50
V_fixture = 0.0
|   Time   V(typ)   V(min)   V(max)
0s        202.8mV    206.6mV    209.1mV
60ps      205.1mV    208.4mV    208.2mV
77ps      199.5mV    212.5mV    161.9mV
88ps      175.1mV    208.1mV    98.55mV
100ps     124.5mV    187.1mV    56.07mV
117ps     61.98mV    135.2mV    25.6mV
136ps     27.58mV    72.74mV    10.75mV
162ps     9.293mV    26.54mV    3.387mV
199ps     2.194mV    6.362mV    796.2uV
416ps     299.1uV    271.8uV    197.2uV
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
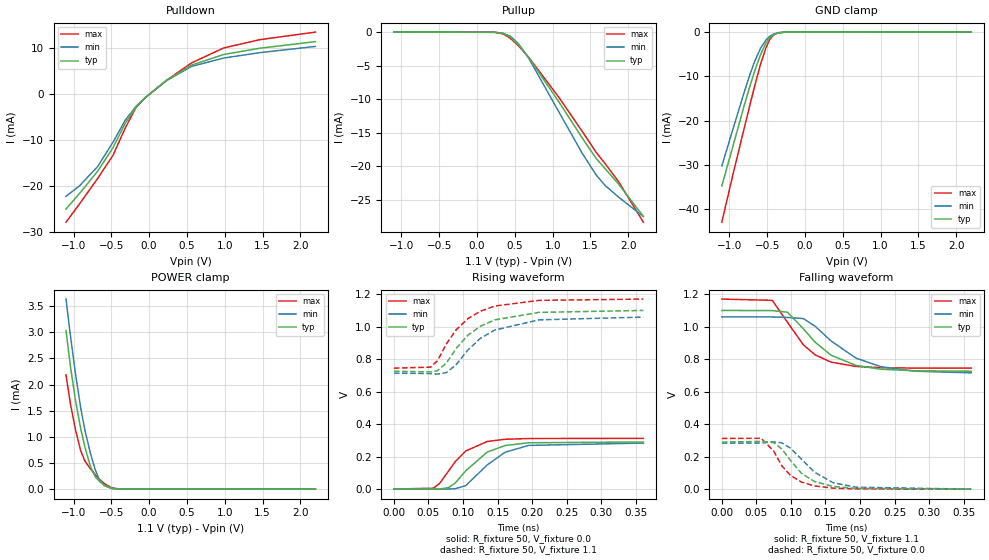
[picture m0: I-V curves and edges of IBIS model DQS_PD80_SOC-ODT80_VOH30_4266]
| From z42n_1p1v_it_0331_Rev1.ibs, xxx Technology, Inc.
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| DQS_PD80_SOC-ODT80_VOH30_4266
| (80 Ohm Pulldown, 80 Ohm System ODT Setting, VOH=VDDQ/3.0, 3200-4266Mbps)
[Model]   DQS_PD80_SOC-ODT80_VOH30_4266
Model_type   I/O
Vinl = 123.333mV
Vinh = 243.333mV
Vmeas = 183.333mV
Vref = 0.0mV
Cref = 0.0pF
Rref = 80.000Ohm
|   typ   min   max
|C_comp   0.849pF   0.799pF   0.899pF
C_comp_pullup   0.4245pF   0.3995pF   0.4495pF
C_comp_pulldown   0.4245pF   0.3995pF   0.4495pF
| Note: C_comp changes when the ODT circuit is enabled.
[Model Spec]
| Input threshold voltage corners
Vinl   0.1233V   0.1167V   0.1350V
Vinh   0.2433V   0.2367V   0.2550V
| Measurement voltage corners
Vmeas   0.1833V   0.1767V   0.1950V
| Timing spec test load voltage corners
Vref   0.0000V   0.0000V   0.0000V
| Dynamic Overshoot Parameters from LPDDR4 Specification
D_overshoot_ampl_h   0.30   NA   NA
D_overshoot_ampl_l   0.30   NA   NA
D_overshoot_area_h   0.1n   NA   NA
D_overshoot_area_l   0.1n   NA   NA
[Voltage Range]   1.1000V   1.0600V   1.1700V
[Pullup Reference]   1.1000V   1.0600V   1.1700V
| Junction Temperature (Ambient temp is 35C typ 95C min -40C max)
[Temperature Range]   50.0   110.0   -40.0
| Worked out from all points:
|   slope of the pulldown table from 0 to 0.165 V, typ, clamps not added: 74.3 ohm
|   slope of the pullup table from 0 to 0.165 V, typ, clamps not added: 26.2 kohm
|   GND clamp passes 1 mA (typ) near -0.45 V on its own axis
|   POWER clamp passes 1 mA (typ) near -0.88 V on its own axis
|   rising waveform, R_fixture 50, V_fixture 0.0: 20-80 % time 43.5ps typ, 46.6ps min, 37.8ps max; typ from 0 V to 0.29 V
|   falling waveform, R_fixture 50, V_fixture 1.1: 20-80 % time 57.4ps typ, 67.8ps min, 46.9ps max; typ from 1.1 V to 0.726 V
|   rising waveform, R_fixture 50, V_fixture 1.1: 20-80 % time 55.6ps typ, 58.7ps min, 52.3ps max; typ from 0.726 V to 1.1 V
|   falling waveform, R_fixture 50, V_fixture 0.0: 20-80 % time 38.6ps typ, 45.5ps min, 33.7ps max; typ from 0.29 V to 0 V
[Pulldown]
|   Voltage   I(typ)   I(min)   I(max)
-1.1V     -25.08mA   -22.32mA   -27.96mA
-921.8mV  -21.71mA   -20.02mA   -23.98mA
-680.9mV  -16.81mA   -15.79mA   -18.39mA
-479.6mV  -11.73mA   -10.53mA   -13.39mA
-314.6mV  -6.262mA   -5.631mA   -7.332mA
-176mV    -2.798mA   -2.711mA   -2.967mA
-53.9mV   -796.8uA   -791.5uA   -782.7uA
226.6mV   2.973mA    2.94mA     3.003mA
563.2mV   6.372mA    6.084mA    6.856mA
988.9mV   8.691mA    7.907mA    10.12mA
1.467V    10.05mA    9.085mA    11.92mA
2.2V      11.48mA    10.44mA    13.57mA
[GND Clamp]
|   Voltage   I(typ)   I(min)   I(max)
-1.1V     -34.74mA   -30.21mA   -42.91mA
-944.9mV  -25.23mA   -21.44mA   -31.55mA
-799.7mV  -16.31mA   -13.32mA   -21.42mA
-720.5mV  -11.75mA   -9.185mA   -15.87mA
-661.1mV  -8.566mA   -6.435mA   -11.85mA
-588.5mV  -5.113mA   -3.681mA   -7.3mA
-519.2mV  -2.565mA   -1.833mA   -3.661mA
-466.4mV  -1.294mA   -943.4uA   -1.691mA
-413.6mV  -567.7uA   -417uA     -621.1uA
-357.5mV  -192.6uA   -144.7uA   -173.7uA
-265.1mV  -19.41uA   -16.9uA    -12.33uA
2.2V      0A         0A         0A
[Pullup]
|   Voltage   I(typ)   I(min)   I(max)
-1.1V     3.138uA    4.837uA    1.415uA
233.2mV   -24.3uA    -24.32uA   -25.33uA
342.1mV   -190.4uA   -158.1uA   -262.8uA
434.5mV   -693.8uA   -568.6uA   -877.5uA
546.7mV   -1.865mA   -1.708mA   -2.036mA
682mV     -3.775mA   -3.872mA   -3.748mA
1.081V    -10.39mA   -11.89mA   -9.715mA
1.395V    -15.87mA   -18.16mA   -14.89mA
1.576V    -18.87mA   -21.34mA   -17.96mA
1.695V    -20.39mA   -22.9mA    -19.65mA
1.87V     -22.66mA   -24.62mA   -22.29mA
2.2V      -27.52mA   -27.53mA   -28.38mA
[POWER Clamp]
|   Voltage   I(typ)   I(min)   I(max)
-1.1V     3.033mA    3.633mA    2.184mA
-1.041V   2.345mA    2.929mA    1.625mA
-974.6mV  1.694mA    2.207mA    1.138mA
-905.3mV  1.155mA    1.553mA    732.1uA
-849.2mV  799.4uA    1.125mA    535.4uA
-776.6mV  434.2uA    683.2uA    390.2uA
-710.6mV  232.2uA    359.1uA    273.1uA
-654.5mV  142.7uA    170.4uA    185.9uA
-591.8mV  77.97uA    64.82uA    105.5uA
-492.8mV  18.97uA    11.55uA    24.06uA
-383.9mV  1.754uA    1.218uA    1.467uA
2.2V      0A         0A         0A
[Ramp]
|   typ   min   max
| 20% - 80%
dV/dt_r   173.87m/43.51p   169.82m/46.65p   187.27m/37.77p
dV/dt_f   224.44m/57.52p   206.41m/67.82p   255.15m/46.95p
| 25% - 75%
|dV/dt_r   144.89m/34.64p   141.51m/37.20p   156.06m/30.01p
|dV/dt_f   187.03m/45.74p   172.01m/54.03p   212.63m/37.34p
R_load = 50
[Rising Waveform]
R_fixture = 50
V_fixture = 0.0
|   Time   V(typ)   V(min)   V(max)
0s        398.4uV    340.6uV    291.9uV
57ps      -10.49uV   112.5uV    5.384mV
66ps      818uV      -369.9uV   34.17mV
79ps      8.858mV    423.9uV    111.2mV
89ps      38.81mV    2.649mV    170.6mV
104ps     112.8mV    21.69mV    234.8mV
135ps     228.2mV    148.6mV    293.1mV
161ps     268.4mV    227.2mV    306.8mV
195ps     285.3mV    269mV      311.4mV
361ps     290.2mV    283.4mV    312.4mV
[Falling Waveform]
R_fixture   = 50
V_fixture   = 1.1
V_fixture_min = 1.06
V_fixture_max = 1.17
|   Time   V(typ)   V(min)   V(max)
0s        1.1V       1.06V      1.17V
73ps      1.099V     1.06V      1.162V
95ps      1.089V     1.057V     1.027V
118ps     987.1mV    1.05V      888.3mV
135ps     904.7mV    1.003V     826.9mV
158ps     824.7mV    912.4mV    782mV
194ps     762mV      806.9mV    755.4mV
230ps     738.4mV    754.1mV    747.7mV
280ps     728.7mV    726mV      745.2mV
361ps     725.9mV    716mV      744.8mV
[Rising Waveform]
R_fixture   = 50
V_fixture   = 1.1
V_fixture_min = 1.06
V_fixture_max = 1.17
|   Time   V(typ)   V(min)   V(max)
0s        725.5mV    714.2mV    744.7mV
53ps      721.8mV    711mV      750.9mV
63ps      729.1mV    707.9mV    790.9mV
76ps      776.6mV    717.5mV    893.9mV
90ps      865.2mV    765.7mV    980.3mV
107ps     947.2mV    856.3mV    1.049V
125ps     1.002V     927.6mV    1.095V
146ps     1.042V     979.3mV    1.127V
210ps     1.088V     1.042V     1.162V
361ps     1.1V       1.059V     1.17V
[Falling Waveform]
R_fixture = 50
V_fixture = 0.0
|   Time   V(typ)   V(min)   V(max)
0s        290.3mV    283.5mV    312.5mV
57ps      294.2mV    284.3mV    313.4mV
75ps      287.3mV    291.6mV    234.8mV
87ps      247.2mV    285mV      143.1mV
99ps      179.7mV    253.8mV    86.35mV
115ps     98.94mV    185.7mV    44.5mV
134ps     47.55mV    105mV      20.35mV
161ps     17.01mV    40.04mV    6.925mV
194ps     5.181mV    12.39mV    2.028mV
361ps     492.5uV    491.9uV    322.6uV
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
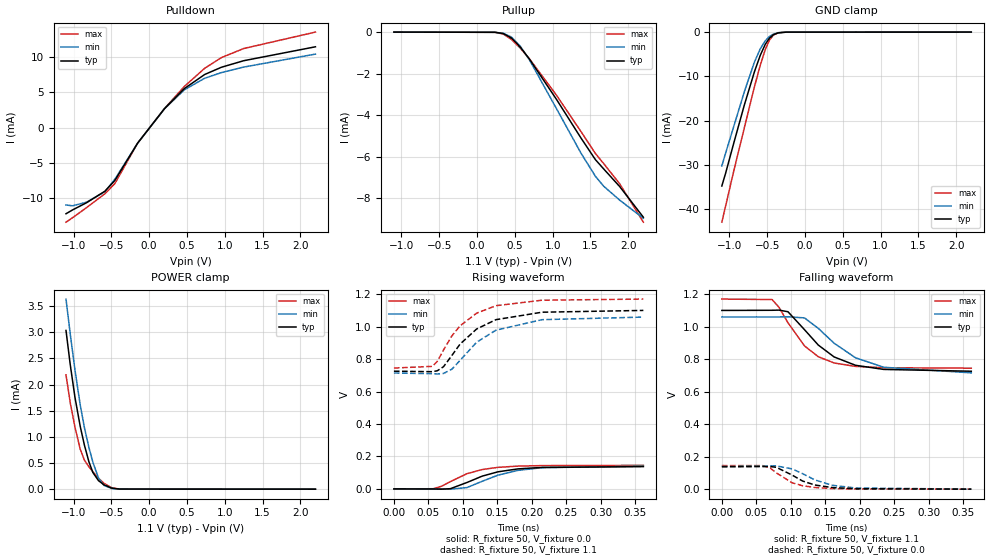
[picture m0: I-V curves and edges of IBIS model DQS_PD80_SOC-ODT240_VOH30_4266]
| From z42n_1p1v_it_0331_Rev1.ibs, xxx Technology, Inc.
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| DQS_PD80_SOC-ODT240_VOH30_4266
| (80 Ohm Pulldown, 240 Ohm System ODT Setting, VOH=VDDQ/3.0, 3200-4266Mbps)
[Model]   DQS_PD80_SOC-ODT240_VOH30_4266
Model_type   I/O
Vinl = 123.333mV
Vinh = 243.333mV
Vmeas = 183.333mV
Vref = 0.0mV
Cref = 0.0pF
Rref = 240.000Ohm
|   typ   min   max
|C_comp   0.849pF   0.799pF   0.899pF
C_comp_pullup   0.4245pF   0.3995pF   0.4495pF
C_comp_pulldown   0.4245pF   0.3995pF   0.4495pF
| Note: C_comp changes when the ODT circuit is enabled.
[Model Spec]
| Input threshold voltage corners
Vinl   0.1233V   0.1167V   0.1350V
Vinh   0.2433V   0.2367V   0.2550V
| Measurement voltage corners
Vmeas   0.1833V   0.1767V   0.1950V
| Timing spec test load voltage corners
Vref   0.0000V   0.0000V   0.0000V
| Dynamic Overshoot Parameters from LPDDR4 Specification
D_overshoot_ampl_h   0.30   NA   NA
D_overshoot_ampl_l   0.30   NA   NA
D_overshoot_area_h   0.1n   NA   NA
D_overshoot_area_l   0.1n   NA   NA
[Voltage Range]   1.1000V   1.0600V   1.1700V
[Pullup Reference]   1.1000V   1.0600V   1.1700V
| Junction Temperature (Ambient temp is 35C typ 95C min -40C max)
[Temperature Range]   50.0   110.0   -40.0
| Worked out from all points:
|   slope of the pulldown table from 0 to 0.165 V, typ, clamps not added: 74.6 ohm
|   slope of the pullup table from 0 to 0.165 V, typ, clamps not added: 79 kohm
|   GND clamp passes 1 mA (typ) near -0.45 V on its own axis
|   POWER clamp passes 1 mA (typ) near -0.88 V on its own axis
|   rising waveform, R_fixture 50, V_fixture 0.0: 20-80 % time 56.4ps typ, 58.8ps min, 49.1ps max; typ from 0 V to 0.137 V
|   falling waveform, R_fixture 50, V_fixture 1.1: 20-80 % time 57ps typ, 67.1ps min, 46.6ps max; typ from 1.1 V to 0.726 V
|   rising waveform, R_fixture 50, V_fixture 1.1: 20-80 % time 56.3ps typ, 60.5ps min, 52.1ps max; typ from 0.726 V to 1.1 V
|   falling waveform, R_fixture 50, V_fixture 0.0: 20-80 % time 39.1ps typ, 46.6ps min, 34.6ps max; typ from 0.137 V to 0 V
[Pulldown]
|   Voltage   I(typ)   I(min)   I(max)
-1.1V     -12.26mA   -11.01mA   -13.46mA
-1.014V   -11.72mA   -11.13mA   -12.83mA
-829.4mV  -10.7mA    -10.62mA   -11.4mA
-585.2mV  -9.054mA   -9.117mA   -9.415mA
-453.2mV  -7.519mA   -7.349mA   -7.968mA
-152.9mV  -2.228mA   -2.23mA    -2.227mA
203.5mV   2.691mA    2.665mA    2.709mA
467.5mV   5.553mA    5.379mA    5.855mA
734.8mV   7.541mA    7.005mA    8.425mA
955.9mV   8.569mA    7.808mA    9.942mA
1.25V     9.498mA    8.593mA    11.23mA
2.2V      11.48mA    10.44mA    13.57mA
[GND Clamp]
|   Voltage   I(typ)   I(min)   I(max)
-1.1V     -34.74mA   -30.21mA   -42.91mA
-1.05V    -31.86mA   -27.33mA   -39.27mA
-944.9mV  -25.23mA   -21.44mA   -31.55mA
-799.7mV  -16.31mA   -13.32mA   -21.42mA
-667.7mV  -8.907mA   -6.722mA   -12.29mA
-591.8mV  -5.255mA   -3.789mA   -7.492mA
-525.8mV  -2.77mA    -1.975mA   -3.963mA
-469.7mV  -1.356mA   -986.5uA   -1.787mA
-416.9mV  -598.6uA   -440.6uA   -664.6uA
-354.2mV  -179.4uA   -134.6uA   -160.3uA
-248.6mV  -12.13uA   -10.94uA   -7.108uA
2.2V      0A         0A         0A
[Pullup]
|   Voltage   I(typ)   I(min)   I(max)
-1.1V     1.046uA    1.612uA    471.3nA
236.5mV   -8.648uA   -8.621uA   -9.171uA
345.4mV   -66.92uA   -55.08uA   -92.21uA
454.3mV   -284.8uA   -236.7uA   -349.7uA
569.8mV   -713.8uA   -668.3uA   -763.3uA
695.2mV   -1.311mA   -1.351mA   -1.297mA
1.052V    -3.249mA   -3.698mA   -3.047mA
1.375V    -5.105mA   -5.833mA   -4.795mA
1.566V    -6.147mA   -6.95mA    -5.851mA
1.675V    -6.593mA   -7.426mA   -6.335mA
1.887V    -7.444mA   -8.098mA   -7.311mA
2.2V      -8.921mA   -8.97mA    -9.16mA
[POWER Clamp]
|   Voltage   I(typ)   I(min)   I(max)
-1.1V     3.033mA    3.633mA    2.184mA
-1.044V   2.381mA    2.967mA    1.653mA
-981.2mV  1.753mA    2.276mA    1.183mA
-911.9mV  1.201mA    1.61mA     764.6uA
-855.8mV  837.8uA    1.172mA    552.1uA
-796.4mV  521.2uA    794.7uA    427.2uA
-743.6mV  315.8uA    510.8uA    330.1uA
-671mV    164.5uA    216uA      210.1uA
-598.4mV  83.64uA    71.96uA    113uA
-492.8mV  18.89uA    11.54uA    24.03uA
-387.2mV  1.892uA    1.295uA    1.644uA
2.2V      0A         0A         0A
[Ramp]
|   typ   min   max
| 20% - 80%
dV/dt_r   82.33m/56.44p   84.05m/58.84p   87.12m/49.14p
dV/dt_f   224.45m/56.99p   206.39m/67.10p   255.14m/46.63p
| 25% - 75%
|dV/dt_r   68.61m/44.91p   70.04m/46.91p   72.60m/38.97p
|dV/dt_f   187.04m/45.37p   171.99m/53.48p   212.61m/37.05p
R_load = 50
[Rising Waveform]
R_fixture = 50
V_fixture = 0.0
|   Time   V(typ)   V(min)   V(max)
0s        121.8uV    91.42uV    94.29uV
57ps      -334uV     219.7uV    1.056mV
69ps      -1.57mV    -509.4uV   16.14mV
82ps      1.431mV    -1.454mV   45.18mV
106ps     39.55mV    8.234mV    93.91mV
128ps     78.59mV    46.74mV    119.3mV
151ps     105.4mV    84.79mV    132.9mV
180ps     123.4mV    114.3mV    140.5mV
215ps     132.5mV    130.7mV    143.7mV
362ps     137.3mV    140.2mV    145.3mV
[Falling Waveform]
R_fixture   = 50
V_fixture   = 1.1
V_fixture_min = 1.06
V_fixture_max = 1.17
|   Time   V(typ)   V(min)   V(max)
0s        1.1V       1.06V      1.17V
73ps      1.101V     1.06V      1.167V
83ps      1.102V     1.06V      1.119V
96ps      1.092V     1.061V     1.024V
120ps     981.4mV    1.054V     881.6mV
140ps     886.9mV    989.7mV    815.1mV
163ps     813.7mV    898mV      776.6mV
194ps     762.5mV    808.7mV    755.6mV
235ps     737mV      750.3mV    747.4mV
362ps     725.9mV    716mV      744.8mV
[Rising Waveform]
R_fixture   = 50
V_fixture   = 1.1
V_fixture_min = 1.06
V_fixture_max = 1.17
|   Time   V(typ)   V(min)   V(max)
0s        725.5mV    714.2mV    744.7mV
56ps      722.4mV    710.1mV    755.3mV
63ps      728.2mV    708.3mV    786.1mV
72ps      753.3mV    711.5mV    856.1mV
84ps      821.6mV    737.3mV    942.6mV
96ps      892.6mV    792.1mV    1.005V
120ps     985.4mV    904mV      1.083V
148ps     1.043V     978.2mV    1.129V
215ps     1.089V     1.043V     1.163V
362ps     1.1V       1.059V     1.17V
[Falling Waveform]
R_fixture = 50
V_fixture = 0.0
|   Time   V(typ)   V(min)   V(max)
0s        137.5mV    140.4mV    145.3mV
59ps      139.2mV    141.2mV    145.2mV
70ps      139.3mV    143mV      130.7mV
79ps      134.8mV    143.4mV    100.6mV
102ps     86.84mV    124.7mV    39.43mV
117ps     50.47mV    95.84mV    21.48mV
135ps     25.72mV    57.07mV    10.37mV
160ps     10.12mV    24.2mV     3.843mV
194ps     2.955mV    7.425mV    1.053mV
362ps     195.5uV    217.2uV    117.7uV
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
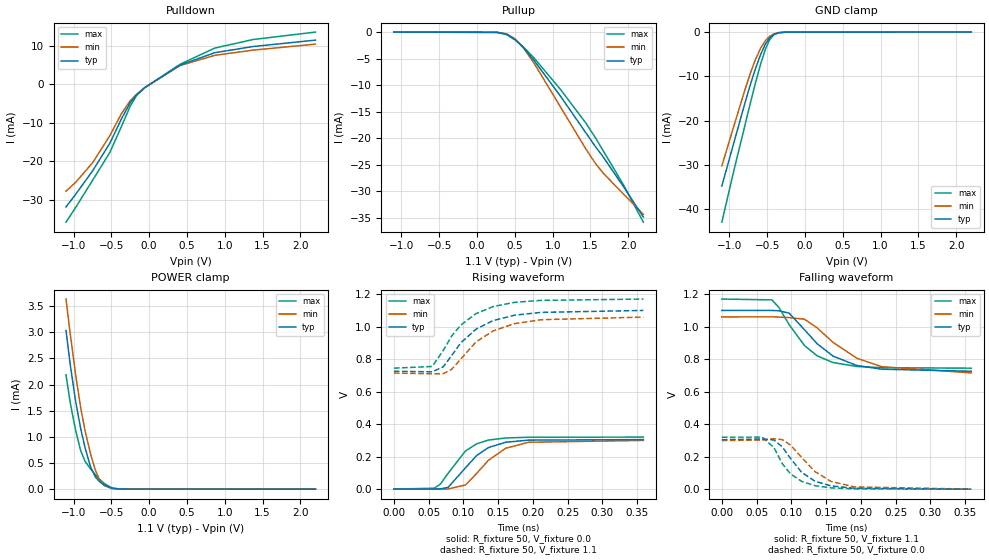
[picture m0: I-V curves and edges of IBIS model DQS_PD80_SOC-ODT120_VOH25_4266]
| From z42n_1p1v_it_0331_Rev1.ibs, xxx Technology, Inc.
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| DQS_PD80_SOC-ODT120_VOH25_4266
| (80 Ohm Pulldown, 120 Ohm System ODT Setting, VOH=VDDQ/2.5, 3200-4266Mbps)
[Model]   DQS_PD80_SOC-ODT120_VOH25_4266
Model_type   I/O
Vinl = 160.000mV
Vinh = 280.000mV
Vmeas = 220.000mV
Vref = 0.0mV
Cref = 0.0pF
Rref = 120.000Ohm
|   typ   min   max
|C_comp   0.849pF   0.799pF   0.899pF
C_comp_pullup   0.4245pF   0.3995pF   0.4495pF
C_comp_pulldown   0.4245pF   0.3995pF   0.4495pF
| Note: C_comp changes when the ODT circuit is enabled.
[Model Spec]
| Input threshold voltage corners
Vinl   0.1600V   0.1520V   0.1740V
Vinh   0.2800V   0.2720V   0.2940V
| Measurement voltage corners
Vmeas   0.2200V   0.2120V   0.2340V
| Timing spec test load voltage corners
Vref   0.0000V   0.0000V   0.0000V
| Dynamic Overshoot Parameters from LPDDR4 Specification
D_overshoot_ampl_h   0.30   NA   NA
D_overshoot_ampl_l   0.30   NA   NA
D_overshoot_area_h   0.1n   NA   NA
D_overshoot_area_l   0.1n   NA   NA
[Voltage Range]   1.1000V   1.0600V   1.1700V
[Pullup Reference]   1.1000V   1.0600V   1.1700V
| Junction Temperature (Ambient temp is 35C typ 95C min -40C max)
[Temperature Range]   50.0   110.0   -40.0
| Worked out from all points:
|   slope of the pulldown table from 0 to 0.165 V, typ, clamps not added: 74.1 ohm
|   slope of the pullup table from 0 to 0.165 V, typ, clamps not added: 26.7 kohm
|   GND clamp passes 1 mA (typ) near -0.45 V on its own axis
|   POWER clamp passes 1 mA (typ) near -0.88 V on its own axis
|   rising waveform, R_fixture 50, V_fixture 0.0: 20-80 % time 40.1ps typ, 43.7ps min, 36.6ps max; typ from 0.001 V to 0.305 V
|   falling waveform, R_fixture 50, V_fixture 1.1: 20-80 % time 57.5ps typ, 68.2ps min, 46.9ps max; typ from 1.1 V to 0.726 V
|   rising waveform, R_fixture 50, V_fixture 1.1: 20-80 % time 55.8ps typ, 58.5ps min, 51.8ps max; typ from 0.726 V to 1.1 V
|   falling waveform, R_fixture 50, V_fixture 0.0: 20-80 % time 38.3ps typ, 44.7ps min, 33ps max; typ from 0.305 V to 0.001 V
[Pulldown]
|   Voltage   I(typ)   I(min)   I(max)
-1.1V     -31.87mA   -27.77mA   -35.84mA
-971.3mV  -28.56mA   -25.46mA   -31.97mA
-746.9mV  -22.46mA   -20.36mA   -24.91mA
-519.2mV  -15.29mA   -13.32mA   -17.67mA
-364.1mV  -8.901mA   -7.554mA   -10.86mA
-251.9mV  -4.82mA    -4.32mA    -5.727mA
-169.4mV  -2.779mA   -2.649mA   -2.998mA
-57.2mV   -861uA     -849.3uA   -847.8uA
408.1mV   4.985mA    4.862mA    5.192mA
866.8mV   8.205mA    7.518mA    9.402mA
1.372V    9.814mA    8.875mA    11.63mA
2.2V      11.48mA    10.44mA    13.57mA
[GND Clamp]
|   Voltage   I(typ)   I(min)   I(max)
-1.1V     -34.75mA   -30.21mA   -42.92mA
-941.6mV  -25.02mA   -21.25mA   -31.33mA
-789.8mV  -15.73mA   -12.78mA   -20.73mA
-720.5mV  -11.75mA   -9.183mA   -15.88mA
-661.1mV  -8.569mA   -6.433mA   -11.86mA
-588.5mV  -5.114mA   -3.68mA    -7.305mA
-522.5mV  -2.665mA   -1.902mA   -3.814mA
-469.7mV  -1.357mA   -985.9uA   -1.787mA
-413.6mV  -564.5uA   -416.6uA   -620.8uA
-350.9mV  -165.9uA   -125.7uA   -147.1uA
-255.2mV  -14.69uA   -13.01uA   -8.992uA
2.2V      0A         0A         0A
[Pullup]
|   Voltage   I(typ)   I(min)   I(max)
-1.1V     2.737uA    4.953uA    907.4nA
266.2mV   -46.04uA   -44.63uA   -47.87uA
391.6mV   -402.8uA   -334uA     -480uA
507.1mV   -1.444mA   -1.304mA   -1.505mA
609.4mV   -2.88mA    -2.883mA   -2.763mA
748mV     -5.234mA   -5.723mA   -4.774mA
1.108V    -12.17mA   -14.22mA   -10.89mA
1.441V    -19.03mA   -22.09mA   -17.2mA
1.566V    -21.6mA    -24.77mA   -19.93mA
1.665V    -23.48mA   -26.54mA   -22.29mA
1.933V    -29.06mA   -30.5mA    -28.72mA
2.2V      -34.89mA   -34.38mA   -35.86mA
[POWER Clamp]
|   Voltage   I(typ)   I(min)   I(max)
-1.1V     3.033mA    3.633mA    2.184mA
-1.044V   2.381mA    2.967mA    1.653mA
-971.3mV  1.665mA    2.173mA    1.116mA
-905.3mV  1.155mA    1.554mA    732.5uA
-845.9mV  780uA      1.103mA    527.7uA
-773.3mV  420.8uA    665.3uA    384.1uA
-710.6mV  232.3uA    359uA      273.1uA
-657.8mV  146.8uA    178.8uA    190.6uA
-595.1mV  80.74uA    68.28uA    109.2uA
-496.1mV  20.1uA     12.31uA    25.72uA
-390.5mV  2.042uA    1.387uA    1.76uA
2.2V      0A         0A         0A
[Ramp]
|   typ   min   max
| 20% - 80%
dV/dt_r   182.52m/40.06p   179.58m/43.69p   191.81m/36.56p
dV/dt_f   224.44m/57.53p   206.39m/68.19p   255.15m/46.91p
| 25% - 75%
|dV/dt_r   152.10m/31.90p   149.65m/34.78p   159.84m/29.08p
|dV/dt_f   187.03m/45.78p   172.00m/54.30p   212.62m/37.30p
R_load = 50
[Rising Waveform]
R_fixture = 50
V_fixture = 0.0
|   Time   V(typ)   V(min)   V(max)
0s        555.6uV    449.6uV    409.6uV
58ps      269uV      11.26uV    5.259mV
67ps      1.817mV    -322.2uV   31.66mV
78ps      10.8mV     1.026mV    97.67mV
103ps     131.1mV    25.55mV    234.8mV
119ps     206.6mV    96.12mV    278.6mV
136ps     255.7mV    177.4mV    301.9mV
161ps     288.7mV    251.9mV    315mV
194ps     301.6mV    288.4mV    319.2mV
359ps     304.8mV    299.7mV    320.1mV
[Falling Waveform]
R_fixture   = 50
V_fixture   = 1.1
V_fixture_min = 1.06
V_fixture_max = 1.17
|   Time   V(typ)   V(min)   V(max)
0s        1.1V       1.06V      1.17V
72ps      1.1V       1.061V     1.165V
82ps      1.098V     1.059V     1.119V
97ps      1.083V     1.056V     1.012V
119ps     981.2mV    1.046V     883.6mV
137ps     895.7mV    993.3mV    821.3mV
160ps     819.2mV    903.8mV    779.4mV
194ps     761.7mV    806.5mV    755.3mV
230ps     738.5mV    754mV      747.8mV
359ps     725.9mV    716mV      744.8mV
[Rising Waveform]
R_fixture   = 50
V_fixture   = 1.1
V_fixture_min = 1.06
V_fixture_max = 1.17
|   Time   V(typ)   V(min)   V(max)
0s        725.5mV    714.2mV    744.7mV
55ps      722.1mV    710mV      755mV
71ps      752.9mV    710.8mV    853.4mV
83ps      821.4mV    737.3mV    941.8mV
96ps      899.2mV    799.3mV    1.009V
118ps     984.3mV    905.8mV    1.08V
143ps     1.038V     974.6mV    1.124V
174ps     1.071V     1.019V     1.15V
212ps     1.088V     1.043V     1.162V
359ps     1.1V       1.059V     1.17V
[Falling Waveform]
R_fixture = 50
V_fixture = 0.0
|   Time   V(typ)   V(min)   V(max)
0s        304.9mV    299.8mV    320.2mV
58ps      309mV      302.4mV    320.6mV
75ps      302.6mV    311mV      256.2mV
87ps      260.8mV    305.3mV    157.3mV
99ps      188.6mV    271.2mV    93.96mV
115ps     103.4mV    195mV      48.15mV
134ps     49.51mV    109mV      21.94mV
157ps     20.59mV    47.97mV    8.673mV
191ps     6.007mV    14.36mV    2.465mV
359ps     638.1uV    591.1uV    441.7uV
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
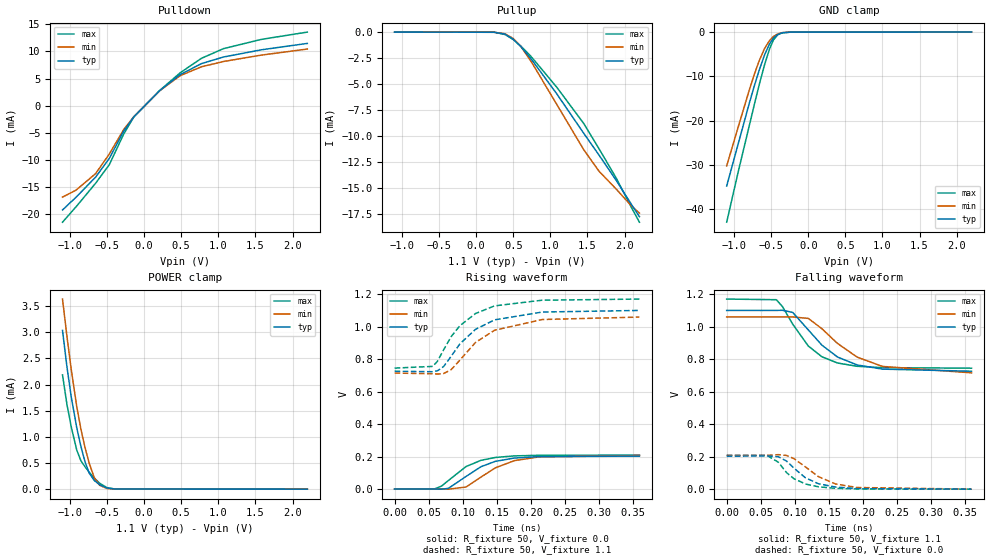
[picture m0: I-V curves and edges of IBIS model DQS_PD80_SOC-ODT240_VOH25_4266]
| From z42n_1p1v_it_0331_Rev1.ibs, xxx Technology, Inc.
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| DQS_PD80_SOC-ODT240_VOH25_4266
| (80 Ohm Pulldown, 240 Ohm System ODT Setting, VOH=VDDQ/2.5, 3200-4266Mbps)
[Model]   DQS_PD80_SOC-ODT240_VOH25_4266
Model_type   I/O
Vinl = 160.000mV
Vinh = 280.000mV
Vmeas = 220.000mV
Vref = 0.0mV
Cref = 0.0pF
Rref = 240.000Ohm
|   typ   min   max
|C_comp   0.849pF   0.799pF   0.899pF
C_comp_pullup   0.4245pF   0.3995pF   0.4495pF
C_comp_pulldown   0.4245pF   0.3995pF   0.4495pF
| Note: C_comp changes when the ODT circuit is enabled.
[Model Spec]
| Input threshold voltage corners
Vinl   0.1600V   0.1520V   0.1740V
Vinh   0.2800V   0.2720V   0.2940V
| Measurement voltage corners
Vmeas   0.2200V   0.2120V   0.2340V
| Timing spec test load voltage corners
Vref   0.0000V   0.0000V   0.0000V
| Dynamic Overshoot Parameters from LPDDR4 Specification
D_overshoot_ampl_h   0.30   NA   NA
D_overshoot_ampl_l   0.30   NA   NA
D_overshoot_area_h   0.1n   NA   NA
D_overshoot_area_l   0.1n   NA   NA
[Voltage Range]   1.1000V   1.0600V   1.1700V
[Pullup Reference]   1.1000V   1.0600V   1.1700V
| Junction Temperature (Ambient temp is 35C typ 95C min -40C max)
[Temperature Range]   50.0   110.0   -40.0
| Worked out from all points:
|   slope of the pulldown table from 0 to 0.165 V, typ, clamps not added: 74.4 ohm
|   slope of the pullup table from 0 to 0.165 V, typ, clamps not added: 53.4 kohm
|   GND clamp passes 1 mA (typ) near -0.45 V on its own axis
|   POWER clamp passes 1 mA (typ) near -0.88 V on its own axis
|   rising waveform, R_fixture 50, V_fixture 0.0: 20-80 % time 47.3ps typ, 51.4ps min, 43.6ps max; typ from 0 V to 0.203 V
|   falling waveform, R_fixture 50, V_fixture 1.1: 20-80 % time 57.2ps typ, 67.4ps min, 46.8ps max; typ from 1.1 V to 0.726 V
|   rising waveform, R_fixture 50, V_fixture 1.1: 20-80 % time 56.6ps typ, 59.8ps min, 51.9ps max; typ from 0.726 V to 1.1 V
|   falling waveform, R_fixture 50, V_fixture 0.0: 20-80 % time 38.9ps typ, 45.7ps min, 33.6ps max; typ from 0.203 V to 0 V
[Pulldown]
|   Voltage   I(typ)   I(min)   I(max)
-1.1V     -19.27mA   -16.9mA    -21.53mA
-918.5mV  -16.93mA   -15.62mA   -18.7mA
-654.5mV  -13.22mA   -12.57mA   -14.35mA
-469.7mV  -9.758mA   -8.945mA   -10.92mA
-275mV    -4.715mA   -4.422mA   -5.257mA
-139.7mV  -2.09mA    -2.067mA   -2.115mA
210.1mV   2.772mA    2.744mA    2.794mA
487.3mV   5.732mA    5.538mA    6.069mA
774.4mV   7.759mA    7.172mA    8.741mA
1.071V    8.972mA    8.141mA    10.52mA
1.58V     10.3mA     9.319mA    12.22mA
2.2V      11.48mA    10.44mA    13.57mA
[GND Clamp]
|   Voltage   I(typ)   I(min)   I(max)
-1.1V     -34.75mA   -30.21mA   -42.92mA
-944.9mV  -25.23mA   -21.44mA   -31.56mA
-796.4mV  -16.12mA   -13.14mA   -21.2mA
-727.1mV  -12.12mA   -9.512mA   -16.34mA
-661.1mV  -8.569mA   -6.433mA   -11.86mA
-588.5mV  -5.115mA   -3.68mA    -7.306mA
-522.5mV  -2.666mA   -1.902mA   -3.814mA
-469.7mV  -1.357mA   -988.9uA   -1.787mA
-413.6mV  -563.9uA   -417.7uA   -622.2uA
-350.9mV  -166.3uA   -126.6uA   -147.3uA
-235.4mV  -8.194uA   -7.718uA   -4.444uA
2.2V      0A         0A         0A
[Pullup]
|   Voltage   I(typ)   I(min)   I(max)
-1.1V     1.369uA    2.477uA    453.9nA
243.1mV   -14.42uA   -14.59uA   -13.76uA
388.3mV   -192.7uA   -160.4uA   -230.5uA
500.5mV   -687.6uA   -616.7uA   -720.8uA
602.8mV   -1.401mA   -1.397mA   -1.348mA
738.1mV   -2.555mA   -2.79mA    -2.331mA
1.085V    -5.922mA   -6.936mA   -5.288mA
1.448V    -9.706mA   -11.28mA   -8.764mA
1.655V    -11.81mA   -13.36mA   -11.2mA
1.887V    -14.24mA   -15.08mA   -14.02mA
2.094V    -16.57mA   -16.71mA   -16.87mA
2.2V      -17.73mA   -17.39mA   -18.26mA
[POWER Clamp]
|   Voltage   I(typ)   I(min)   I(max)
-1.1V     3.033mA    3.633mA    2.184mA
-1.041V   2.345mA    2.929mA    1.625mA
-981.2mV  1.753mA    2.275mA    1.183mA
-908.6mV  1.177mA    1.582mA    748.4uA
-852.5mV  818.5uA    1.148mA    543.7uA
-796.4mV  521.2uA    794.9uA    427.2uA
-740.3mV  306uA      494.5uA    324.2uA
-671mV    164.5uA    216uA      210.2uA
-598.4mV  83.68uA    71.96uA    113uA
-499.4mV  21.26uA    13.1uA     27.45uA
-387.2mV  1.88uA     1.297uA    1.61uA
2.2V      0A         0A         0A
[Ramp]
|   typ   min   max
| 20% - 80%
dV/dt_r   121.49m/47.34p   123.78m/51.42p   125.29m/43.58p
dV/dt_f   224.45m/57.19p   206.41m/67.38p   255.16m/46.73p
| 25% - 75%
|dV/dt_r   101.24m/37.61p   103.15m/41.00p   104.40m/34.62p
|dV/dt_f   187.04m/45.49p   172.01m/53.78p   212.63m/37.13p
R_load = 50
[Rising Waveform]
R_fixture = 50
V_fixture = 0.0
|   Time   V(typ)   V(min)   V(max)
0s        271.2uV    210uV      203.8uV
59ps      -359.1uV   126.2uV    1.346mV
69ps      -702uV     -544.8uV   18.12mV
79ps      3.718mV    -909uV     52.11mV
105ps     77.3mV     12.32mV    138.3mV
127ps     137.4mV    73.48mV    176.7mV
148ps     170.3mV    130.1mV    194.3mV
176ps     190.7mV    174.8mV    204mV
212ps     199.6mV    197.6mV    207.7mV
360ps     202.8mV    206.5mV    209mV
[Falling Waveform]
R_fixture   = 50
V_fixture   = 1.1
V_fixture_min = 1.06
V_fixture_max = 1.17
|   Time   V(typ)   V(min)   V(max)
0s        1.1V       1.06V      1.17V
73ps      1.1V       1.06V      1.166V
82ps      1.101V     1.06V      1.124V
97ps      1.088V     1.06V      1.016V
120ps     980.3mV    1.051V     881.1mV
140ps     886.5mV    987.6mV    814.9mV
163ps     813.3mV    896.7mV    776.5mV
192ps     764.4mV    812.5mV    756.3mV
229ps     738.9mV    755.6mV    748mV
360ps     725.9mV    716mV      744.7mV
[Rising Waveform]
R_fixture   = 50
V_fixture   = 1.1
V_fixture_min = 1.06
V_fixture_max = 1.17
|   Time   V(typ)   V(min)   V(max)
0s        725.5mV    714.2mV    744.7mV
56ps      722.4mV    710mV      755.3mV
63ps      728.3mV    708.1mV    786.7mV
72ps      754.1mV    711.4mV    857.2mV
83ps      816.6mV    734.5mV    937.7mV
96ps      894.2mV    793.8mV    1.006V
119ps     983.7mV    903mV      1.081V
147ps     1.042V     978mV      1.128V
217ps     1.09V      1.044V     1.163V
360ps     1.1V       1.059V     1.17V
[Falling Waveform]
R_fixture = 50
V_fixture = 0.0
|   Time   V(typ)   V(min)   V(max)
0s        202.9mV    206.6mV    209.1mV
59ps      205mV      208.1mV    208.6mV
76ps      199.9mV    212.6mV    166mV
88ps      173.1mV    207.8mV    102.1mV
99ps      129.4mV    188.1mV    64.35mV
116ps     69.44mV    136.4mV    31.98mV
135ps     33.73mV    77.08mV    14.66mV
160ps     13.18mV    32.16mV    5.437mV
192ps     4.137mV    10.48mV    1.627mV
360ps     352.2uV    347.4uV    229.3uV
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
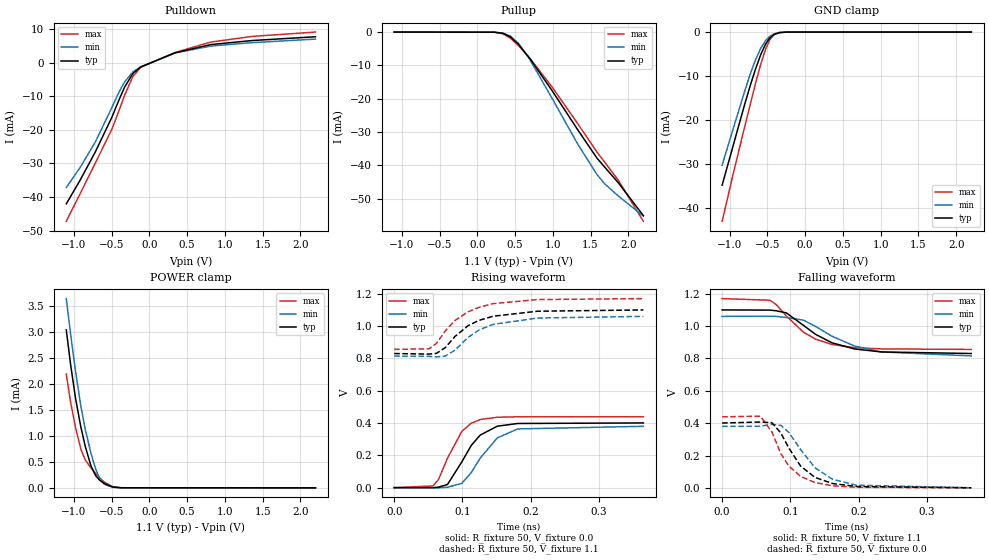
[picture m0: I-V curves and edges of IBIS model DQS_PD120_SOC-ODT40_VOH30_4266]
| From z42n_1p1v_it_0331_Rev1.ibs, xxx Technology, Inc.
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| DQS_PD120_SOC-ODT40_VOH30_4266
| (120 Ohm Pulldown, 40 Ohm System ODT Setting, VOH=VDDQ/3.0, 3200-4266Mbps)
[Model]   DQS_PD120_SOC-ODT40_VOH30_4266
Model_type   I/O
Vinl = 123.333mV
Vinh = 243.333mV
Vmeas = 183.333mV
Vref = 0.0mV
Cref = 0.0pF
Rref = 40.000Ohm
|   typ   min   max
|C_comp   0.849pF   0.799pF   0.899pF
C_comp_pullup   0.4245pF   0.3995pF   0.4495pF
C_comp_pulldown   0.4245pF   0.3995pF   0.4495pF
| Note: C_comp changes when the ODT circuit is enabled.
[Model Spec]
| Input threshold voltage corners
Vinl   0.1233V   0.1167V   0.1350V
Vinh   0.2433V   0.2367V   0.2550V
| Measurement voltage corners
Vmeas   0.1833V   0.1767V   0.1950V
| Timing spec test load voltage corners
Vref   0.0000V   0.0000V   0.0000V
| Dynamic Overshoot Parameters from LPDDR4 Specification
D_overshoot_ampl_h   0.30   NA   NA
D_overshoot_ampl_l   0.30   NA   NA
D_overshoot_area_h   0.1n   NA   NA
D_overshoot_area_l   0.1n   NA   NA
[Voltage Range]   1.1000V   1.0600V   1.1700V
[Pullup Reference]   1.1000V   1.0600V   1.1700V
| Junction Temperature (Ambient temp is 35C typ 95C min -40C max)
[Temperature Range]   50.0   110.0   -40.0
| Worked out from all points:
|   slope of the pulldown table from 0 to 0.165 V, typ, clamps not added: 109 ohm
|   slope of the pullup table from 0 to 0.165 V, typ, clamps not added: 13.1 kohm
|   GND clamp passes 1 mA (typ) near -0.45 V on its own axis
|   POWER clamp passes 1 mA (typ) near -0.88 V on its own axis
|   rising waveform, R_fixture 50, V_fixture 0.0: 20-80 % time 35.4ps typ, 39.6ps min, 30.5ps max; typ from 0.001 V to 0.401 V
|   falling waveform, R_fixture 50, V_fixture 1.1: 20-80 % time 62.2ps typ, 72.3ps min, 52.5ps max; typ from 1.1 V to 0.831 V
|   rising waveform, R_fixture 50, V_fixture 1.1: 20-80 % time 52.9ps typ, 52.7ps min, 51.5ps max; typ from 0.83 V to 1.1 V
|   falling waveform, R_fixture 50, V_fixture 0.0: 20-80 % time 41.2ps typ, 46.2ps min, 36.8ps max; typ from 0.401 V to 0.001 V
[Pulldown]
|   Voltage   I(typ)   I(min)   I(max)
-1.1V     -42.06mA   -37.2mA    -47.23mA
-918.5mV  -35.07mA   -31.29mA   -39.13mA
-717.2mV  -26.67mA   -23.72mA   -30mA
-496.1mV  -16.29mA   -13.39mA   -19.82mA
-400.4mV  -11.03mA   -8.716mA   -14.23mA
-327.8mV  -7.323mA   -5.761mA   -9.745mA
-218.9mV  -3.297mA   -2.831mA   -4.195mA
-116.6mV  -1.353mA   -1.284mA   -1.418mA
342.1mV   2.902mA    2.843mA    2.995mA
814mV     5.339mA    4.905mA    6.088mA
1.362V    6.546mA    5.916mA    7.77mA
2.2V      7.669mA    6.972mA    9.07mA
[GND Clamp]
|   Voltage   I(typ)   I(min)   I(max)
-1.1V     -34.74mA   -30.21mA   -42.91mA
-935mV    -24.6mA    -20.89mA   -30.85mA
-796.4mV  -16.11mA   -13.14mA   -21.19mA
-720.5mV  -11.75mA   -9.185mA   -15.87mA
-661.1mV  -8.566mA   -6.435mA   -11.85mA
-588.5mV  -5.112mA   -3.681mA   -7.299mA
-522.5mV  -2.665mA   -1.902mA   -3.811mA
-466.4mV  -1.296mA   -942uA     -1.693mA
-413.6mV  -568.6uA   -417.4uA   -622.3uA
-344.3mV  -143.4uA   -109.8uA   -125uA
-245.3mV  -11.2uA    -10.07uA   -6.356uA
2.2V      0A         0A         0A
[Pullup]
|   Voltage   I(typ)   I(min)   I(max)
-1.1V     6.275uA    9.671uA    2.829uA
223.3mV   -39.23uA   -40.42uA   -39.42uA
338.8mV   -360.6uA   -299.1uA   -496.6uA
437.8mV   -1.436mA   -1.178mA   -1.808mA
546.7mV   -3.712mA   -3.398mA   -4.054mA
695.2mV   -7.909mA   -8.165mA   -7.815mA
988.9mV   -17.49mA   -19.81mA   -16.41mA
1.335V    -29.45mA   -33.75mA   -27.61mA
1.586V    -37.82mA   -42.74mA   -36.02mA
1.688V    -40.51mA   -45.51mA   -39.01mA
1.867V    -45.16mA   -49.15mA   -44.41mA
2.2V      -55.05mA   -55.17mA   -56.74mA
[POWER Clamp]
|   Voltage   I(typ)   I(min)   I(max)
-1.1V     3.033mA    3.633mA    2.184mA
-1.044V   2.381mA    2.967mA    1.653mA
-977.9mV  1.723mA    2.241mA    1.16mA
-908.6mV  1.178mA    1.581mA    748.1uA
-849.2mV  799uA      1.125mA    535.4uA
-773.3mV  420.9uA    665.2uA    384.1uA
-710.6mV  232.2uA    359uA      273.1uA
-657.8mV  146.8uA    178.8uA    190.7uA
-595.1mV  80.79uA    68.28uA    109.3uA
-486.2mV  16.73uA    10.15uA    20.98uA
-374mV    1.382uA    995.2nA    1.127uA
2.2V      0A         0A         0A
[Ramp]
|   typ   min   max
| 20% - 80%
dV/dt_r   240.10m/35.42p   227.66m/39.65p   263.20m/30.51p
dV/dt_f   161.58m/62.18p   146.47m/72.38p   188.39m/52.38p
| 25% - 75%
|dV/dt_r   200.08m/28.19p   189.72m/31.54p   219.33m/24.27p
|dV/dt_f   134.65m/49.40p   122.06m/57.41p   157.00m/41.61p
R_load = 50
[Rising Waveform]
R_fixture = 50
V_fixture = 0.0
|   Time   V(typ)   V(min)   V(max)
0s        938.2uV    831.4uV    675.3uV
57ps      799.7uV    -21.5uV    11.49mV
65ps      4.262mV    -258.5uV   52.05mV
78ps      20.14mV    3.485mV    182.7mV
99ps      159.9mV    27.37mV    348.8mV
113ps     262.8mV    94.72mV    399.6mV
126ps     325.8mV    183.6mV    422.1mV
151ps     381mV      308.6mV    436.4mV
181ps     397.7mV    364.1mV    439.1mV
365ps     401.1mV    380.3mV    439.3mV
[Falling Waveform]
R_fixture   = 50
V_fixture   = 1.1
V_fixture_min = 1.06
V_fixture_max = 1.17
|   Time   V(typ)   V(min)   V(max)
0s        1.1V       1.06V      1.17V
70ps      1.099V     1.061V     1.16V
79ps      1.095V     1.06V      1.134V
94ps      1.082V     1.053V     1.063V
119ps     1.005V     1.037V     963mV
137ps     948.9mV    998.2mV    919.2mV
161ps     896.8mV    937.3mV    886.5mV
194ps     858.8mV    877.1mV    867mV
233ps     840.4mV    840.7mV    859.3mV
365ps     830.7mV    815.9mV    856mV
[Rising Waveform]
R_fixture   = 50
V_fixture   = 1.1
V_fixture_min = 1.06
V_fixture_max = 1.17
|   Time   V(typ)   V(min)   V(max)
0s        830.4mV    814.6mV    855.9mV
51ps      826.8mV    812.9mV    859.5mV
62ps      831.6mV    809.3mV    893mV
75ps      867.6mV    815mV      970.8mV
89ps      935.8mV    851mV      1.035V
108ps     1.002V     929.5mV    1.088V
124ps     1.035V     975.5mV    1.116V
145ps     1.061V     1.011V     1.139V
210ps     1.092V     1.05V      1.164V
365ps     1.1V       1.06V      1.17V
[Falling Waveform]
R_fixture = 50
V_fixture = 0.0
|   Time   V(typ)   V(min)   V(max)
0s        401.2mV    380.4mV    439.4mV
56ps      407.4mV    381.3mV    443.4mV
73ps      402.8mV    393.2mV    345.5mV
86ps      339.5mV    386.8mV    212.1mV
98ps      244.8mV    342mV      134mV
115ps     135.1mV    236.9mV    71.46mV
136ps     65.19mV    124.9mV    33.32mV
162ps     27.13mV    52.75mV    13.25mV
197ps     8.887mV    17.15mV    4.175mV
365ps     1.029mV    986.3uV    705.5uV
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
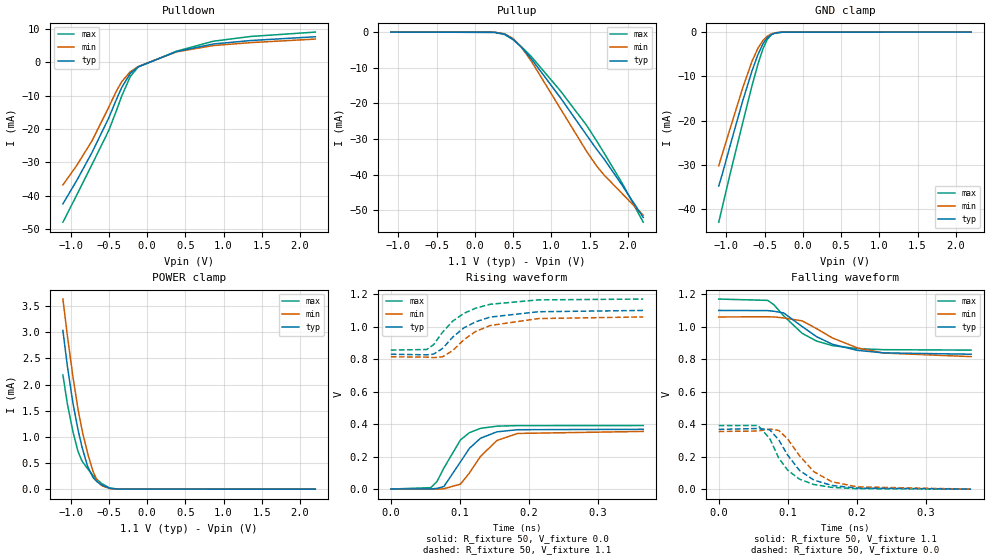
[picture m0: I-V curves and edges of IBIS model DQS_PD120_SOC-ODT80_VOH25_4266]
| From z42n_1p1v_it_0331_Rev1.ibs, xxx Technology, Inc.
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| DQS_PD120_SOC-ODT80_VOH25_4266
| (120 Ohm Pulldown, 80 Ohm System ODT Setting, VOH=VDDQ/2.5, 3200-4266Mbps)
[Model]   DQS_PD120_SOC-ODT80_VOH25_4266
Model_type   I/O
Vinl = 160.000mV
Vinh = 280.000mV
Vmeas = 220.000mV
Vref = 0.0mV
Cref = 0.0pF
Rref = 80.000Ohm
|   typ   min   max
|C_comp   0.849pF   0.799pF   0.899pF
C_comp_pullup   0.4245pF   0.3995pF   0.4495pF
C_comp_pulldown   0.4245pF   0.3995pF   0.4495pF
| Note: C_comp changes when the ODT circuit is enabled.
[Model Spec]
| Input threshold voltage corners
Vinl   0.1600V   0.1520V   0.1740V
Vinh   0.2800V   0.2720V   0.2940V
| Measurement voltage corners
Vmeas   0.2200V   0.2120V   0.2340V
| Timing spec test load voltage corners
Vref   0.0000V   0.0000V   0.0000V
| Dynamic Overshoot Parameters from LPDDR4 Specification
D_overshoot_ampl_h   0.30   NA   NA
D_overshoot_ampl_l   0.30   NA   NA
D_overshoot_area_h   0.1n   NA   NA
D_overshoot_area_l   0.1n   NA   NA
[Voltage Range]   1.1000V   1.0600V   1.1700V
[Pullup Reference]   1.1000V   1.0600V   1.1700V
| Junction Temperature (Ambient temp is 35C typ 95C min -40C max)
[Temperature Range]   50.0   110.0   -40.0
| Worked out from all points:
|   slope of the pulldown table from 0 to 0.165 V, typ, clamps not added: 108 ohm
|   slope of the pullup table from 0 to 0.165 V, typ, clamps not added: 17.5 kohm
|   GND clamp passes 1 mA (typ) near -0.45 V on its own axis
|   POWER clamp passes 1 mA (typ) near -0.88 V on its own axis
|   rising waveform, R_fixture 50, V_fixture 0.0: 20-80 % time 35.3ps typ, 39.2ps min, 32.1ps max; typ from 0.001 V to 0.368 V
|   falling waveform, R_fixture 50, V_fixture 1.1: 20-80 % time 62ps typ, 72.3ps min, 51.9ps max; typ from 1.1 V to 0.831 V
|   rising waveform, R_fixture 50, V_fixture 1.1: 20-80 % time 53.9ps typ, 54.9ps min, 51.6ps max; typ from 0.83 V to 1.1 V
|   falling waveform, R_fixture 50, V_fixture 0.0: 20-80 % time 41.6ps typ, 46.3ps min, 36.8ps max; typ from 0.368 V to 0.001 V
[Pulldown]
|   Voltage   I(typ)   I(min)   I(max)
-1.1V     -42.5mA    -36.8mA    -48mA
-918.5mV  -35.46mA   -30.95mA   -39.83mA
-720.5mV  -27.12mA   -23.61mA   -30.73mA
-499.4mV  -16.66mA   -13.42mA   -20.4mA
-400.4mV  -11.16mA   -8.631mA   -14.52mA
-331.1mV  -7.567mA   -5.826mA   -10.14mA
-218.9mV  -3.329mA   -2.814mA   -4.268mA
-116.6mV  -1.358mA   -1.28mA    -1.435mA
385mV     3.206mA    3.128mA    3.335mA
866.8mV   5.5mA      5.031mA    6.328mA
1.355V    6.535mA    5.906mA    7.757mA
2.2V      7.669mA    6.972mA    9.07mA
[GND Clamp]
|   Voltage   I(typ)   I(min)   I(max)
-1.1V     -34.75mA   -30.2mA    -42.92mA
-1.05V    -31.86mA   -27.33mA   -39.27mA
-944.9mV  -25.23mA   -21.44mA   -31.56mA
-786.5mV  -15.53mA   -12.6mA    -20.5mA
-664.4mV  -8.74mA    -6.576mA   -12.08mA
-588.5mV  -5.115mA   -3.68mA    -7.305mA
-522.5mV  -2.665mA   -1.903mA   -3.814mA
-466.4mV  -1.295mA   -944.6uA   -1.692mA
-413.6mV  -564.4uA   -418.1uA   -621.3uA
-357.5mV  -191.8uA   -144.8uA   -173uA
-258.5mV  -16.25uA   -14.26uA   -10.03uA
2.2V      0A         0A         0A
[Pullup]
|   Voltage   I(typ)   I(min)   I(max)
-1.1V     4.106uA    7.431uA    1.361uA
259.6mV   -60.47uA   -59.17uA   -61.43uA
391.6mV   -603uA     -500.3uA   -719.2uA
503.8mV   -2.098mA   -1.889mA   -2.195mA
609.4mV   -4.297mA   -4.297mA   -4.127mA
741.4mV   -7.628mA   -8.301mA   -6.975mA
1.121V    -18.53mA   -21.63mA   -16.6mA
1.461V    -28.96mA   -33.53mA   -26.23mA
1.589V    -32.85mA   -37.56mA   -30.49mA
1.688V    -35.63mA   -40.13mA   -33.95mA
1.926V    -43.06mA   -45.39mA   -42.49mA
2.2V      -52.05mA   -51.41mA   -53.39mA
[POWER Clamp]
|   Voltage   I(typ)   I(min)   I(max)
-1.1V     3.033mA    3.633mA    2.184mA
-1.041V   2.345mA    2.929mA    1.626mA
-968mV    1.637mA    2.139mA    1.094mA
-902mV    1.132mA    1.527mA    717.2uA
-849.2mV  798.9uA    1.126mA    535.8uA
-776.6mV  434.2uA    683.4uA    390.2uA
-707.3mV  225.5uA    345.7uA    267.6uA
-654.5mV  142.6uA    170.4uA    185.9uA
-598.4mV  83.65uA    71.98uA    113uA
-489.5mV  17.78uA    10.98uA    22.46uA
-377.3mV  1.49uA     1.062uA    1.227uA
2.2V      0A         0A         0A
[Ramp]
|   typ   min   max
| 20% - 80%
dV/dt_r   220.43m/35.33p   212.79m/39.18p   234.55m/32.12p
dV/dt_f   161.60m/61.86p   146.48m/72.39p   188.40m/51.96p
| 25% - 75%
|dV/dt_r   183.69m/28.11p   177.32m/31.19p   195.46m/25.51p
|dV/dt_f   134.67m/49.10p   122.07m/57.51p   157.00m/41.27p
R_load = 50
[Rising Waveform]
R_fixture = 50
V_fixture = 0.0
|   Time   V(typ)   V(min)   V(max)
0s        972.3uV    804.8uV    709.7uV
58ps      1.078mV    20.99uV    9.264mV
67ps      4.781mV    -49.41uV   47.09mV
77ps      16.25mV    2.537mV    130.4mV
101ps     168mV      31.04mV    303.3mV
114ps     251.1mV    99.41mV    347.6mV
130ps     313.3mV    201.5mV    374.2mV
154ps     353mV      299.8mV    387.8mV
184ps     365.8mV    342.9mV    391.1mV
366ps     368.4mV    355.4mV    391.6mV
[Falling Waveform]
R_fixture   = 50
V_fixture   = 1.1
V_fixture_min = 1.06
V_fixture_max = 1.17
|   Time   V(typ)   V(min)   V(max)
0s        1.1V       1.06V      1.17V
71ps      1.099V     1.061V     1.162V
80ps      1.095V     1.06V      1.135V
94ps      1.085V     1.054V     1.067V
121ps     1.001V     1.036V     959.1mV
142ps     938.2mV    987.8mV    911.5mV
165ps     891.7mV    930.5mV    883.5mV
201ps     854.5mV    869.6mV    865.1mV
239ps     839mV      838mV      858.7mV
366ps     830.7mV    815.9mV    856mV
[Rising Waveform]
R_fixture   = 50
V_fixture   = 1.1
V_fixture_min = 1.06
V_fixture_max = 1.17
|   Time   V(typ)   V(min)   V(max)
0s        830.4mV    814.6mV    855.9mV
52ps      826.8mV    812.6mV    859.7mV
62ps      831.3mV    809.5mV    889mV
75ps      865.6mV    814.7mV    965.9mV
90ps      936.7mV    853.6mV    1.035V
106ps     992.8mV    920.1mV    1.082V
123ps     1.03V      970.6mV    1.114V
144ps     1.059V     1.007V     1.138V
214ps     1.092V     1.05V      1.165V
366ps     1.1V       1.06V      1.17V
[Falling Waveform]
R_fixture = 50
V_fixture = 0.0
|   Time   V(typ)   V(min)   V(max)
0s        368.5mV    355.6mV    391.7mV
57ps      373.8mV    358.4mV    392.5mV
74ps      366.4mV    370.4mV    312.3mV
87ps      304.2mV    362.1mV    192.3mV
100ps     209.8mV    309.3mV    117.2mV
117ps     116.4mV    207mV      62.57mV
138ps     56.5mV     108mV      29.17mV
164ps     23.64mV    46.46mV    11.7mV
201ps     7.431mV    14.69mV    3.582mV
366ps     1.046mV    960uV      738.7uV
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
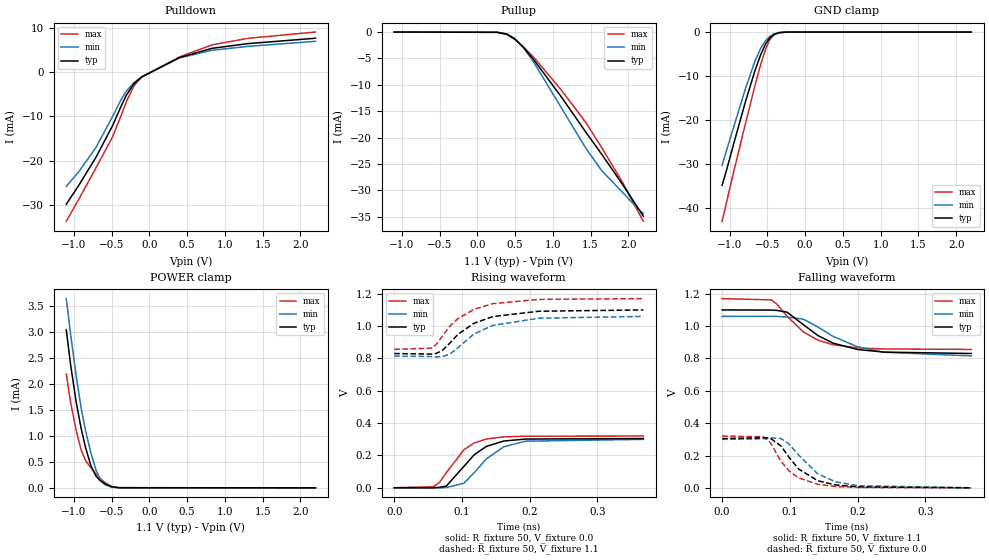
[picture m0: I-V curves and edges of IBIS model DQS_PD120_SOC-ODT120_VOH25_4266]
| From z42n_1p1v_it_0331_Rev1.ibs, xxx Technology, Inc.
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| DQS_PD120_SOC-ODT120_VOH25_4266
| (120 Ohm Pulldown, 120 Ohm System ODT Setting, VOH=VDDQ/2.5, 3200-4266Mbps)
[Model]   DQS_PD120_SOC-ODT120_VOH25_4266
Model_type   I/O
Vinl = 160.000mV
Vinh = 280.000mV
Vmeas = 220.000mV
Vref = 0.0mV
Cref = 0.0pF
Rref = 120.000Ohm
|   typ   min   max
|C_comp   0.849pF   0.799pF   0.899pF
C_comp_pullup   0.4245pF   0.3995pF   0.4495pF
C_comp_pulldown   0.4245pF   0.3995pF   0.4495pF
| Note: C_comp changes when the ODT circuit is enabled.
[Model Spec]
| Input threshold voltage corners
Vinl   0.1600V   0.1520V   0.1740V
Vinh   0.2800V   0.2720V   0.2940V
| Measurement voltage corners
Vmeas   0.2200V   0.2120V   0.2340V
| Timing spec test load voltage corners
Vref   0.0000V   0.0000V   0.0000V
| Dynamic Overshoot Parameters from LPDDR4 Specification
D_overshoot_ampl_h   0.30   NA   NA
D_overshoot_ampl_l   0.30   NA   NA
D_overshoot_area_h   0.1n   NA   NA
D_overshoot_area_l   0.1n   NA   NA
[Voltage Range]   1.1000V   1.0600V   1.1700V
[Pullup Reference]   1.1000V   1.0600V   1.1700V
| Junction Temperature (Ambient temp is 35C typ 95C min -40C max)
[Temperature Range]   50.0   110.0   -40.0
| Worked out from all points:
|   slope of the pulldown table from 0 to 0.165 V, typ, clamps not added: 109 ohm
|   slope of the pullup table from 0 to 0.165 V, typ, clamps not added: 26.6 kohm
|   GND clamp passes 1 mA (typ) near -0.45 V on its own axis
|   POWER clamp passes 1 mA (typ) near -0.88 V on its own axis
|   rising waveform, R_fixture 50, V_fixture 0.0: 20-80 % time 40.3ps typ, 44ps min, 36.8ps max; typ from 0.001 V to 0.305 V
|   falling waveform, R_fixture 50, V_fixture 1.1: 20-80 % time 61.1ps typ, 71.1ps min, 51.7ps max; typ from 1.1 V to 0.831 V
|   rising waveform, R_fixture 50, V_fixture 1.1: 20-80 % time 55.1ps typ, 57.5ps min, 51.5ps max; typ from 0.83 V to 1.1 V
|   falling waveform, R_fixture 50, V_fixture 0.0: 20-80 % time 41.8ps typ, 47ps min, 37.1ps max; typ from 0.305 V to 0.001 V
[Pulldown]
|   Voltage   I(typ)   I(min)   I(max)
-1.1V     -29.87mA   -25.83mA   -33.73mA
-935mV    -25.62mA   -22.54mA   -28.77mA
-707.3mV  -19.27mA   -17.05mA   -21.68mA
-486.2mV  -12.09mA   -10.02mA   -14.59mA
-380.6mV  -7.948mA   -6.414mA   -10.08mA
-304.7mV  -5.221mA   -4.289mA   -6.699mA
-202.4mV  -2.585mA   -2.33mA    -3.06mA
-100.1mV  -1.078mA   -1.043mA   -1.096mA
398.2mV   3.296mA    3.212mA    3.438mA
830.5mV   5.391mA    4.945mA    6.165mA
1.306V    6.452mA    5.831mA    7.652mA
2.2V      7.669mA    6.972mA    9.07mA
[GND Clamp]
|   Voltage   I(typ)   I(min)   I(max)
-1.1V     -34.75mA   -30.21mA   -42.92mA
-1.037V   -31.05mA   -26.58mA   -38.3mA
-944.9mV  -25.23mA   -21.44mA   -31.56mA
-789.8mV  -15.73mA   -12.78mA   -20.73mA
-664.4mV  -8.74mA    -6.576mA   -12.08mA
-588.5mV  -5.115mA   -3.68mA    -7.305mA
-522.5mV  -2.666mA   -1.903mA   -3.813mA
-469.7mV  -1.356mA   -986.1uA   -1.787mA
-413.6mV  -565.1uA   -416.4uA   -620.7uA
-347.6mV  -154.3uA   -117.4uA   -135.5uA
-251.9mV  -13.38uA   -11.89uA   -7.924uA
2.2V      0A         0A         0A
[Pullup]
|   Voltage   I(typ)   I(min)   I(max)
-1.1V     2.737uA    4.954uA    907.4nA
266.2mV   -46.06uA   -45.34uA   -47.87uA
391.6mV   -403.2uA   -334.2uA   -479.9uA
497.2mV   -1.328mA   -1.186mA   -1.397mA
606.1mV   -2.828mA   -2.823mA   -2.719mA
748mV     -5.234mA   -5.722mA   -4.774mA
1.108V    -12.17mA   -14.22mA   -10.89mA
1.441V    -19.03mA   -22.09mA   -17.2mA
1.655V    -23.3mA    -26.38mA   -22.06mA
1.933V    -29.06mA   -30.5mA    -28.72mA
2.121V    -33.18mA   -33.4mA    -33.8mA
2.2V      -34.89mA   -34.36mA   -35.86mA
[POWER Clamp]
|   Voltage   I(typ)   I(min)   I(max)
-1.1V     3.033mA    3.633mA    2.184mA
-1.041V   2.345mA    2.929mA    1.625mA
-968mV    1.637mA    2.139mA    1.094mA
-905.3mV  1.155mA    1.553mA    732.3uA
-845.9mV  779.9uA    1.103mA    527.4uA
-773.3mV  420.7uA    665.2uA    384.1uA
-707.3mV  225.5uA    345.4uA    267.6uA
-651.2mV  138.6uA    162.4uA    181.2uA
-591.8mV  77.92uA    64.83uA    105.5uA
-499.4mV  21.32uA    13.13uA    27.43uA
-400.4mV  2.57uA     1.7uA      2.311uA
2.2V      0A         0A         0A
[Ramp]
|   typ   min   max
| 20% - 80%
dV/dt_r   182.47m/40.32p   179.53m/44.00p   191.77m/36.76p
dV/dt_f   161.58m/61.12p   146.48m/71.15p   188.38m/51.71p
| 25% - 75%
|dV/dt_r   152.06m/32.10p   149.61m/35.06p   159.81m/29.23p
|dV/dt_f   134.65m/48.61p   122.06m/56.66p   156.98m/41.00p
R_load = 50
[Rising Waveform]
R_fixture = 50
V_fixture = 0.0
|   Time   V(typ)   V(min)   V(max)
0s        649.5uV    533.1uV    475.6uV
58ps      810.3uV    43.63uV    6.641mV
67ps      3.137mV    61.69uV    34.11mV
77ps      11.22mV    1.86mV     93.61mV
103ps     133.1mV    28.37mV    235.8mV
118ps     203.9mV    93.33mV    277mV
136ps     256.1mV    178.6mV    302mV
162ps     289.6mV    254.2mV    315.3mV
194ps     301.6mV    288.5mV    319.2mV
368ps     304.8mV    299.7mV    320.1mV
[Falling Waveform]
R_fixture   = 50
V_fixture   = 1.1
V_fixture_min = 1.06
V_fixture_max = 1.17
|   Time   V(typ)   V(min)   V(max)
0s        1.1V       1.06V      1.17V
73ps      1.099V     1.061V     1.162V
81ps      1.097V     1.06V      1.135V
96ps      1.086V     1.056V     1.061V
120ps     1.009V     1.043V     963.9mV
142ps     940.4mV    993.1mV    912.3mV
164ps     894.5mV    936.3mV    884.7mV
200ps     855.5mV    872.2mV    865.4mV
239ps     839.4mV    838.6mV    858.8mV
368ps     830.7mV    815.9mV    856mV
[Rising Waveform]
R_fixture   = 50
V_fixture   = 1.1
V_fixture_min = 1.06
V_fixture_max = 1.17
|   Time   V(typ)   V(min)   V(max)
0s        830.4mV    814.6mV    855.9mV
55ps      827.1mV    811.8mV    863.9mV
62ps      830.9mV    809.8mV    886mV
71ps      848.9mV    811.2mV    937.1mV
82ps      894.1mV    826.8mV    998.2mV
94ps      948.6mV    865.8mV    1.046V
118ps     1.018V     952.1mV    1.104V
146ps     1.059V     1.005V     1.139V
214ps     1.092V     1.049V     1.165V
368ps     1.1V       1.06V      1.17V
[Falling Waveform]
R_fixture = 50
V_fixture = 0.0
|   Time   V(typ)   V(min)   V(max)
0s        304.9mV    299.8mV    320.2mV
61ps      310.1mV    304mV      316.5mV
71ps      307.7mV    309.6mV    281.8mV
87ps      259.2mV    305mV      164.2mV
99ps      188.4mV    270.3mV    104.1mV
113ps     116.8mV    202.9mV    62.03mV
141ps     44.75mV    87.97mV    22.53mV
167ps     18.77mV    38.26mV    9.045mV
201ps     6.396mV    13.29mV    2.96mV
368ps     748.6uV    711.3uV    514.3uV
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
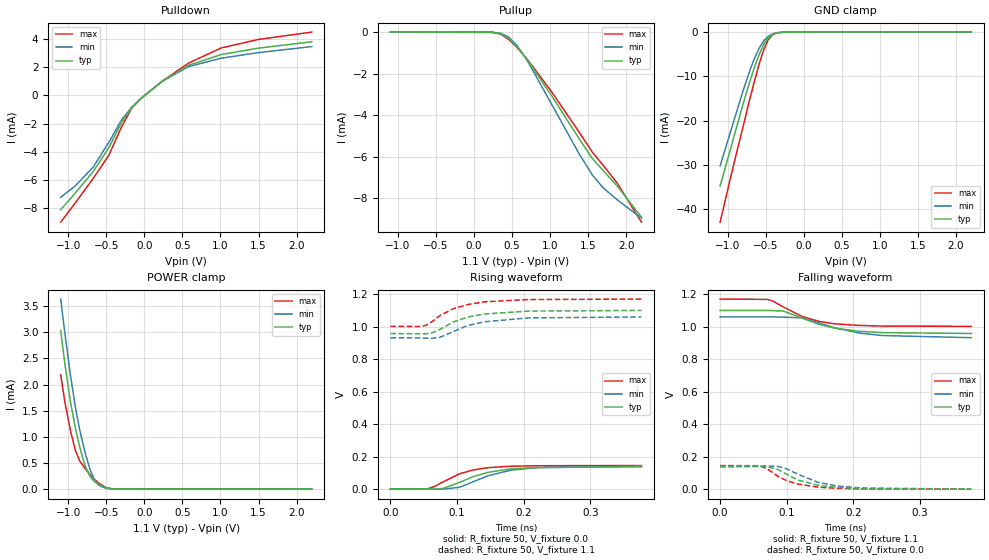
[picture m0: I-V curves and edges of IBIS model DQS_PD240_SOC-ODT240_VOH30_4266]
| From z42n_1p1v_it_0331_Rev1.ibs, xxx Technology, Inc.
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| DQS_PD240_SOC-ODT240_VOH30_4266
| (240 Ohm Pulldown, 240 Ohm System ODT Setting, VOH=VDDQ/3.0, 3200-4266Mbps)
[Model]   DQS_PD240_SOC-ODT240_VOH30_4266
Model_type   I/O
Vinl = 123.333mV
Vinh = 243.333mV
Vmeas = 183.333mV
Vref = 0.0mV
Cref = 0.0pF
Rref = 240.000Ohm
|   typ   min   max
|C_comp   0.849pF   0.799pF   0.899pF
C_comp_pullup   0.4245pF   0.3995pF   0.4495pF
C_comp_pulldown   0.4245pF   0.3995pF   0.4495pF
| Note: C_comp changes when the ODT circuit is enabled.
[Model Spec]
| Input threshold voltage corners
Vinl   0.1233V   0.1167V   0.1350V
Vinh   0.2433V   0.2367V   0.2550V
| Measurement voltage corners
Vmeas   0.1833V   0.1767V   0.1950V
| Timing spec test load voltage corners
Vref   0.0000V   0.0000V   0.0000V
| Dynamic Overshoot Parameters from LPDDR4 Specification
D_overshoot_ampl_h   0.30   NA   NA
D_overshoot_ampl_l   0.30   NA   NA
D_overshoot_area_h   0.1n   NA   NA
D_overshoot_area_l   0.1n   NA   NA
[Voltage Range]   1.1000V   1.0600V   1.1700V
[Pullup Reference]   1.1000V   1.0600V   1.1700V
| Junction Temperature (Ambient temp is 35C typ 95C min -40C max)
[Temperature Range]   50.0   110.0   -40.0
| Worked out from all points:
|   slope of the pulldown table from 0 to 0.165 V, typ, clamps not added: 227 ohm
|   slope of the pullup table from 0 to 0.165 V, typ, clamps not added: 80.6 kohm
|   GND clamp passes 1 mA (typ) near -0.45 V on its own axis
|   POWER clamp passes 1 mA (typ) near -0.88 V on its own axis
|   rising waveform, R_fixture 50, V_fixture 0.0: 20-80 % time 57.9ps typ, 60.2ps min, 49.7ps max; typ from 0 V to 0.137 V
|   falling waveform, R_fixture 50, V_fixture 1.1: 20-80 % time 65.7ps typ, 73.6ps min, 56.9ps max; typ from 1.1 V to 0.958 V
|   rising waveform, R_fixture 50, V_fixture 1.1: 20-80 % time 55ps typ, 59ps min, 52.2ps max; typ from 0.958 V to 1.1 V
|   falling waveform, R_fixture 50, V_fixture 0.0: 20-80 % time 49.4ps typ, 54.9ps min, 44.9ps max; typ from 0.137 V to 0 V
[Pulldown]
|   Voltage   I(typ)   I(min)   I(max)
-1.1V     -8.12mA    -7.248mA   -9.014mA
-908.6mV  -6.948mA   -6.43mA    -7.646mA
-671mV    -5.396mA   -5.082mA   -5.888mA
-466.4mV  -3.714mA   -3.332mA   -4.246mA
-304.7mV  -1.965mA   -1.772mA   -2.292mA
-169.4mV  -879.1uA   -852.6uA   -923.6uA
-37.4mV   -181.6uA   -180.4uA   -176.9uA
236.5mV   1.014mA    1.004mA    1.02mA
579.7mV   2.14mA     2.047mA    2.296mA
1.009V    2.904mA    2.645mA    3.372mA
1.497V    3.359mA    3.041mA    3.977mA
2.2V      3.814mA    3.471mA    4.502mA
[GND Clamp]
|   Voltage   I(typ)   I(min)   I(max)
-1.1V     -34.74mA   -30.22mA   -42.91mA
-948.2mV  -25.43mA   -21.63mA   -31.79mA
-793.1mV  -15.92mA   -12.96mA   -20.95mA
-720.5mV  -11.75mA   -9.185mA   -15.87mA
-661.1mV  -8.566mA   -6.435mA   -11.85mA
-585.2mV  -4.971mA   -3.575mA   -7.106mA
-522.5mV  -2.665mA   -1.903mA   -3.81mA
-469.7mV  -1.359mA   -986.6uA   -1.788mA
-413.6mV  -568.2uA   -417.4uA   -621.6uA
-357.5mV  -191.4uA   -144.9uA   -173.6uA
-258.5mV  -16.37uA   -14.15uA   -9.865uA
2.2V      0A         0A         0A
[Pullup]
|   Voltage   I(typ)   I(min)   I(max)
-1.1V     1.046uA    1.612uA    471.3nA
243.1mV   -9.889uA   -9.793uA   -10.82uA
352mV     -74.48uA   -60.84uA   -102.8uA
451mV     -275.1uA   -228.1uA   -339.6uA
559.9mV   -671.2uA   -622.3uA   -724.2uA
705.1mV   -1.361mA   -1.411mA   -1.341mA
1.012V    -3.026mA   -3.43mA    -2.841mA
1.372V    -5.086mA   -5.812mA   -4.777mA
1.556V    -6.1mA     -6.899mA   -5.799mA
1.698V    -6.678mA   -7.51mA    -6.426mA
1.887V    -7.444mA   -8.098mA   -7.311mA
2.2V      -8.921mA   -8.964mA   -9.16mA
[POWER Clamp]
|   Voltage   I(typ)   I(min)   I(max)
-1.1V     3.033mA    3.633mA    2.184mA
-1.044V   2.381mA    2.967mA    1.653mA
-971.3mV  1.665mA    2.173mA    1.116mA
-905.3mV  1.155mA    1.553mA    732.8uA
-849.2mV  799.1uA    1.125mA    535.4uA
-779.9mV  447.8uA    701.4uA    396.3uA
-713.9mV  239.2uA    373uA      278.6uA
-654.5mV  142.7uA    170.4uA    185.9uA
-598.4mV  83.68uA    71.95uA    113uA
-502.7mV  22.59uA    13.98uA    29.24uA
-400.4mV  2.624uA    1.7uA      2.312uA
2.2V      0A         0A         0A
[Ramp]
|   typ   min   max
| 20% - 80%
dV/dt_r   82.31m/57.88p   84.05m/60.15p   87.09m/49.72p
dV/dt_f   85.15m/65.53p   76.64m/73.81p   100.76m/56.63p
| 25% - 75%
|dV/dt_r   68.59m/46.09p   70.04m/47.91p   72.58m/39.50p
|dV/dt_f   70.95m/52.30p   63.87m/58.82p   83.96m/44.92p
R_load = 50
[Rising Waveform]
R_fixture = 50
V_fixture = 0.0
|   Time   V(typ)   V(min)   V(max)
0s        186.1uV    158.1uV    137.1uV
56ps      -121.3uV   16.79uV    2.232mV
66ps      218.9uV    -275.3uV   15.36mV
79ps      3.93mV     144.5uV    44.58mV
104ps     41.57mV    11.44mV    94.52mV
124ps     76.2mV     44.82mV    117.8mV
147ps     103.7mV    82.69mV    132.2mV
180ps     124.1mV    115.8mV    140.8mV
219ps     133.2mV    132.2mV    144mV
377ps     137.4mV    140.2mV    145.3mV
[Falling Waveform]
R_fixture   = 50
V_fixture   = 1.1
V_fixture_min = 1.06
V_fixture_max = 1.17
|   Time   V(typ)   V(min)   V(max)
0s        1.1V       1.06V      1.17V
71ps      1.1V       1.06V      1.168V
79ps      1.099V     1.06V      1.158V
95ps      1.096V     1.059V     1.121V
123ps     1.053V     1.054V     1.063V
148ps     1.015V     1.024V     1.033V
171ps     991.7mV    994.2mV    1.018V
207ps     972.1mV    962.1mV    1.008V
243ps     963.6mV    945.6mV    1.004V
377ps     958.1mV    932.3mV    1.002V
[Rising Waveform]
R_fixture   = 50
V_fixture   = 1.1
V_fixture_min = 1.06
V_fixture_max = 1.17
|   Time   V(typ)   V(min)   V(max)
0s        957.9mV    931.6mV    1.002V
45ps      956.4mV    930.7mV    1.001V
53ps      956.3mV    929.2mV    1.008V
63ps      962.5mV    928.5mV    1.032V
74ps      982.6mV    934.3mV    1.067V
94ps      1.028V     969.4mV    1.11V
116ps     1.059V     1.007V     1.136V
141ps     1.078V     1.03V      1.153V
207ps     1.096V     1.054V     1.167V
377ps     1.1V       1.06V      1.17V
[Falling Waveform]
R_fixture = 50
V_fixture = 0.0
|   Time   V(typ)   V(min)   V(max)
0s        137.5mV    140.4mV    145.3mV
59ps      139.4mV    141.3mV    144.3mV
70ps      138.8mV    143.3mV    127.3mV
87ps      120.9mV    140.4mV    78.42mV
100ps     91.52mV    125.2mV    52.28mV
117ps     56.31mV    91.73mV    31.13mV
147ps     23.9mV     42.25mV    12.47mV
176ps     10.6mV     19.45mV    5.208mV
214ps     3.763mV    7.174mV    1.787mV
377ps     295.7uV    346.1uV    185.3uV
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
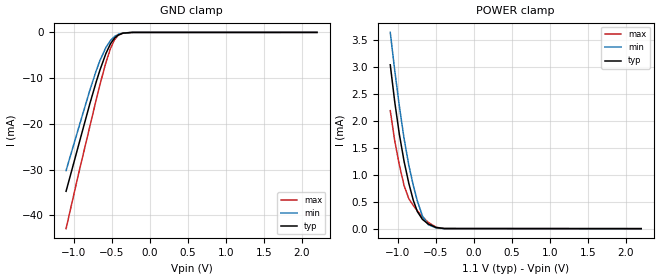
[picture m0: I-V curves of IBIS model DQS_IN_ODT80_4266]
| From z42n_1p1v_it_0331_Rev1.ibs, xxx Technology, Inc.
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| DQS_IN_ODT80_4266 (with 80ohm ODT, 3200-4266Mbps)
[Model]   DQS_IN_ODT80_4266
Model_type   Input
Vinl = 123.333mV
Vinh = 243.333mV
|   typ   min   max
|C_comp   0.829pF   0.783pF   0.879pF
C_comp_power_clamp   0.4145pF   0.3915pF   0.4395pF
C_comp_gnd_clamp   0.4145pF   0.3915pF   0.4395pF
| Note: C_comp changes when the ODT circuit is enabled.
[Model Spec]
| Input threshold voltage corners
Vinl   0.1233V   0.1167V   0.1350V
Vinh   0.2433V   0.2367V   0.2550V
| Dynamic Overshoot Parameters from LPDDR4 Specification
D_overshoot_ampl_h   0.30   NA   NA
D_overshoot_ampl_l   0.30   NA   NA
D_overshoot_area_h   0.1n   NA   NA
D_overshoot_area_l   0.1n   NA   NA
[Voltage Range]   1.1000V   1.0600V   1.1700V
[POWER Clamp Reference]   1.1000V   1.0600V   1.1700V
| Junction Temperature (Ambient temp is 35C typ 95C min -40C max)
[Temperature Range]   50.0   110.0   -40.0
[Add Submodel]
| Submodel Name   Mode
80ohm_ODT_4266   Non-Driving
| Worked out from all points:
|   GND clamp passes 1 mA (typ) near -0.45 V on its own axis
|   POWER clamp passes 1 mA (typ) near -0.88 V on its own axis
[GND Clamp]
|   Voltage   I(typ)   I(min)   I(max)
-1.1V     -34.74mA   -30.21mA   -42.91mA
-944.9mV  -25.23mA   -21.44mA   -31.56mA
-786.5mV  -15.53mA   -12.6mA    -20.49mA
-704mV    -10.84mA   -8.387mA   -14.74mA
-654.5mV  -8.229mA   -6.156mA   -11.42mA
-575.3mV  -4.574mA   -3.267mA   -6.539mA
-515.9mV  -2.484mA   -1.775mA   -3.512mA
-463.1mV  -1.249mA   -909.2uA   -1.597mA
-413.6mV  -575.8uA   -422.4uA   -623.6uA
-350.9mV  -168uA     -128.3uA   -147.4uA
-228.8mV  -7.219uA   -6.865uA   -4.033uA
2.2V      0A         0A         0A
[POWER Clamp]
|   Voltage   I(typ)   I(min)   I(max)
-1.1V     3.033mA    3.633mA    2.184mA
-1.041V   2.345mA    2.929mA    1.625mA
-981.2mV  1.753mA    2.275mA    1.183mA
-918.5mV  1.247mA    1.669mA    799.2uA
-855.8mV  837.7uA    1.173mA    553uA
-796.4mV  522uA      796.1uA    427.2uA
-743.6mV  316.1uA    512.4uA    330.1uA
-677.6mV  173uA      236.7uA    220.2uA
-601.7mV  87.05uA    76.12uA    117uA
-496.1mV  20.43uA    12.39uA    25.71uA
-387.2mV  1.97uA     1.327uA    1.64uA
2.2V      0A         0A         0A
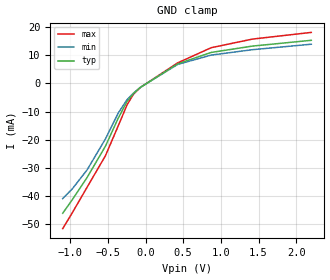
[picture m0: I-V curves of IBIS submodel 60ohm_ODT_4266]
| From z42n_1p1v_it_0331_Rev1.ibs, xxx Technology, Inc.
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| SUBMODEL 60ohm_ODT_4266
[Submodel]   60ohm_ODT_4266
Submodel_type   Dynamic_clamp
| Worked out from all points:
|   GND clamp passes 1 mA (typ) near -0.05 V on its own axis
[GND Clamp]
|   Voltage   I(typ)   I(min)   I(max)
-1.1V     -46.14mA   -40.93mA   -51.62mA
-974.6mV  -41.39mA   -37.53mA   -46.06mA
-776.6mV  -33.45mA   -30.74mA   -36.91mA
-532.4mV  -22.28mA   -19.7mA    -25.68mA
-364.1mV  -12.41mA   -10.58mA   -15.16mA
-245.3mV  -6.371mA   -5.75mA    -7.565mA
-159.5mV  -3.539mA   -3.391mA   -3.775mA
-67.1mV   -1.378mA   -1.361mA   -1.366mA
424.6mV   6.95mA     6.751mA    7.297mA
870.1mV   11.02mA    10.08mA    12.7mA
1.418V    13.28mA    12mA       15.77mA
2.2V      15.34mA    13.95mA    18.15mA
